VERSION 5.8 ;
BUSBITCHARS "[]" ;
DIVIDERCHAR "/" ;
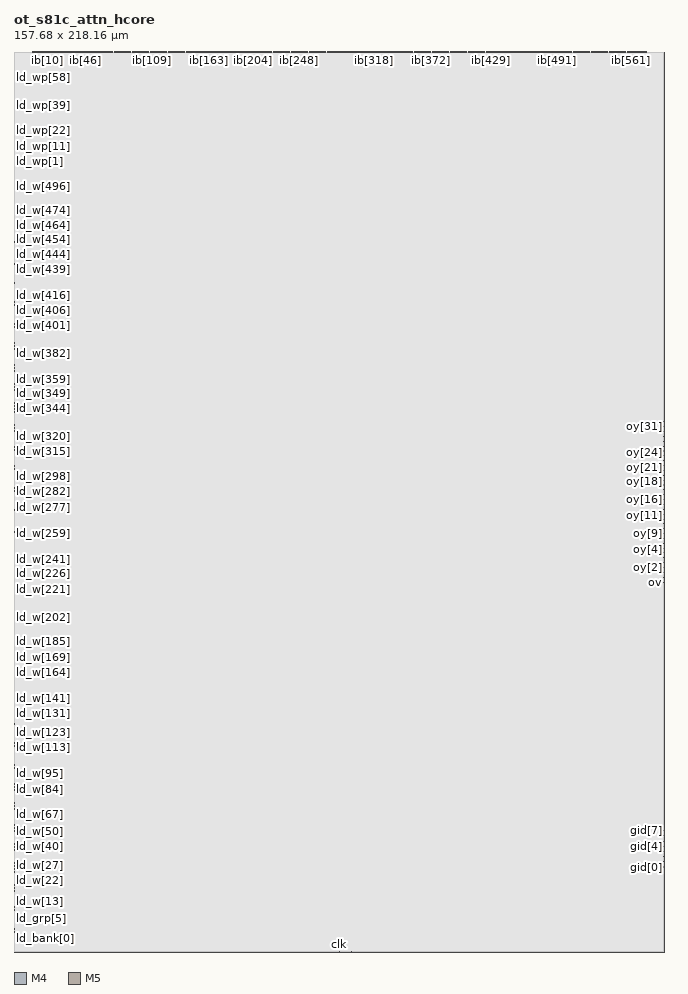
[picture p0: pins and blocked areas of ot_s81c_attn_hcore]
MACRO ot_s81c_attn_hcore
  CLASS BLOCK ;
  ORIGIN 0 0 ;
  FOREIGN ot_s81c_attn_hcore 0 0 ;
  SIZE 157.68 BY 218.16 ;
  SYMMETRY X Y ;
  PIN ld_v
    DIRECTION INPUT ;
    USE SIGNAL ;
    PORT
      LAYER M4 ;
        RECT 0.000 4.464 0.192 4.488 ;
    END
  END ld_v
  PIN ld_mode
    DIRECTION INPUT ;
    USE SIGNAL ;
    PORT
      LAYER M4 ;
        RECT 0.000 4.848 0.192 4.872 ;
    END
  END ld_mode
  PIN ld_bank[0]
    DIRECTION INPUT ;
    USE SIGNAL ;
    PORT
      LAYER M4 ;
        RECT 0.000 5.184 0.192 5.208 ;
    END
  END ld_bank[0]
  PIN ld_bank[1]
    DIRECTION INPUT ;
    USE SIGNAL ;
    PORT
      LAYER M4 ;
        RECT 0.000 5.568 0.192 5.592 ;
    END
  END ld_bank[1]
  PIN ld_bank[2]
    DIRECTION INPUT ;
    USE SIGNAL ;
    PORT
      LAYER M4 ;
        RECT 0.000 5.904 0.192 5.928 ;
    END
  END ld_bank[2]
  PIN ld_grp[0]
    DIRECTION INPUT ;
    USE SIGNAL ;
    PORT
      LAYER M4 ;
        RECT 0.000 6.240 0.192 6.264 ;
    END
  END ld_grp[0]
  PIN ld_grp[1]
    DIRECTION INPUT ;
    USE SIGNAL ;
    PORT
      LAYER M4 ;
        RECT 0.000 6.624 0.192 6.648 ;
    END
  END ld_grp[1]
  PIN ld_grp[2]
    DIRECTION INPUT ;
    USE SIGNAL ;
    PORT
      LAYER M4 ;
        RECT 0.000 6.960 0.192 6.984 ;
    END
  END ld_grp[2]
  PIN ld_grp[3]
    DIRECTION INPUT ;
    USE SIGNAL ;
    PORT
      LAYER M4 ;
        RECT 0.000 7.344 0.192 7.368 ;
    END
  END ld_grp[3]
  PIN ld_grp[4]
    DIRECTION INPUT ;
    USE SIGNAL ;
    PORT
      LAYER M4 ;
        RECT 0.000 7.680 0.192 7.704 ;
    END
  END ld_grp[4]
  PIN ld_grp[5]
    DIRECTION INPUT ;
    USE SIGNAL ;
    PORT
      LAYER M4 ;
        RECT 0.000 8.016 0.192 8.040 ;
    END
  END ld_grp[5]
  PIN ld_grp[6]
    DIRECTION INPUT ;
    USE SIGNAL ;
    PORT
      LAYER M4 ;
        RECT 0.000 8.400 0.192 8.424 ;
    END
  END ld_grp[6]
  PIN ld_grp[7]
    DIRECTION INPUT ;
    USE SIGNAL ;
    PORT
      LAYER M4 ;
        RECT 0.000 8.736 0.192 8.760 ;
    END
  END ld_grp[7]
  PIN ld_w2v
    DIRECTION INPUT ;
    USE SIGNAL ;
    PORT
      LAYER M4 ;
        RECT 0.000 9.120 0.192 9.144 ;
    END
  END ld_w2v
  PIN ld_w[0]
    DIRECTION INPUT ;
    USE SIGNAL ;
    PORT
      LAYER M4 ;
        RECT 0.000 9.456 0.192 9.480 ;
    END
  END ld_w[0]
  PIN ld_w[1]
    DIRECTION INPUT ;
    USE SIGNAL ;
    PORT
      LAYER M4 ;
        RECT 0.000 9.792 0.192 9.816 ;
    END
  END ld_w[1]
  PIN ld_w[2]
    DIRECTION INPUT ;
    USE SIGNAL ;
    PORT
      LAYER M4 ;
        RECT 0.000 10.176 0.192 10.200 ;
    END
  END ld_w[2]
  PIN ld_w[3]
    DIRECTION INPUT ;
    USE SIGNAL ;
    PORT
      LAYER M4 ;
        RECT 0.000 10.512 0.192 10.536 ;
    END
  END ld_w[3]
  PIN ld_w[4]
    DIRECTION INPUT ;
    USE SIGNAL ;
    PORT
      LAYER M4 ;
        RECT 0.000 10.896 0.192 10.920 ;
    END
  END ld_w[4]
  PIN ld_w[5]
    DIRECTION INPUT ;
    USE SIGNAL ;
    PORT
      LAYER M4 ;
        RECT 0.000 11.232 0.192 11.256 ;
    END
  END ld_w[5]
  PIN ld_w[6]
    DIRECTION INPUT ;
    USE SIGNAL ;
    PORT
      LAYER M4 ;
        RECT 0.000 11.568 0.192 11.592 ;
    END
  END ld_w[6]
  PIN ld_w[7]
    DIRECTION INPUT ;
    USE SIGNAL ;
    PORT
      LAYER M4 ;
        RECT 0.000 11.952 0.192 11.976 ;
    END
  END ld_w[7]
  PIN ld_w[8]
    DIRECTION INPUT ;
    USE SIGNAL ;
    PORT
      LAYER M4 ;
        RECT 0.000 12.288 0.192 12.312 ;
    END
  END ld_w[8]
  PIN ld_w[9]
    DIRECTION INPUT ;
    USE SIGNAL ;
    PORT
      LAYER M4 ;
        RECT 0.000 12.672 0.192 12.696 ;
    END
  END ld_w[9]
  PIN ld_w[10]
    DIRECTION INPUT ;
    USE SIGNAL ;
    PORT
      LAYER M4 ;
        RECT 0.000 13.008 0.192 13.032 ;
    END
  END ld_w[10]
  PIN ld_w[11]
    DIRECTION INPUT ;
    USE SIGNAL ;
    PORT
      LAYER M4 ;
        RECT 0.000 13.344 0.192 13.368 ;
    END
  END ld_w[11]
  PIN ld_w[12]
    DIRECTION INPUT ;
    USE SIGNAL ;
    PORT
      LAYER M4 ;
        RECT 0.000 13.728 0.192 13.752 ;
    END
  END ld_w[12]
  PIN ld_w[13]
    DIRECTION INPUT ;
    USE SIGNAL ;
    PORT
      LAYER M4 ;
        RECT 0.000 14.064 0.192 14.088 ;
    END
  END ld_w[13]
  PIN ld_w[14]
    DIRECTION INPUT ;
    USE SIGNAL ;
    PORT
      LAYER M4 ;
        RECT 0.000 14.448 0.192 14.472 ;
    END
  END ld_w[14]
  PIN ld_w[15]
    DIRECTION INPUT ;
    USE SIGNAL ;
    PORT
      LAYER M4 ;
        RECT 0.000 14.784 0.192 14.808 ;
    END
  END ld_w[15]
  PIN ld_w[16]
    DIRECTION INPUT ;
    USE SIGNAL ;
    PORT
      LAYER M4 ;
        RECT 0.000 15.120 0.192 15.144 ;
    END
  END ld_w[16]
  PIN ld_w[17]
    DIRECTION INPUT ;
    USE SIGNAL ;
    PORT
      LAYER M4 ;
        RECT 0.000 15.504 0.192 15.528 ;
    END
  END ld_w[17]
  PIN ld_w[18]
    DIRECTION INPUT ;
    USE SIGNAL ;
    PORT
      LAYER M4 ;
        RECT 0.000 15.840 0.192 15.864 ;
    END
  END ld_w[18]
  PIN ld_w[19]
    DIRECTION INPUT ;
    USE SIGNAL ;
    PORT
      LAYER M4 ;
        RECT 0.000 16.224 0.192 16.248 ;
    END
  END ld_w[19]
  PIN ld_w[20]
    DIRECTION INPUT ;
    USE SIGNAL ;
    PORT
      LAYER M4 ;
        RECT 0.000 16.560 0.192 16.584 ;
    END
  END ld_w[20]
  PIN ld_w[21]
    DIRECTION INPUT ;
    USE SIGNAL ;
    PORT
      LAYER M4 ;
        RECT 0.000 16.896 0.192 16.920 ;
    END
  END ld_w[21]
  PIN ld_w[22]
    DIRECTION INPUT ;
    USE SIGNAL ;
    PORT
      LAYER M4 ;
        RECT 0.000 17.280 0.192 17.304 ;
    END
  END ld_w[22]
  PIN ld_w[23]
    DIRECTION INPUT ;
    USE SIGNAL ;
    PORT
      LAYER M4 ;
        RECT 0.000 17.616 0.192 17.640 ;
    END
  END ld_w[23]
  PIN ld_w[24]
    DIRECTION INPUT ;
    USE SIGNAL ;
    PORT
      LAYER M4 ;
        RECT 0.000 18.000 0.192 18.024 ;
    END
  END ld_w[24]
  PIN ld_w[25]
    DIRECTION INPUT ;
    USE SIGNAL ;
    PORT
      LAYER M4 ;
        RECT 0.000 18.336 0.192 18.360 ;
    END
  END ld_w[25]
  PIN ld_w[26]
    DIRECTION INPUT ;
    USE SIGNAL ;
    PORT
      LAYER M4 ;
        RECT 0.000 18.672 0.192 18.696 ;
    END
  END ld_w[26]
  PIN ld_w[27]
    DIRECTION INPUT ;
    USE SIGNAL ;
    PORT
      LAYER M4 ;
        RECT 0.000 19.056 0.192 19.080 ;
    END
  END ld_w[27]
  PIN ld_w[28]
    DIRECTION INPUT ;
    USE SIGNAL ;
    PORT
      LAYER M4 ;
        RECT 0.000 19.392 0.192 19.416 ;
    END
  END ld_w[28]
  PIN ld_w[29]
    DIRECTION INPUT ;
    USE SIGNAL ;
    PORT
      LAYER M4 ;
        RECT 0.000 19.776 0.192 19.800 ;
    END
  END ld_w[29]
  PIN ld_w[30]
    DIRECTION INPUT ;
    USE SIGNAL ;
    PORT
      LAYER M4 ;
        RECT 0.000 20.112 0.192 20.136 ;
    END
  END ld_w[30]
  PIN ld_w[31]
    DIRECTION INPUT ;
    USE SIGNAL ;
    PORT
      LAYER M4 ;
        RECT 0.000 20.448 0.192 20.472 ;
    END
  END ld_w[31]
  PIN ld_w[32]
    DIRECTION INPUT ;
    USE SIGNAL ;
    PORT
      LAYER M4 ;
        RECT 0.000 20.832 0.192 20.856 ;
    END
  END ld_w[32]
  PIN ld_w[33]
    DIRECTION INPUT ;
    USE SIGNAL ;
    PORT
      LAYER M4 ;
        RECT 0.000 21.168 0.192 21.192 ;
    END
  END ld_w[33]
  PIN ld_w[34]
    DIRECTION INPUT ;
    USE SIGNAL ;
    PORT
      LAYER M4 ;
        RECT 0.000 21.552 0.192 21.576 ;
    END
  END ld_w[34]
  PIN ld_w[35]
    DIRECTION INPUT ;
    USE SIGNAL ;
    PORT
      LAYER M4 ;
        RECT 0.000 21.888 0.192 21.912 ;
    END
  END ld_w[35]
  PIN ld_w[36]
    DIRECTION INPUT ;
    USE SIGNAL ;
    PORT
      LAYER M4 ;
        RECT 0.000 22.224 0.192 22.248 ;
    END
  END ld_w[36]
  PIN ld_w[37]
    DIRECTION INPUT ;
    USE SIGNAL ;
    PORT
      LAYER M4 ;
        RECT 0.000 22.608 0.192 22.632 ;
    END
  END ld_w[37]
  PIN ld_w[38]
    DIRECTION INPUT ;
    USE SIGNAL ;
    PORT
      LAYER M4 ;
        RECT 0.000 22.944 0.192 22.968 ;
    END
  END ld_w[38]
  PIN ld_w[39]
    DIRECTION INPUT ;
    USE SIGNAL ;
    PORT
      LAYER M4 ;
        RECT 0.000 23.328 0.192 23.352 ;
    END
  END ld_w[39]
  PIN ld_w[40]
    DIRECTION INPUT ;
    USE SIGNAL ;
    PORT
      LAYER M4 ;
        RECT 0.000 23.664 0.192 23.688 ;
    END
  END ld_w[40]
  PIN ld_w[41]
    DIRECTION INPUT ;
    USE SIGNAL ;
    PORT
      LAYER M4 ;
        RECT 0.000 24.000 0.192 24.024 ;
    END
  END ld_w[41]
  PIN ld_w[42]
    DIRECTION INPUT ;
    USE SIGNAL ;
    PORT
      LAYER M4 ;
        RECT 0.000 24.384 0.192 24.408 ;
    END
  END ld_w[42]
  PIN ld_w[43]
    DIRECTION INPUT ;
    USE SIGNAL ;
    PORT
      LAYER M4 ;
        RECT 0.000 24.720 0.192 24.744 ;
    END
  END ld_w[43]
  PIN ld_w[44]
    DIRECTION INPUT ;
    USE SIGNAL ;
    PORT
      LAYER M4 ;
        RECT 0.000 25.104 0.192 25.128 ;
    END
  END ld_w[44]
  PIN ld_w[45]
    DIRECTION INPUT ;
    USE SIGNAL ;
    PORT
      LAYER M4 ;
        RECT 0.000 25.440 0.192 25.464 ;
    END
  END ld_w[45]
  PIN ld_w[46]
    DIRECTION INPUT ;
    USE SIGNAL ;
    PORT
      LAYER M4 ;
        RECT 0.000 25.776 0.192 25.800 ;
    END
  END ld_w[46]
  PIN ld_w[47]
    DIRECTION INPUT ;
    USE SIGNAL ;
    PORT
      LAYER M4 ;
        RECT 0.000 26.160 0.192 26.184 ;
    END
  END ld_w[47]
  PIN ld_w[48]
    DIRECTION INPUT ;
    USE SIGNAL ;
    PORT
      LAYER M4 ;
        RECT 0.000 26.496 0.192 26.520 ;
    END
  END ld_w[48]
  PIN ld_w[49]
    DIRECTION INPUT ;
    USE SIGNAL ;
    PORT
      LAYER M4 ;
        RECT 0.000 26.880 0.192 26.904 ;
    END
  END ld_w[49]
  PIN ld_w[50]
    DIRECTION INPUT ;
    USE SIGNAL ;
    PORT
      LAYER M4 ;
        RECT 0.000 27.216 0.192 27.240 ;
    END
  END ld_w[50]
  PIN ld_w[51]
    DIRECTION INPUT ;
    USE SIGNAL ;
    PORT
      LAYER M4 ;
        RECT 0.000 27.552 0.192 27.576 ;
    END
  END ld_w[51]
  PIN ld_w[52]
    DIRECTION INPUT ;
    USE SIGNAL ;
    PORT
      LAYER M4 ;
        RECT 0.000 27.936 0.192 27.960 ;
    END
  END ld_w[52]
  PIN ld_w[53]
    DIRECTION INPUT ;
    USE SIGNAL ;
    PORT
      LAYER M4 ;
        RECT 0.000 28.272 0.192 28.296 ;
    END
  END ld_w[53]
  PIN ld_w[54]
    DIRECTION INPUT ;
    USE SIGNAL ;
    PORT
      LAYER M4 ;
        RECT 0.000 28.656 0.192 28.680 ;
    END
  END ld_w[54]
  PIN ld_w[55]
    DIRECTION INPUT ;
    USE SIGNAL ;
    PORT
      LAYER M4 ;
        RECT 0.000 28.992 0.192 29.016 ;
    END
  END ld_w[55]
  PIN ld_w[56]
    DIRECTION INPUT ;
    USE SIGNAL ;
    PORT
      LAYER M4 ;
        RECT 0.000 29.328 0.192 29.352 ;
    END
  END ld_w[56]
  PIN ld_w[57]
    DIRECTION INPUT ;
    USE SIGNAL ;
    PORT
      LAYER M4 ;
        RECT 0.000 29.712 0.192 29.736 ;
    END
  END ld_w[57]
  PIN ld_w[58]
    DIRECTION INPUT ;
    USE SIGNAL ;
    PORT
      LAYER M4 ;
        RECT 0.000 30.048 0.192 30.072 ;
    END
  END ld_w[58]
  PIN ld_w[59]
    DIRECTION INPUT ;
    USE SIGNAL ;
    PORT
      LAYER M4 ;
        RECT 0.000 30.432 0.192 30.456 ;
    END
  END ld_w[59]
  PIN ld_w[60]
    DIRECTION INPUT ;
    USE SIGNAL ;
    PORT
      LAYER M4 ;
        RECT 0.000 30.768 0.192 30.792 ;
    END
  END ld_w[60]
  PIN ld_w[61]
    DIRECTION INPUT ;
    USE SIGNAL ;
    PORT
      LAYER M4 ;
        RECT 0.000 31.104 0.192 31.128 ;
    END
  END ld_w[61]
  PIN ld_w[62]
    DIRECTION INPUT ;
    USE SIGNAL ;
    PORT
      LAYER M4 ;
        RECT 0.000 31.488 0.192 31.512 ;
    END
  END ld_w[62]
  PIN ld_w[63]
    DIRECTION INPUT ;
    USE SIGNAL ;
    PORT
      LAYER M4 ;
        RECT 0.000 31.824 0.192 31.848 ;
    END
  END ld_w[63]
  PIN ld_w[64]
    DIRECTION INPUT ;
    USE SIGNAL ;
    PORT
      LAYER M4 ;
        RECT 0.000 32.208 0.192 32.232 ;
    END
  END ld_w[64]
  PIN ld_w[65]
    DIRECTION INPUT ;
    USE SIGNAL ;
    PORT
      LAYER M4 ;
        RECT 0.000 32.544 0.192 32.568 ;
    END
  END ld_w[65]
  PIN ld_w[66]
    DIRECTION INPUT ;
    USE SIGNAL ;
    PORT
      LAYER M4 ;
        RECT 0.000 32.880 0.192 32.904 ;
    END
  END ld_w[66]
  PIN ld_w[67]
    DIRECTION INPUT ;
    USE SIGNAL ;
    PORT
      LAYER M4 ;
        RECT 0.000 33.264 0.192 33.288 ;
    END
  END ld_w[67]
  PIN ld_w[68]
    DIRECTION INPUT ;
    USE SIGNAL ;
    PORT
      LAYER M4 ;
        RECT 0.000 33.600 0.192 33.624 ;
    END
  END ld_w[68]
  PIN ld_w[69]
    DIRECTION INPUT ;
    USE SIGNAL ;
    PORT
      LAYER M4 ;
        RECT 0.000 33.984 0.192 34.008 ;
    END
  END ld_w[69]
  PIN ld_w[70]
    DIRECTION INPUT ;
    USE SIGNAL ;
    PORT
      LAYER M4 ;
        RECT 0.000 34.320 0.192 34.344 ;
    END
  END ld_w[70]
  PIN ld_w[71]
    DIRECTION INPUT ;
    USE SIGNAL ;
    PORT
      LAYER M4 ;
        RECT 0.000 34.656 0.192 34.680 ;
    END
  END ld_w[71]
  PIN ld_w[72]
    DIRECTION INPUT ;
    USE SIGNAL ;
    PORT
      LAYER M4 ;
        RECT 0.000 35.040 0.192 35.064 ;
    END
  END ld_w[72]
  PIN ld_w[73]
    DIRECTION INPUT ;
    USE SIGNAL ;
    PORT
      LAYER M4 ;
        RECT 0.000 35.376 0.192 35.400 ;
    END
  END ld_w[73]
  PIN ld_w[74]
    DIRECTION INPUT ;
    USE SIGNAL ;
    PORT
      LAYER M4 ;
        RECT 0.000 35.760 0.192 35.784 ;
    END
  END ld_w[74]
  PIN ld_w[75]
    DIRECTION INPUT ;
    USE SIGNAL ;
    PORT
      LAYER M4 ;
        RECT 0.000 36.096 0.192 36.120 ;
    END
  END ld_w[75]
  PIN ld_w[76]
    DIRECTION INPUT ;
    USE SIGNAL ;
    PORT
      LAYER M4 ;
        RECT 0.000 36.432 0.192 36.456 ;
    END
  END ld_w[76]
  PIN ld_w[77]
    DIRECTION INPUT ;
    USE SIGNAL ;
    PORT
      LAYER M4 ;
        RECT 0.000 36.816 0.192 36.840 ;
    END
  END ld_w[77]
  PIN ld_w[78]
    DIRECTION INPUT ;
    USE SIGNAL ;
    PORT
      LAYER M4 ;
        RECT 0.000 37.152 0.192 37.176 ;
    END
  END ld_w[78]
  PIN ld_w[79]
    DIRECTION INPUT ;
    USE SIGNAL ;
    PORT
      LAYER M4 ;
        RECT 0.000 37.488 0.192 37.512 ;
    END
  END ld_w[79]
  PIN ld_w[80]
    DIRECTION INPUT ;
    USE SIGNAL ;
    PORT
      LAYER M4 ;
        RECT 0.000 37.872 0.192 37.896 ;
    END
  END ld_w[80]
  PIN ld_w[81]
    DIRECTION INPUT ;
    USE SIGNAL ;
    PORT
      LAYER M4 ;
        RECT 0.000 38.208 0.192 38.232 ;
    END
  END ld_w[81]
  PIN ld_w[82]
    DIRECTION INPUT ;
    USE SIGNAL ;
    PORT
      LAYER M4 ;
        RECT 0.000 38.592 0.192 38.616 ;
    END
  END ld_w[82]
  PIN ld_w[83]
    DIRECTION INPUT ;
    USE SIGNAL ;
    PORT
      LAYER M4 ;
        RECT 0.000 38.928 0.192 38.952 ;
    END
  END ld_w[83]
  PIN ld_w[84]
    DIRECTION INPUT ;
    USE SIGNAL ;
    PORT
      LAYER M4 ;
        RECT 0.000 39.264 0.192 39.288 ;
    END
  END ld_w[84]
  PIN ld_w[85]
    DIRECTION INPUT ;
    USE SIGNAL ;
    PORT
      LAYER M4 ;
        RECT 0.000 39.648 0.192 39.672 ;
    END
  END ld_w[85]
  PIN ld_w[86]
    DIRECTION INPUT ;
    USE SIGNAL ;
    PORT
      LAYER M4 ;
        RECT 0.000 39.984 0.192 40.008 ;
    END
  END ld_w[86]
  PIN ld_w[87]
    DIRECTION INPUT ;
    USE SIGNAL ;
    PORT
      LAYER M4 ;
        RECT 0.000 40.368 0.192 40.392 ;
    END
  END ld_w[87]
  PIN ld_w[88]
    DIRECTION INPUT ;
    USE SIGNAL ;
    PORT
      LAYER M4 ;
        RECT 0.000 40.704 0.192 40.728 ;
    END
  END ld_w[88]
  PIN ld_w[89]
    DIRECTION INPUT ;
    USE SIGNAL ;
    PORT
      LAYER M4 ;
        RECT 0.000 41.040 0.192 41.064 ;
    END
  END ld_w[89]
  PIN ld_w[90]
    DIRECTION INPUT ;
    USE SIGNAL ;
    PORT
      LAYER M4 ;
        RECT 0.000 41.424 0.192 41.448 ;
    END
  END ld_w[90]
  PIN ld_w[91]
    DIRECTION INPUT ;
    USE SIGNAL ;
    PORT
      LAYER M4 ;
        RECT 0.000 41.760 0.192 41.784 ;
    END
  END ld_w[91]
  PIN ld_w[92]
    DIRECTION INPUT ;
    USE SIGNAL ;
    PORT
      LAYER M4 ;
        RECT 0.000 42.144 0.192 42.168 ;
    END
  END ld_w[92]
  PIN ld_w[93]
    DIRECTION INPUT ;
    USE SIGNAL ;
    PORT
      LAYER M4 ;
        RECT 0.000 42.480 0.192 42.504 ;
    END
  END ld_w[93]
  PIN ld_w[94]
    DIRECTION INPUT ;
    USE SIGNAL ;
    PORT
      LAYER M4 ;
        RECT 0.000 42.816 0.192 42.840 ;
    END
  END ld_w[94]
  PIN ld_w[95]
    DIRECTION INPUT ;
    USE SIGNAL ;
    PORT
      LAYER M4 ;
        RECT 0.000 43.200 0.192 43.224 ;
    END
  END ld_w[95]
  PIN ld_w[96]
    DIRECTION INPUT ;
    USE SIGNAL ;
    PORT
      LAYER M4 ;
        RECT 0.000 43.536 0.192 43.560 ;
    END
  END ld_w[96]
  PIN ld_w[97]
    DIRECTION INPUT ;
    USE SIGNAL ;
    PORT
      LAYER M4 ;
        RECT 0.000 43.920 0.192 43.944 ;
    END
  END ld_w[97]
  PIN ld_w[98]
    DIRECTION INPUT ;
    USE SIGNAL ;
    PORT
      LAYER M4 ;
        RECT 0.000 44.256 0.192 44.280 ;
    END
  END ld_w[98]
  PIN ld_w[99]
    DIRECTION INPUT ;
    USE SIGNAL ;
    PORT
      LAYER M4 ;
        RECT 0.000 44.592 0.192 44.616 ;
    END
  END ld_w[99]
  PIN ld_w[100]
    DIRECTION INPUT ;
    USE SIGNAL ;
    PORT
      LAYER M4 ;
        RECT 0.000 44.976 0.192 45.000 ;
    END
  END ld_w[100]
  PIN ld_w[101]
    DIRECTION INPUT ;
    USE SIGNAL ;
    PORT
      LAYER M4 ;
        RECT 0.000 45.312 0.192 45.336 ;
    END
  END ld_w[101]
  PIN ld_w[102]
    DIRECTION INPUT ;
    USE SIGNAL ;
    PORT
      LAYER M4 ;
        RECT 0.000 45.696 0.192 45.720 ;
    END
  END ld_w[102]
  PIN ld_w[103]
    DIRECTION INPUT ;
    USE SIGNAL ;
    PORT
      LAYER M4 ;
        RECT 0.000 46.032 0.192 46.056 ;
    END
  END ld_w[103]
  PIN ld_w[104]
    DIRECTION INPUT ;
    USE SIGNAL ;
    PORT
      LAYER M4 ;
        RECT 0.000 46.368 0.192 46.392 ;
    END
  END ld_w[104]
  PIN ld_w[105]
    DIRECTION INPUT ;
    USE SIGNAL ;
    PORT
      LAYER M4 ;
        RECT 0.000 46.752 0.192 46.776 ;
    END
  END ld_w[105]
  PIN ld_w[106]
    DIRECTION INPUT ;
    USE SIGNAL ;
    PORT
      LAYER M4 ;
        RECT 0.000 47.088 0.192 47.112 ;
    END
  END ld_w[106]
  PIN ld_w[107]
    DIRECTION INPUT ;
    USE SIGNAL ;
    PORT
      LAYER M4 ;
        RECT 0.000 47.472 0.192 47.496 ;
    END
  END ld_w[107]
  PIN ld_w[108]
    DIRECTION INPUT ;
    USE SIGNAL ;
    PORT
      LAYER M4 ;
        RECT 0.000 47.808 0.192 47.832 ;
    END
  END ld_w[108]
  PIN ld_w[109]
    DIRECTION INPUT ;
    USE SIGNAL ;
    PORT
      LAYER M4 ;
        RECT 0.000 48.144 0.192 48.168 ;
    END
  END ld_w[109]
  PIN ld_w[110]
    DIRECTION INPUT ;
    USE SIGNAL ;
    PORT
      LAYER M4 ;
        RECT 0.000 48.528 0.192 48.552 ;
    END
  END ld_w[110]
  PIN ld_w[111]
    DIRECTION INPUT ;
    USE SIGNAL ;
    PORT
      LAYER M4 ;
        RECT 0.000 48.864 0.192 48.888 ;
    END
  END ld_w[111]
  PIN ld_w[112]
    DIRECTION INPUT ;
    USE SIGNAL ;
    PORT
      LAYER M4 ;
        RECT 0.000 49.248 0.192 49.272 ;
    END
  END ld_w[112]
  PIN ld_w[113]
    DIRECTION INPUT ;
    USE SIGNAL ;
    PORT
      LAYER M4 ;
        RECT 0.000 49.584 0.192 49.608 ;
    END
  END ld_w[113]
  PIN ld_w[114]
    DIRECTION INPUT ;
    USE SIGNAL ;
    PORT
      LAYER M4 ;
        RECT 0.000 49.920 0.192 49.944 ;
    END
  END ld_w[114]
  PIN ld_w[115]
    DIRECTION INPUT ;
    USE SIGNAL ;
    PORT
      LAYER M4 ;
        RECT 0.000 50.304 0.192 50.328 ;
    END
  END ld_w[115]
  PIN ld_w[116]
    DIRECTION INPUT ;
    USE SIGNAL ;
    PORT
      LAYER M4 ;
        RECT 0.000 50.640 0.192 50.664 ;
    END
  END ld_w[116]
  PIN ld_w[117]
    DIRECTION INPUT ;
    USE SIGNAL ;
    PORT
      LAYER M4 ;
        RECT 0.000 51.024 0.192 51.048 ;
    END
  END ld_w[117]
  PIN ld_w[118]
    DIRECTION INPUT ;
    USE SIGNAL ;
    PORT
      LAYER M4 ;
        RECT 0.000 51.360 0.192 51.384 ;
    END
  END ld_w[118]
  PIN ld_w[119]
    DIRECTION INPUT ;
    USE SIGNAL ;
    PORT
      LAYER M4 ;
        RECT 0.000 51.696 0.192 51.720 ;
    END
  END ld_w[119]
  PIN ld_w[120]
    DIRECTION INPUT ;
    USE SIGNAL ;
    PORT
      LAYER M4 ;
        RECT 0.000 52.080 0.192 52.104 ;
    END
  END ld_w[120]
  PIN ld_w[121]
    DIRECTION INPUT ;
    USE SIGNAL ;
    PORT
      LAYER M4 ;
        RECT 0.000 52.416 0.192 52.440 ;
    END
  END ld_w[121]
  PIN ld_w[122]
    DIRECTION INPUT ;
    USE SIGNAL ;
    PORT
      LAYER M4 ;
        RECT 0.000 52.800 0.192 52.824 ;
    END
  END ld_w[122]
  PIN ld_w[123]
    DIRECTION INPUT ;
    USE SIGNAL ;
    PORT
      LAYER M4 ;
        RECT 0.000 53.136 0.192 53.160 ;
    END
  END ld_w[123]
  PIN ld_w[124]
    DIRECTION INPUT ;
    USE SIGNAL ;
    PORT
      LAYER M4 ;
        RECT 0.000 53.472 0.192 53.496 ;
    END
  END ld_w[124]
  PIN ld_w[125]
    DIRECTION INPUT ;
    USE SIGNAL ;
    PORT
      LAYER M4 ;
        RECT 0.000 53.856 0.192 53.880 ;
    END
  END ld_w[125]
  PIN ld_w[126]
    DIRECTION INPUT ;
    USE SIGNAL ;
    PORT
      LAYER M4 ;
        RECT 0.000 54.192 0.192 54.216 ;
    END
  END ld_w[126]
  PIN ld_w[127]
    DIRECTION INPUT ;
    USE SIGNAL ;
    PORT
      LAYER M4 ;
        RECT 0.000 54.576 0.192 54.600 ;
    END
  END ld_w[127]
  PIN ld_w[128]
    DIRECTION INPUT ;
    USE SIGNAL ;
    PORT
      LAYER M4 ;
        RECT 0.000 54.912 0.192 54.936 ;
    END
  END ld_w[128]
  PIN ld_w[129]
    DIRECTION INPUT ;
    USE SIGNAL ;
    PORT
      LAYER M4 ;
        RECT 0.000 55.248 0.192 55.272 ;
    END
  END ld_w[129]
  PIN ld_w[130]
    DIRECTION INPUT ;
    USE SIGNAL ;
    PORT
      LAYER M4 ;
        RECT 0.000 55.632 0.192 55.656 ;
    END
  END ld_w[130]
  PIN ld_w[131]
    DIRECTION INPUT ;
    USE SIGNAL ;
    PORT
      LAYER M4 ;
        RECT 0.000 55.968 0.192 55.992 ;
    END
  END ld_w[131]
  PIN ld_w[132]
    DIRECTION INPUT ;
    USE SIGNAL ;
    PORT
      LAYER M4 ;
        RECT 0.000 56.352 0.192 56.376 ;
    END
  END ld_w[132]
  PIN ld_w[133]
    DIRECTION INPUT ;
    USE SIGNAL ;
    PORT
      LAYER M4 ;
        RECT 0.000 56.688 0.192 56.712 ;
    END
  END ld_w[133]
  PIN ld_w[134]
    DIRECTION INPUT ;
    USE SIGNAL ;
    PORT
      LAYER M4 ;
        RECT 0.000 57.024 0.192 57.048 ;
    END
  END ld_w[134]
  PIN ld_w[135]
    DIRECTION INPUT ;
    USE SIGNAL ;
    PORT
      LAYER M4 ;
        RECT 0.000 57.408 0.192 57.432 ;
    END
  END ld_w[135]
  PIN ld_w[136]
    DIRECTION INPUT ;
    USE SIGNAL ;
    PORT
      LAYER M4 ;
        RECT 0.000 57.744 0.192 57.768 ;
    END
  END ld_w[136]
  PIN ld_w[137]
    DIRECTION INPUT ;
    USE SIGNAL ;
    PORT
      LAYER M4 ;
        RECT 0.000 58.128 0.192 58.152 ;
    END
  END ld_w[137]
  PIN ld_w[138]
    DIRECTION INPUT ;
    USE SIGNAL ;
    PORT
      LAYER M4 ;
        RECT 0.000 58.464 0.192 58.488 ;
    END
  END ld_w[138]
  PIN ld_w[139]
    DIRECTION INPUT ;
    USE SIGNAL ;
    PORT
      LAYER M4 ;
        RECT 0.000 58.800 0.192 58.824 ;
    END
  END ld_w[139]
  PIN ld_w[140]
    DIRECTION INPUT ;
    USE SIGNAL ;
    PORT
      LAYER M4 ;
        RECT 0.000 59.184 0.192 59.208 ;
    END
  END ld_w[140]
  PIN ld_w[141]
    DIRECTION INPUT ;
    USE SIGNAL ;
    PORT
      LAYER M4 ;
        RECT 0.000 59.520 0.192 59.544 ;
    END
  END ld_w[141]
  PIN ld_w[142]
    DIRECTION INPUT ;
    USE SIGNAL ;
    PORT
      LAYER M4 ;
        RECT 0.000 59.904 0.192 59.928 ;
    END
  END ld_w[142]
  PIN ld_w[143]
    DIRECTION INPUT ;
    USE SIGNAL ;
    PORT
      LAYER M4 ;
        RECT 0.000 60.240 0.192 60.264 ;
    END
  END ld_w[143]
  PIN ld_w[144]
    DIRECTION INPUT ;
    USE SIGNAL ;
    PORT
      LAYER M4 ;
        RECT 0.000 60.576 0.192 60.600 ;
    END
  END ld_w[144]
  PIN ld_w[145]
    DIRECTION INPUT ;
    USE SIGNAL ;
    PORT
      LAYER M4 ;
        RECT 0.000 60.960 0.192 60.984 ;
    END
  END ld_w[145]
  PIN ld_w[146]
    DIRECTION INPUT ;
    USE SIGNAL ;
    PORT
      LAYER M4 ;
        RECT 0.000 61.296 0.192 61.320 ;
    END
  END ld_w[146]
  PIN ld_w[147]
    DIRECTION INPUT ;
    USE SIGNAL ;
    PORT
      LAYER M4 ;
        RECT 0.000 61.680 0.192 61.704 ;
    END
  END ld_w[147]
  PIN ld_w[148]
    DIRECTION INPUT ;
    USE SIGNAL ;
    PORT
      LAYER M4 ;
        RECT 0.000 62.016 0.192 62.040 ;
    END
  END ld_w[148]
  PIN ld_w[149]
    DIRECTION INPUT ;
    USE SIGNAL ;
    PORT
      LAYER M4 ;
        RECT 0.000 62.352 0.192 62.376 ;
    END
  END ld_w[149]
  PIN ld_w[150]
    DIRECTION INPUT ;
    USE SIGNAL ;
    PORT
      LAYER M4 ;
        RECT 0.000 62.736 0.192 62.760 ;
    END
  END ld_w[150]
  PIN ld_w[151]
    DIRECTION INPUT ;
    USE SIGNAL ;
    PORT
      LAYER M4 ;
        RECT 0.000 63.072 0.192 63.096 ;
    END
  END ld_w[151]
  PIN ld_w[152]
    DIRECTION INPUT ;
    USE SIGNAL ;
    PORT
      LAYER M4 ;
        RECT 0.000 63.456 0.192 63.480 ;
    END
  END ld_w[152]
  PIN ld_w[153]
    DIRECTION INPUT ;
    USE SIGNAL ;
    PORT
      LAYER M4 ;
        RECT 0.000 63.792 0.192 63.816 ;
    END
  END ld_w[153]
  PIN ld_w[154]
    DIRECTION INPUT ;
    USE SIGNAL ;
    PORT
      LAYER M4 ;
        RECT 0.000 64.128 0.192 64.152 ;
    END
  END ld_w[154]
  PIN ld_w[155]
    DIRECTION INPUT ;
    USE SIGNAL ;
    PORT
      LAYER M4 ;
        RECT 0.000 64.512 0.192 64.536 ;
    END
  END ld_w[155]
  PIN ld_w[156]
    DIRECTION INPUT ;
    USE SIGNAL ;
    PORT
      LAYER M4 ;
        RECT 0.000 64.848 0.192 64.872 ;
    END
  END ld_w[156]
  PIN ld_w[157]
    DIRECTION INPUT ;
    USE SIGNAL ;
    PORT
      LAYER M4 ;
        RECT 0.000 65.232 0.192 65.256 ;
    END
  END ld_w[157]
  PIN ld_w[158]
    DIRECTION INPUT ;
    USE SIGNAL ;
    PORT
      LAYER M4 ;
        RECT 0.000 65.568 0.192 65.592 ;
    END
  END ld_w[158]
  PIN ld_w[159]
    DIRECTION INPUT ;
    USE SIGNAL ;
    PORT
      LAYER M4 ;
        RECT 0.000 65.904 0.192 65.928 ;
    END
  END ld_w[159]
  PIN ld_w[160]
    DIRECTION INPUT ;
    USE SIGNAL ;
    PORT
      LAYER M4 ;
        RECT 0.000 66.288 0.192 66.312 ;
    END
  END ld_w[160]
  PIN ld_w[161]
    DIRECTION INPUT ;
    USE SIGNAL ;
    PORT
      LAYER M4 ;
        RECT 0.000 66.624 0.192 66.648 ;
    END
  END ld_w[161]
  PIN ld_w[162]
    DIRECTION INPUT ;
    USE SIGNAL ;
    PORT
      LAYER M4 ;
        RECT 0.000 67.008 0.192 67.032 ;
    END
  END ld_w[162]
  PIN ld_w[163]
    DIRECTION INPUT ;
    USE SIGNAL ;
    PORT
      LAYER M4 ;
        RECT 0.000 67.344 0.192 67.368 ;
    END
  END ld_w[163]
  PIN ld_w[164]
    DIRECTION INPUT ;
    USE SIGNAL ;
    PORT
      LAYER M4 ;
        RECT 0.000 67.680 0.192 67.704 ;
    END
  END ld_w[164]
  PIN ld_w[165]
    DIRECTION INPUT ;
    USE SIGNAL ;
    PORT
      LAYER M4 ;
        RECT 0.000 68.064 0.192 68.088 ;
    END
  END ld_w[165]
  PIN ld_w[166]
    DIRECTION INPUT ;
    USE SIGNAL ;
    PORT
      LAYER M4 ;
        RECT 0.000 68.400 0.192 68.424 ;
    END
  END ld_w[166]
  PIN ld_w[167]
    DIRECTION INPUT ;
    USE SIGNAL ;
    PORT
      LAYER M4 ;
        RECT 0.000 68.784 0.192 68.808 ;
    END
  END ld_w[167]
  PIN ld_w[168]
    DIRECTION INPUT ;
    USE SIGNAL ;
    PORT
      LAYER M4 ;
        RECT 0.000 69.120 0.192 69.144 ;
    END
  END ld_w[168]
  PIN ld_w[169]
    DIRECTION INPUT ;
    USE SIGNAL ;
    PORT
      LAYER M4 ;
        RECT 0.000 69.456 0.192 69.480 ;
    END
  END ld_w[169]
  PIN ld_w[170]
    DIRECTION INPUT ;
    USE SIGNAL ;
    PORT
      LAYER M4 ;
        RECT 0.000 69.840 0.192 69.864 ;
    END
  END ld_w[170]
  PIN ld_w[171]
    DIRECTION INPUT ;
    USE SIGNAL ;
    PORT
      LAYER M4 ;
        RECT 0.000 70.176 0.192 70.200 ;
    END
  END ld_w[171]
  PIN ld_w[172]
    DIRECTION INPUT ;
    USE SIGNAL ;
    PORT
      LAYER M4 ;
        RECT 0.000 70.560 0.192 70.584 ;
    END
  END ld_w[172]
  PIN ld_w[173]
    DIRECTION INPUT ;
    USE SIGNAL ;
    PORT
      LAYER M4 ;
        RECT 0.000 70.896 0.192 70.920 ;
    END
  END ld_w[173]
  PIN ld_w[174]
    DIRECTION INPUT ;
    USE SIGNAL ;
    PORT
      LAYER M4 ;
        RECT 0.000 71.232 0.192 71.256 ;
    END
  END ld_w[174]
  PIN ld_w[175]
    DIRECTION INPUT ;
    USE SIGNAL ;
    PORT
      LAYER M4 ;
        RECT 0.000 71.616 0.192 71.640 ;
    END
  END ld_w[175]
  PIN ld_w[176]
    DIRECTION INPUT ;
    USE SIGNAL ;
    PORT
      LAYER M4 ;
        RECT 0.000 71.952 0.192 71.976 ;
    END
  END ld_w[176]
  PIN ld_w[177]
    DIRECTION INPUT ;
    USE SIGNAL ;
    PORT
      LAYER M4 ;
        RECT 0.000 72.336 0.192 72.360 ;
    END
  END ld_w[177]
  PIN ld_w[178]
    DIRECTION INPUT ;
    USE SIGNAL ;
    PORT
      LAYER M4 ;
        RECT 0.000 72.672 0.192 72.696 ;
    END
  END ld_w[178]
  PIN ld_w[179]
    DIRECTION INPUT ;
    USE SIGNAL ;
    PORT
      LAYER M4 ;
        RECT 0.000 73.008 0.192 73.032 ;
    END
  END ld_w[179]
  PIN ld_w[180]
    DIRECTION INPUT ;
    USE SIGNAL ;
    PORT
      LAYER M4 ;
        RECT 0.000 73.392 0.192 73.416 ;
    END
  END ld_w[180]
  PIN ld_w[181]
    DIRECTION INPUT ;
    USE SIGNAL ;
    PORT
      LAYER M4 ;
        RECT 0.000 73.728 0.192 73.752 ;
    END
  END ld_w[181]
  PIN ld_w[182]
    DIRECTION INPUT ;
    USE SIGNAL ;
    PORT
      LAYER M4 ;
        RECT 0.000 74.112 0.192 74.136 ;
    END
  END ld_w[182]
  PIN ld_w[183]
    DIRECTION INPUT ;
    USE SIGNAL ;
    PORT
      LAYER M4 ;
        RECT 0.000 74.448 0.192 74.472 ;
    END
  END ld_w[183]
  PIN ld_w[184]
    DIRECTION INPUT ;
    USE SIGNAL ;
    PORT
      LAYER M4 ;
        RECT 0.000 74.784 0.192 74.808 ;
    END
  END ld_w[184]
  PIN ld_w[185]
    DIRECTION INPUT ;
    USE SIGNAL ;
    PORT
      LAYER M4 ;
        RECT 0.000 75.168 0.192 75.192 ;
    END
  END ld_w[185]
  PIN ld_w[186]
    DIRECTION INPUT ;
    USE SIGNAL ;
    PORT
      LAYER M4 ;
        RECT 0.000 75.504 0.192 75.528 ;
    END
  END ld_w[186]
  PIN ld_w[187]
    DIRECTION INPUT ;
    USE SIGNAL ;
    PORT
      LAYER M4 ;
        RECT 0.000 75.888 0.192 75.912 ;
    END
  END ld_w[187]
  PIN ld_w[188]
    DIRECTION INPUT ;
    USE SIGNAL ;
    PORT
      LAYER M4 ;
        RECT 0.000 76.224 0.192 76.248 ;
    END
  END ld_w[188]
  PIN ld_w[189]
    DIRECTION INPUT ;
    USE SIGNAL ;
    PORT
      LAYER M4 ;
        RECT 0.000 76.560 0.192 76.584 ;
    END
  END ld_w[189]
  PIN ld_w[190]
    DIRECTION INPUT ;
    USE SIGNAL ;
    PORT
      LAYER M4 ;
        RECT 0.000 76.944 0.192 76.968 ;
    END
  END ld_w[190]
  PIN ld_w[191]
    DIRECTION INPUT ;
    USE SIGNAL ;
    PORT
      LAYER M4 ;
        RECT 0.000 77.280 0.192 77.304 ;
    END
  END ld_w[191]
  PIN ld_w[192]
    DIRECTION INPUT ;
    USE SIGNAL ;
    PORT
      LAYER M4 ;
        RECT 0.000 77.664 0.192 77.688 ;
    END
  END ld_w[192]
  PIN ld_w[193]
    DIRECTION INPUT ;
    USE SIGNAL ;
    PORT
      LAYER M4 ;
        RECT 0.000 78.000 0.192 78.024 ;
    END
  END ld_w[193]
  PIN ld_w[194]
    DIRECTION INPUT ;
    USE SIGNAL ;
    PORT
      LAYER M4 ;
        RECT 0.000 78.336 0.192 78.360 ;
    END
  END ld_w[194]
  PIN ld_w[195]
    DIRECTION INPUT ;
    USE SIGNAL ;
    PORT
      LAYER M4 ;
        RECT 0.000 78.720 0.192 78.744 ;
    END
  END ld_w[195]
  PIN ld_w[196]
    DIRECTION INPUT ;
    USE SIGNAL ;
    PORT
      LAYER M4 ;
        RECT 0.000 79.056 0.192 79.080 ;
    END
  END ld_w[196]
  PIN ld_w[197]
    DIRECTION INPUT ;
    USE SIGNAL ;
    PORT
      LAYER M4 ;
        RECT 0.000 79.392 0.192 79.416 ;
    END
  END ld_w[197]
  PIN ld_w[198]
    DIRECTION INPUT ;
    USE SIGNAL ;
    PORT
      LAYER M4 ;
        RECT 0.000 79.776 0.192 79.800 ;
    END
  END ld_w[198]
  PIN ld_w[199]
    DIRECTION INPUT ;
    USE SIGNAL ;
    PORT
      LAYER M4 ;
        RECT 0.000 80.112 0.192 80.136 ;
    END
  END ld_w[199]
  PIN ld_w[200]
    DIRECTION INPUT ;
    USE SIGNAL ;
    PORT
      LAYER M4 ;
        RECT 0.000 80.496 0.192 80.520 ;
    END
  END ld_w[200]
  PIN ld_w[201]
    DIRECTION INPUT ;
    USE SIGNAL ;
    PORT
      LAYER M4 ;
        RECT 0.000 80.832 0.192 80.856 ;
    END
  END ld_w[201]
  PIN ld_w[202]
    DIRECTION INPUT ;
    USE SIGNAL ;
    PORT
      LAYER M4 ;
        RECT 0.000 81.168 0.192 81.192 ;
    END
  END ld_w[202]
  PIN ld_w[203]
    DIRECTION INPUT ;
    USE SIGNAL ;
    PORT
      LAYER M4 ;
        RECT 0.000 81.552 0.192 81.576 ;
    END
  END ld_w[203]
  PIN ld_w[204]
    DIRECTION INPUT ;
    USE SIGNAL ;
    PORT
      LAYER M4 ;
        RECT 0.000 81.888 0.192 81.912 ;
    END
  END ld_w[204]
  PIN ld_w[205]
    DIRECTION INPUT ;
    USE SIGNAL ;
    PORT
      LAYER M4 ;
        RECT 0.000 82.272 0.192 82.296 ;
    END
  END ld_w[205]
  PIN ld_w[206]
    DIRECTION INPUT ;
    USE SIGNAL ;
    PORT
      LAYER M4 ;
        RECT 0.000 82.608 0.192 82.632 ;
    END
  END ld_w[206]
  PIN ld_w[207]
    DIRECTION INPUT ;
    USE SIGNAL ;
    PORT
      LAYER M4 ;
        RECT 0.000 82.944 0.192 82.968 ;
    END
  END ld_w[207]
  PIN ld_w[208]
    DIRECTION INPUT ;
    USE SIGNAL ;
    PORT
      LAYER M4 ;
        RECT 0.000 83.328 0.192 83.352 ;
    END
  END ld_w[208]
  PIN ld_w[209]
    DIRECTION INPUT ;
    USE SIGNAL ;
    PORT
      LAYER M4 ;
        RECT 0.000 83.664 0.192 83.688 ;
    END
  END ld_w[209]
  PIN ld_w[210]
    DIRECTION INPUT ;
    USE SIGNAL ;
    PORT
      LAYER M4 ;
        RECT 0.000 84.048 0.192 84.072 ;
    END
  END ld_w[210]
  PIN ld_w[211]
    DIRECTION INPUT ;
    USE SIGNAL ;
    PORT
      LAYER M4 ;
        RECT 0.000 84.384 0.192 84.408 ;
    END
  END ld_w[211]
  PIN ld_w[212]
    DIRECTION INPUT ;
    USE SIGNAL ;
    PORT
      LAYER M4 ;
        RECT 0.000 84.720 0.192 84.744 ;
    END
  END ld_w[212]
  PIN ld_w[213]
    DIRECTION INPUT ;
    USE SIGNAL ;
    PORT
      LAYER M4 ;
        RECT 0.000 85.104 0.192 85.128 ;
    END
  END ld_w[213]
  PIN ld_w[214]
    DIRECTION INPUT ;
    USE SIGNAL ;
    PORT
      LAYER M4 ;
        RECT 0.000 85.440 0.192 85.464 ;
    END
  END ld_w[214]
  PIN ld_w[215]
    DIRECTION INPUT ;
    USE SIGNAL ;
    PORT
      LAYER M4 ;
        RECT 0.000 85.824 0.192 85.848 ;
    END
  END ld_w[215]
  PIN ld_w[216]
    DIRECTION INPUT ;
    USE SIGNAL ;
    PORT
      LAYER M4 ;
        RECT 0.000 86.160 0.192 86.184 ;
    END
  END ld_w[216]
  PIN ld_w[217]
    DIRECTION INPUT ;
    USE SIGNAL ;
    PORT
      LAYER M4 ;
        RECT 0.000 86.496 0.192 86.520 ;
    END
  END ld_w[217]
  PIN ld_w[218]
    DIRECTION INPUT ;
    USE SIGNAL ;
    PORT
      LAYER M4 ;
        RECT 0.000 86.880 0.192 86.904 ;
    END
  END ld_w[218]
  PIN ld_w[219]
    DIRECTION INPUT ;
    USE SIGNAL ;
    PORT
      LAYER M4 ;
        RECT 0.000 87.216 0.192 87.240 ;
    END
  END ld_w[219]
  PIN ld_w[220]
    DIRECTION INPUT ;
    USE SIGNAL ;
    PORT
      LAYER M4 ;
        RECT 0.000 87.600 0.192 87.624 ;
    END
  END ld_w[220]
  PIN ld_w[221]
    DIRECTION INPUT ;
    USE SIGNAL ;
    PORT
      LAYER M4 ;
        RECT 0.000 87.936 0.192 87.960 ;
    END
  END ld_w[221]
  PIN ld_w[222]
    DIRECTION INPUT ;
    USE SIGNAL ;
    PORT
      LAYER M4 ;
        RECT 0.000 88.272 0.192 88.296 ;
    END
  END ld_w[222]
  PIN ld_w[223]
    DIRECTION INPUT ;
    USE SIGNAL ;
    PORT
      LAYER M4 ;
        RECT 0.000 88.656 0.192 88.680 ;
    END
  END ld_w[223]
  PIN ld_w[224]
    DIRECTION INPUT ;
    USE SIGNAL ;
    PORT
      LAYER M4 ;
        RECT 0.000 88.992 0.192 89.016 ;
    END
  END ld_w[224]
  PIN ld_w[225]
    DIRECTION INPUT ;
    USE SIGNAL ;
    PORT
      LAYER M4 ;
        RECT 0.000 89.376 0.192 89.400 ;
    END
  END ld_w[225]
  PIN ld_w[226]
    DIRECTION INPUT ;
    USE SIGNAL ;
    PORT
      LAYER M4 ;
        RECT 0.000 89.712 0.192 89.736 ;
    END
  END ld_w[226]
  PIN ld_w[227]
    DIRECTION INPUT ;
    USE SIGNAL ;
    PORT
      LAYER M4 ;
        RECT 0.000 90.048 0.192 90.072 ;
    END
  END ld_w[227]
  PIN ld_w[228]
    DIRECTION INPUT ;
    USE SIGNAL ;
    PORT
      LAYER M4 ;
        RECT 0.000 90.432 0.192 90.456 ;
    END
  END ld_w[228]
  PIN ld_w[229]
    DIRECTION INPUT ;
    USE SIGNAL ;
    PORT
      LAYER M4 ;
        RECT 0.000 90.768 0.192 90.792 ;
    END
  END ld_w[229]
  PIN ld_w[230]
    DIRECTION INPUT ;
    USE SIGNAL ;
    PORT
      LAYER M4 ;
        RECT 0.000 91.152 0.192 91.176 ;
    END
  END ld_w[230]
  PIN ld_w[231]
    DIRECTION INPUT ;
    USE SIGNAL ;
    PORT
      LAYER M4 ;
        RECT 0.000 91.488 0.192 91.512 ;
    END
  END ld_w[231]
  PIN ld_w[232]
    DIRECTION INPUT ;
    USE SIGNAL ;
    PORT
      LAYER M4 ;
        RECT 0.000 91.824 0.192 91.848 ;
    END
  END ld_w[232]
  PIN ld_w[233]
    DIRECTION INPUT ;
    USE SIGNAL ;
    PORT
      LAYER M4 ;
        RECT 0.000 92.208 0.192 92.232 ;
    END
  END ld_w[233]
  PIN ld_w[234]
    DIRECTION INPUT ;
    USE SIGNAL ;
    PORT
      LAYER M4 ;
        RECT 0.000 92.544 0.192 92.568 ;
    END
  END ld_w[234]
  PIN ld_w[235]
    DIRECTION INPUT ;
    USE SIGNAL ;
    PORT
      LAYER M4 ;
        RECT 0.000 92.928 0.192 92.952 ;
    END
  END ld_w[235]
  PIN ld_w[236]
    DIRECTION INPUT ;
    USE SIGNAL ;
    PORT
      LAYER M4 ;
        RECT 0.000 93.264 0.192 93.288 ;
    END
  END ld_w[236]
  PIN ld_w[237]
    DIRECTION INPUT ;
    USE SIGNAL ;
    PORT
      LAYER M4 ;
        RECT 0.000 93.600 0.192 93.624 ;
    END
  END ld_w[237]
  PIN ld_w[238]
    DIRECTION INPUT ;
    USE SIGNAL ;
    PORT
      LAYER M4 ;
        RECT 0.000 93.984 0.192 94.008 ;
    END
  END ld_w[238]
  PIN ld_w[239]
    DIRECTION INPUT ;
    USE SIGNAL ;
    PORT
      LAYER M4 ;
        RECT 0.000 94.320 0.192 94.344 ;
    END
  END ld_w[239]
  PIN ld_w[240]
    DIRECTION INPUT ;
    USE SIGNAL ;
    PORT
      LAYER M4 ;
        RECT 0.000 94.704 0.192 94.728 ;
    END
  END ld_w[240]
  PIN ld_w[241]
    DIRECTION INPUT ;
    USE SIGNAL ;
    PORT
      LAYER M4 ;
        RECT 0.000 95.040 0.192 95.064 ;
    END
  END ld_w[241]
  PIN ld_w[242]
    DIRECTION INPUT ;
    USE SIGNAL ;
    PORT
      LAYER M4 ;
        RECT 0.000 95.376 0.192 95.400 ;
    END
  END ld_w[242]
  PIN ld_w[243]
    DIRECTION INPUT ;
    USE SIGNAL ;
    PORT
      LAYER M4 ;
        RECT 0.000 95.760 0.192 95.784 ;
    END
  END ld_w[243]
  PIN ld_w[244]
    DIRECTION INPUT ;
    USE SIGNAL ;
    PORT
      LAYER M4 ;
        RECT 0.000 96.096 0.192 96.120 ;
    END
  END ld_w[244]
  PIN ld_w[245]
    DIRECTION INPUT ;
    USE SIGNAL ;
    PORT
      LAYER M4 ;
        RECT 0.000 96.480 0.192 96.504 ;
    END
  END ld_w[245]
  PIN ld_w[246]
    DIRECTION INPUT ;
    USE SIGNAL ;
    PORT
      LAYER M4 ;
        RECT 0.000 96.816 0.192 96.840 ;
    END
  END ld_w[246]
  PIN ld_w[247]
    DIRECTION INPUT ;
    USE SIGNAL ;
    PORT
      LAYER M4 ;
        RECT 0.000 97.152 0.192 97.176 ;
    END
  END ld_w[247]
  PIN ld_w[248]
    DIRECTION INPUT ;
    USE SIGNAL ;
    PORT
      LAYER M4 ;
        RECT 0.000 97.536 0.192 97.560 ;
    END
  END ld_w[248]
  PIN ld_w[249]
    DIRECTION INPUT ;
    USE SIGNAL ;
    PORT
      LAYER M4 ;
        RECT 0.000 97.872 0.192 97.896 ;
    END
  END ld_w[249]
  PIN ld_w[250]
    DIRECTION INPUT ;
    USE SIGNAL ;
    PORT
      LAYER M4 ;
        RECT 0.000 98.256 0.192 98.280 ;
    END
  END ld_w[250]
  PIN ld_w[251]
    DIRECTION INPUT ;
    USE SIGNAL ;
    PORT
      LAYER M4 ;
        RECT 0.000 98.592 0.192 98.616 ;
    END
  END ld_w[251]
  PIN ld_w[252]
    DIRECTION INPUT ;
    USE SIGNAL ;
    PORT
      LAYER M4 ;
        RECT 0.000 98.928 0.192 98.952 ;
    END
  END ld_w[252]
  PIN ld_w[253]
    DIRECTION INPUT ;
    USE SIGNAL ;
    PORT
      LAYER M4 ;
        RECT 0.000 99.312 0.192 99.336 ;
    END
  END ld_w[253]
  PIN ld_w[254]
    DIRECTION INPUT ;
    USE SIGNAL ;
    PORT
      LAYER M4 ;
        RECT 0.000 99.648 0.192 99.672 ;
    END
  END ld_w[254]
  PIN ld_w[255]
    DIRECTION INPUT ;
    USE SIGNAL ;
    PORT
      LAYER M4 ;
        RECT 0.000 100.032 0.192 100.056 ;
    END
  END ld_w[255]
  PIN ld_w[256]
    DIRECTION INPUT ;
    USE SIGNAL ;
    PORT
      LAYER M4 ;
        RECT 0.000 100.368 0.192 100.392 ;
    END
  END ld_w[256]
  PIN ld_w[257]
    DIRECTION INPUT ;
    USE SIGNAL ;
    PORT
      LAYER M4 ;
        RECT 0.000 100.704 0.192 100.728 ;
    END
  END ld_w[257]
  PIN ld_w[258]
    DIRECTION INPUT ;
    USE SIGNAL ;
    PORT
      LAYER M4 ;
        RECT 0.000 101.088 0.192 101.112 ;
    END
  END ld_w[258]
  PIN ld_w[259]
    DIRECTION INPUT ;
    USE SIGNAL ;
    PORT
      LAYER M4 ;
        RECT 0.000 101.424 0.192 101.448 ;
    END
  END ld_w[259]
  PIN ld_w[260]
    DIRECTION INPUT ;
    USE SIGNAL ;
    PORT
      LAYER M4 ;
        RECT 0.000 101.808 0.192 101.832 ;
    END
  END ld_w[260]
  PIN ld_w[261]
    DIRECTION INPUT ;
    USE SIGNAL ;
    PORT
      LAYER M4 ;
        RECT 0.000 102.144 0.192 102.168 ;
    END
  END ld_w[261]
  PIN ld_w[262]
    DIRECTION INPUT ;
    USE SIGNAL ;
    PORT
      LAYER M4 ;
        RECT 0.000 102.480 0.192 102.504 ;
    END
  END ld_w[262]
  PIN ld_w[263]
    DIRECTION INPUT ;
    USE SIGNAL ;
    PORT
      LAYER M4 ;
        RECT 0.000 102.864 0.192 102.888 ;
    END
  END ld_w[263]
  PIN ld_w[264]
    DIRECTION INPUT ;
    USE SIGNAL ;
    PORT
      LAYER M4 ;
        RECT 0.000 103.200 0.192 103.224 ;
    END
  END ld_w[264]
  PIN ld_w[265]
    DIRECTION INPUT ;
    USE SIGNAL ;
    PORT
      LAYER M4 ;
        RECT 0.000 103.584 0.192 103.608 ;
    END
  END ld_w[265]
  PIN ld_w[266]
    DIRECTION INPUT ;
    USE SIGNAL ;
    PORT
      LAYER M4 ;
        RECT 0.000 103.920 0.192 103.944 ;
    END
  END ld_w[266]
  PIN ld_w[267]
    DIRECTION INPUT ;
    USE SIGNAL ;
    PORT
      LAYER M4 ;
        RECT 0.000 104.256 0.192 104.280 ;
    END
  END ld_w[267]
  PIN ld_w[268]
    DIRECTION INPUT ;
    USE SIGNAL ;
    PORT
      LAYER M4 ;
        RECT 0.000 104.640 0.192 104.664 ;
    END
  END ld_w[268]
  PIN ld_w[269]
    DIRECTION INPUT ;
    USE SIGNAL ;
    PORT
      LAYER M4 ;
        RECT 0.000 104.976 0.192 105.000 ;
    END
  END ld_w[269]
  PIN ld_w[270]
    DIRECTION INPUT ;
    USE SIGNAL ;
    PORT
      LAYER M4 ;
        RECT 0.000 105.360 0.192 105.384 ;
    END
  END ld_w[270]
  PIN ld_w[271]
    DIRECTION INPUT ;
    USE SIGNAL ;
    PORT
      LAYER M4 ;
        RECT 0.000 105.696 0.192 105.720 ;
    END
  END ld_w[271]
  PIN ld_w[272]
    DIRECTION INPUT ;
    USE SIGNAL ;
    PORT
      LAYER M4 ;
        RECT 0.000 106.032 0.192 106.056 ;
    END
  END ld_w[272]
  PIN ld_w[273]
    DIRECTION INPUT ;
    USE SIGNAL ;
    PORT
      LAYER M4 ;
        RECT 0.000 106.416 0.192 106.440 ;
    END
  END ld_w[273]
  PIN ld_w[274]
    DIRECTION INPUT ;
    USE SIGNAL ;
    PORT
      LAYER M4 ;
        RECT 0.000 106.752 0.192 106.776 ;
    END
  END ld_w[274]
  PIN ld_w[275]
    DIRECTION INPUT ;
    USE SIGNAL ;
    PORT
      LAYER M4 ;
        RECT 0.000 107.136 0.192 107.160 ;
    END
  END ld_w[275]
  PIN ld_w[276]
    DIRECTION INPUT ;
    USE SIGNAL ;
    PORT
      LAYER M4 ;
        RECT 0.000 107.472 0.192 107.496 ;
    END
  END ld_w[276]
  PIN ld_w[277]
    DIRECTION INPUT ;
    USE SIGNAL ;
    PORT
      LAYER M4 ;
        RECT 0.000 107.808 0.192 107.832 ;
    END
  END ld_w[277]
  PIN ld_w[278]
    DIRECTION INPUT ;
    USE SIGNAL ;
    PORT
      LAYER M4 ;
        RECT 0.000 108.192 0.192 108.216 ;
    END
  END ld_w[278]
  PIN ld_w[279]
    DIRECTION INPUT ;
    USE SIGNAL ;
    PORT
      LAYER M4 ;
        RECT 0.000 108.528 0.192 108.552 ;
    END
  END ld_w[279]
  PIN ld_w[280]
    DIRECTION INPUT ;
    USE SIGNAL ;
    PORT
      LAYER M4 ;
        RECT 0.000 108.912 0.192 108.936 ;
    END
  END ld_w[280]
  PIN ld_w[281]
    DIRECTION INPUT ;
    USE SIGNAL ;
    PORT
      LAYER M4 ;
        RECT 0.000 109.248 0.192 109.272 ;
    END
  END ld_w[281]
  PIN ld_w[282]
    DIRECTION INPUT ;
    USE SIGNAL ;
    PORT
      LAYER M4 ;
        RECT 0.000 109.584 0.192 109.608 ;
    END
  END ld_w[282]
  PIN ld_w[283]
    DIRECTION INPUT ;
    USE SIGNAL ;
    PORT
      LAYER M4 ;
        RECT 0.000 109.968 0.192 109.992 ;
    END
  END ld_w[283]
  PIN ld_w[284]
    DIRECTION INPUT ;
    USE SIGNAL ;
    PORT
      LAYER M4 ;
        RECT 0.000 110.304 0.192 110.328 ;
    END
  END ld_w[284]
  PIN ld_w[285]
    DIRECTION INPUT ;
    USE SIGNAL ;
    PORT
      LAYER M4 ;
        RECT 0.000 110.688 0.192 110.712 ;
    END
  END ld_w[285]
  PIN ld_w[286]
    DIRECTION INPUT ;
    USE SIGNAL ;
    PORT
      LAYER M4 ;
        RECT 0.000 111.024 0.192 111.048 ;
    END
  END ld_w[286]
  PIN ld_w[287]
    DIRECTION INPUT ;
    USE SIGNAL ;
    PORT
      LAYER M4 ;
        RECT 0.000 111.360 0.192 111.384 ;
    END
  END ld_w[287]
  PIN ld_w[288]
    DIRECTION INPUT ;
    USE SIGNAL ;
    PORT
      LAYER M4 ;
        RECT 0.000 111.744 0.192 111.768 ;
    END
  END ld_w[288]
  PIN ld_w[289]
    DIRECTION INPUT ;
    USE SIGNAL ;
    PORT
      LAYER M4 ;
        RECT 0.000 112.080 0.192 112.104 ;
    END
  END ld_w[289]
  PIN ld_w[290]
    DIRECTION INPUT ;
    USE SIGNAL ;
    PORT
      LAYER M4 ;
        RECT 0.000 112.464 0.192 112.488 ;
    END
  END ld_w[290]
  PIN ld_w[291]
    DIRECTION INPUT ;
    USE SIGNAL ;
    PORT
      LAYER M4 ;
        RECT 0.000 112.800 0.192 112.824 ;
    END
  END ld_w[291]
  PIN ld_w[292]
    DIRECTION INPUT ;
    USE SIGNAL ;
    PORT
      LAYER M4 ;
        RECT 0.000 113.136 0.192 113.160 ;
    END
  END ld_w[292]
  PIN ld_w[293]
    DIRECTION INPUT ;
    USE SIGNAL ;
    PORT
      LAYER M4 ;
        RECT 0.000 113.520 0.192 113.544 ;
    END
  END ld_w[293]
  PIN ld_w[294]
    DIRECTION INPUT ;
    USE SIGNAL ;
    PORT
      LAYER M4 ;
        RECT 0.000 113.856 0.192 113.880 ;
    END
  END ld_w[294]
  PIN ld_w[295]
    DIRECTION INPUT ;
    USE SIGNAL ;
    PORT
      LAYER M4 ;
        RECT 0.000 114.240 0.192 114.264 ;
    END
  END ld_w[295]
  PIN ld_w[296]
    DIRECTION INPUT ;
    USE SIGNAL ;
    PORT
      LAYER M4 ;
        RECT 0.000 114.576 0.192 114.600 ;
    END
  END ld_w[296]
  PIN ld_w[297]
    DIRECTION INPUT ;
    USE SIGNAL ;
    PORT
      LAYER M4 ;
        RECT 0.000 114.912 0.192 114.936 ;
    END
  END ld_w[297]
  PIN ld_w[298]
    DIRECTION INPUT ;
    USE SIGNAL ;
    PORT
      LAYER M4 ;
        RECT 0.000 115.296 0.192 115.320 ;
    END
  END ld_w[298]
  PIN ld_w[299]
    DIRECTION INPUT ;
    USE SIGNAL ;
    PORT
      LAYER M4 ;
        RECT 0.000 115.632 0.192 115.656 ;
    END
  END ld_w[299]
  PIN ld_w[300]
    DIRECTION INPUT ;
    USE SIGNAL ;
    PORT
      LAYER M4 ;
        RECT 0.000 116.016 0.192 116.040 ;
    END
  END ld_w[300]
  PIN ld_w[301]
    DIRECTION INPUT ;
    USE SIGNAL ;
    PORT
      LAYER M4 ;
        RECT 0.000 116.352 0.192 116.376 ;
    END
  END ld_w[301]
  PIN ld_w[302]
    DIRECTION INPUT ;
    USE SIGNAL ;
    PORT
      LAYER M4 ;
        RECT 0.000 116.688 0.192 116.712 ;
    END
  END ld_w[302]
  PIN ld_w[303]
    DIRECTION INPUT ;
    USE SIGNAL ;
    PORT
      LAYER M4 ;
        RECT 0.000 117.072 0.192 117.096 ;
    END
  END ld_w[303]
  PIN ld_w[304]
    DIRECTION INPUT ;
    USE SIGNAL ;
    PORT
      LAYER M4 ;
        RECT 0.000 117.408 0.192 117.432 ;
    END
  END ld_w[304]
  PIN ld_w[305]
    DIRECTION INPUT ;
    USE SIGNAL ;
    PORT
      LAYER M4 ;
        RECT 0.000 117.792 0.192 117.816 ;
    END
  END ld_w[305]
  PIN ld_w[306]
    DIRECTION INPUT ;
    USE SIGNAL ;
    PORT
      LAYER M4 ;
        RECT 0.000 118.128 0.192 118.152 ;
    END
  END ld_w[306]
  PIN ld_w[307]
    DIRECTION INPUT ;
    USE SIGNAL ;
    PORT
      LAYER M4 ;
        RECT 0.000 118.464 0.192 118.488 ;
    END
  END ld_w[307]
  PIN ld_w[308]
    DIRECTION INPUT ;
    USE SIGNAL ;
    PORT
      LAYER M4 ;
        RECT 0.000 118.848 0.192 118.872 ;
    END
  END ld_w[308]
  PIN ld_w[309]
    DIRECTION INPUT ;
    USE SIGNAL ;
    PORT
      LAYER M4 ;
        RECT 0.000 119.184 0.192 119.208 ;
    END
  END ld_w[309]
  PIN ld_w[310]
    DIRECTION INPUT ;
    USE SIGNAL ;
    PORT
      LAYER M4 ;
        RECT 0.000 119.520 0.192 119.544 ;
    END
  END ld_w[310]
  PIN ld_w[311]
    DIRECTION INPUT ;
    USE SIGNAL ;
    PORT
      LAYER M4 ;
        RECT 0.000 119.904 0.192 119.928 ;
    END
  END ld_w[311]
  PIN ld_w[312]
    DIRECTION INPUT ;
    USE SIGNAL ;
    PORT
      LAYER M4 ;
        RECT 0.000 120.240 0.192 120.264 ;
    END
  END ld_w[312]
  PIN ld_w[313]
    DIRECTION INPUT ;
    USE SIGNAL ;
    PORT
      LAYER M4 ;
        RECT 0.000 120.624 0.192 120.648 ;
    END
  END ld_w[313]
  PIN ld_w[314]
    DIRECTION INPUT ;
    USE SIGNAL ;
    PORT
      LAYER M4 ;
        RECT 0.000 120.960 0.192 120.984 ;
    END
  END ld_w[314]
  PIN ld_w[315]
    DIRECTION INPUT ;
    USE SIGNAL ;
    PORT
      LAYER M4 ;
        RECT 0.000 121.296 0.192 121.320 ;
    END
  END ld_w[315]
  PIN ld_w[316]
    DIRECTION INPUT ;
    USE SIGNAL ;
    PORT
      LAYER M4 ;
        RECT 0.000 121.680 0.192 121.704 ;
    END
  END ld_w[316]
  PIN ld_w[317]
    DIRECTION INPUT ;
    USE SIGNAL ;
    PORT
      LAYER M4 ;
        RECT 0.000 122.016 0.192 122.040 ;
    END
  END ld_w[317]
  PIN ld_w[318]
    DIRECTION INPUT ;
    USE SIGNAL ;
    PORT
      LAYER M4 ;
        RECT 0.000 122.400 0.192 122.424 ;
    END
  END ld_w[318]
  PIN ld_w[319]
    DIRECTION INPUT ;
    USE SIGNAL ;
    PORT
      LAYER M4 ;
        RECT 0.000 122.736 0.192 122.760 ;
    END
  END ld_w[319]
  PIN ld_w[320]
    DIRECTION INPUT ;
    USE SIGNAL ;
    PORT
      LAYER M4 ;
        RECT 0.000 123.072 0.192 123.096 ;
    END
  END ld_w[320]
  PIN ld_w[321]
    DIRECTION INPUT ;
    USE SIGNAL ;
    PORT
      LAYER M4 ;
        RECT 0.000 123.456 0.192 123.480 ;
    END
  END ld_w[321]
  PIN ld_w[322]
    DIRECTION INPUT ;
    USE SIGNAL ;
    PORT
      LAYER M4 ;
        RECT 0.000 123.792 0.192 123.816 ;
    END
  END ld_w[322]
  PIN ld_w[323]
    DIRECTION INPUT ;
    USE SIGNAL ;
    PORT
      LAYER M4 ;
        RECT 0.000 124.176 0.192 124.200 ;
    END
  END ld_w[323]
  PIN ld_w[324]
    DIRECTION INPUT ;
    USE SIGNAL ;
    PORT
      LAYER M4 ;
        RECT 0.000 124.512 0.192 124.536 ;
    END
  END ld_w[324]
  PIN ld_w[325]
    DIRECTION INPUT ;
    USE SIGNAL ;
    PORT
      LAYER M4 ;
        RECT 0.000 124.848 0.192 124.872 ;
    END
  END ld_w[325]
  PIN ld_w[326]
    DIRECTION INPUT ;
    USE SIGNAL ;
    PORT
      LAYER M4 ;
        RECT 0.000 125.232 0.192 125.256 ;
    END
  END ld_w[326]
  PIN ld_w[327]
    DIRECTION INPUT ;
    USE SIGNAL ;
    PORT
      LAYER M4 ;
        RECT 0.000 125.568 0.192 125.592 ;
    END
  END ld_w[327]
  PIN ld_w[328]
    DIRECTION INPUT ;
    USE SIGNAL ;
    PORT
      LAYER M4 ;
        RECT 0.000 125.952 0.192 125.976 ;
    END
  END ld_w[328]
  PIN ld_w[329]
    DIRECTION INPUT ;
    USE SIGNAL ;
    PORT
      LAYER M4 ;
        RECT 0.000 126.288 0.192 126.312 ;
    END
  END ld_w[329]
  PIN ld_w[330]
    DIRECTION INPUT ;
    USE SIGNAL ;
    PORT
      LAYER M4 ;
        RECT 0.000 126.624 0.192 126.648 ;
    END
  END ld_w[330]
  PIN ld_w[331]
    DIRECTION INPUT ;
    USE SIGNAL ;
    PORT
      LAYER M4 ;
        RECT 0.000 127.008 0.192 127.032 ;
    END
  END ld_w[331]
  PIN ld_w[332]
    DIRECTION INPUT ;
    USE SIGNAL ;
    PORT
      LAYER M4 ;
        RECT 0.000 127.344 0.192 127.368 ;
    END
  END ld_w[332]
  PIN ld_w[333]
    DIRECTION INPUT ;
    USE SIGNAL ;
    PORT
      LAYER M4 ;
        RECT 0.000 127.728 0.192 127.752 ;
    END
  END ld_w[333]
  PIN ld_w[334]
    DIRECTION INPUT ;
    USE SIGNAL ;
    PORT
      LAYER M4 ;
        RECT 0.000 128.064 0.192 128.088 ;
    END
  END ld_w[334]
  PIN ld_w[335]
    DIRECTION INPUT ;
    USE SIGNAL ;
    PORT
      LAYER M4 ;
        RECT 0.000 128.400 0.192 128.424 ;
    END
  END ld_w[335]
  PIN ld_w[336]
    DIRECTION INPUT ;
    USE SIGNAL ;
    PORT
      LAYER M4 ;
        RECT 0.000 128.784 0.192 128.808 ;
    END
  END ld_w[336]
  PIN ld_w[337]
    DIRECTION INPUT ;
    USE SIGNAL ;
    PORT
      LAYER M4 ;
        RECT 0.000 129.120 0.192 129.144 ;
    END
  END ld_w[337]
  PIN ld_w[338]
    DIRECTION INPUT ;
    USE SIGNAL ;
    PORT
      LAYER M4 ;
        RECT 0.000 129.504 0.192 129.528 ;
    END
  END ld_w[338]
  PIN ld_w[339]
    DIRECTION INPUT ;
    USE SIGNAL ;
    PORT
      LAYER M4 ;
        RECT 0.000 129.840 0.192 129.864 ;
    END
  END ld_w[339]
  PIN ld_w[340]
    DIRECTION INPUT ;
    USE SIGNAL ;
    PORT
      LAYER M4 ;
        RECT 0.000 130.176 0.192 130.200 ;
    END
  END ld_w[340]
  PIN ld_w[341]
    DIRECTION INPUT ;
    USE SIGNAL ;
    PORT
      LAYER M4 ;
        RECT 0.000 130.560 0.192 130.584 ;
    END
  END ld_w[341]
  PIN ld_w[342]
    DIRECTION INPUT ;
    USE SIGNAL ;
    PORT
      LAYER M4 ;
        RECT 0.000 130.896 0.192 130.920 ;
    END
  END ld_w[342]
  PIN ld_w[343]
    DIRECTION INPUT ;
    USE SIGNAL ;
    PORT
      LAYER M4 ;
        RECT 0.000 131.280 0.192 131.304 ;
    END
  END ld_w[343]
  PIN ld_w[344]
    DIRECTION INPUT ;
    USE SIGNAL ;
    PORT
      LAYER M4 ;
        RECT 0.000 131.616 0.192 131.640 ;
    END
  END ld_w[344]
  PIN ld_w[345]
    DIRECTION INPUT ;
    USE SIGNAL ;
    PORT
      LAYER M4 ;
        RECT 0.000 131.952 0.192 131.976 ;
    END
  END ld_w[345]
  PIN ld_w[346]
    DIRECTION INPUT ;
    USE SIGNAL ;
    PORT
      LAYER M4 ;
        RECT 0.000 132.336 0.192 132.360 ;
    END
  END ld_w[346]
  PIN ld_w[347]
    DIRECTION INPUT ;
    USE SIGNAL ;
    PORT
      LAYER M4 ;
        RECT 0.000 132.672 0.192 132.696 ;
    END
  END ld_w[347]
  PIN ld_w[348]
    DIRECTION INPUT ;
    USE SIGNAL ;
    PORT
      LAYER M4 ;
        RECT 0.000 133.056 0.192 133.080 ;
    END
  END ld_w[348]
  PIN ld_w[349]
    DIRECTION INPUT ;
    USE SIGNAL ;
    PORT
      LAYER M4 ;
        RECT 0.000 133.392 0.192 133.416 ;
    END
  END ld_w[349]
  PIN ld_w[350]
    DIRECTION INPUT ;
    USE SIGNAL ;
    PORT
      LAYER M4 ;
        RECT 0.000 133.728 0.192 133.752 ;
    END
  END ld_w[350]
  PIN ld_w[351]
    DIRECTION INPUT ;
    USE SIGNAL ;
    PORT
      LAYER M4 ;
        RECT 0.000 134.112 0.192 134.136 ;
    END
  END ld_w[351]
  PIN ld_w[352]
    DIRECTION INPUT ;
    USE SIGNAL ;
    PORT
      LAYER M4 ;
        RECT 0.000 134.448 0.192 134.472 ;
    END
  END ld_w[352]
  PIN ld_w[353]
    DIRECTION INPUT ;
    USE SIGNAL ;
    PORT
      LAYER M4 ;
        RECT 0.000 134.832 0.192 134.856 ;
    END
  END ld_w[353]
  PIN ld_w[354]
    DIRECTION INPUT ;
    USE SIGNAL ;
    PORT
      LAYER M4 ;
        RECT 0.000 135.168 0.192 135.192 ;
    END
  END ld_w[354]
  PIN ld_w[355]
    DIRECTION INPUT ;
    USE SIGNAL ;
    PORT
      LAYER M4 ;
        RECT 0.000 135.504 0.192 135.528 ;
    END
  END ld_w[355]
  PIN ld_w[356]
    DIRECTION INPUT ;
    USE SIGNAL ;
    PORT
      LAYER M4 ;
        RECT 0.000 135.888 0.192 135.912 ;
    END
  END ld_w[356]
  PIN ld_w[357]
    DIRECTION INPUT ;
    USE SIGNAL ;
    PORT
      LAYER M4 ;
        RECT 0.000 136.224 0.192 136.248 ;
    END
  END ld_w[357]
  PIN ld_w[358]
    DIRECTION INPUT ;
    USE SIGNAL ;
    PORT
      LAYER M4 ;
        RECT 0.000 136.608 0.192 136.632 ;
    END
  END ld_w[358]
  PIN ld_w[359]
    DIRECTION INPUT ;
    USE SIGNAL ;
    PORT
      LAYER M4 ;
        RECT 0.000 136.944 0.192 136.968 ;
    END
  END ld_w[359]
  PIN ld_w[360]
    DIRECTION INPUT ;
    USE SIGNAL ;
    PORT
      LAYER M4 ;
        RECT 0.000 137.280 0.192 137.304 ;
    END
  END ld_w[360]
  PIN ld_w[361]
    DIRECTION INPUT ;
    USE SIGNAL ;
    PORT
      LAYER M4 ;
        RECT 0.000 137.664 0.192 137.688 ;
    END
  END ld_w[361]
  PIN ld_w[362]
    DIRECTION INPUT ;
    USE SIGNAL ;
    PORT
      LAYER M4 ;
        RECT 0.000 138.000 0.192 138.024 ;
    END
  END ld_w[362]
  PIN ld_w[363]
    DIRECTION INPUT ;
    USE SIGNAL ;
    PORT
      LAYER M4 ;
        RECT 0.000 138.384 0.192 138.408 ;
    END
  END ld_w[363]
  PIN ld_w[364]
    DIRECTION INPUT ;
    USE SIGNAL ;
    PORT
      LAYER M4 ;
        RECT 0.000 138.720 0.192 138.744 ;
    END
  END ld_w[364]
  PIN ld_w[365]
    DIRECTION INPUT ;
    USE SIGNAL ;
    PORT
      LAYER M4 ;
        RECT 0.000 139.056 0.192 139.080 ;
    END
  END ld_w[365]
  PIN ld_w[366]
    DIRECTION INPUT ;
    USE SIGNAL ;
    PORT
      LAYER M4 ;
        RECT 0.000 139.440 0.192 139.464 ;
    END
  END ld_w[366]
  PIN ld_w[367]
    DIRECTION INPUT ;
    USE SIGNAL ;
    PORT
      LAYER M4 ;
        RECT 0.000 139.776 0.192 139.800 ;
    END
  END ld_w[367]
  PIN ld_w[368]
    DIRECTION INPUT ;
    USE SIGNAL ;
    PORT
      LAYER M4 ;
        RECT 0.000 140.160 0.192 140.184 ;
    END
  END ld_w[368]
  PIN ld_w[369]
    DIRECTION INPUT ;
    USE SIGNAL ;
    PORT
      LAYER M4 ;
        RECT 0.000 140.496 0.192 140.520 ;
    END
  END ld_w[369]
  PIN ld_w[370]
    DIRECTION INPUT ;
    USE SIGNAL ;
    PORT
      LAYER M4 ;
        RECT 0.000 140.832 0.192 140.856 ;
    END
  END ld_w[370]
  PIN ld_w[371]
    DIRECTION INPUT ;
    USE SIGNAL ;
    PORT
      LAYER M4 ;
        RECT 0.000 141.216 0.192 141.240 ;
    END
  END ld_w[371]
  PIN ld_w[372]
    DIRECTION INPUT ;
    USE SIGNAL ;
    PORT
      LAYER M4 ;
        RECT 0.000 141.552 0.192 141.576 ;
    END
  END ld_w[372]
  PIN ld_w[373]
    DIRECTION INPUT ;
    USE SIGNAL ;
    PORT
      LAYER M4 ;
        RECT 0.000 141.936 0.192 141.960 ;
    END
  END ld_w[373]
  PIN ld_w[374]
    DIRECTION INPUT ;
    USE SIGNAL ;
    PORT
      LAYER M4 ;
        RECT 0.000 142.272 0.192 142.296 ;
    END
  END ld_w[374]
  PIN ld_w[375]
    DIRECTION INPUT ;
    USE SIGNAL ;
    PORT
      LAYER M4 ;
        RECT 0.000 142.608 0.192 142.632 ;
    END
  END ld_w[375]
  PIN ld_w[376]
    DIRECTION INPUT ;
    USE SIGNAL ;
    PORT
      LAYER M4 ;
        RECT 0.000 142.992 0.192 143.016 ;
    END
  END ld_w[376]
  PIN ld_w[377]
    DIRECTION INPUT ;
    USE SIGNAL ;
    PORT
      LAYER M4 ;
        RECT 0.000 143.328 0.192 143.352 ;
    END
  END ld_w[377]
  PIN ld_w[378]
    DIRECTION INPUT ;
    USE SIGNAL ;
    PORT
      LAYER M4 ;
        RECT 0.000 143.712 0.192 143.736 ;
    END
  END ld_w[378]
  PIN ld_w[379]
    DIRECTION INPUT ;
    USE SIGNAL ;
    PORT
      LAYER M4 ;
        RECT 0.000 144.048 0.192 144.072 ;
    END
  END ld_w[379]
  PIN ld_w[380]
    DIRECTION INPUT ;
    USE SIGNAL ;
    PORT
      LAYER M4 ;
        RECT 0.000 144.384 0.192 144.408 ;
    END
  END ld_w[380]
  PIN ld_w[381]
    DIRECTION INPUT ;
    USE SIGNAL ;
    PORT
      LAYER M4 ;
        RECT 0.000 144.768 0.192 144.792 ;
    END
  END ld_w[381]
  PIN ld_w[382]
    DIRECTION INPUT ;
    USE SIGNAL ;
    PORT
      LAYER M4 ;
        RECT 0.000 145.104 0.192 145.128 ;
    END
  END ld_w[382]
  PIN ld_w[383]
    DIRECTION INPUT ;
    USE SIGNAL ;
    PORT
      LAYER M4 ;
        RECT 0.000 145.488 0.192 145.512 ;
    END
  END ld_w[383]
  PIN ld_w[384]
    DIRECTION INPUT ;
    USE SIGNAL ;
    PORT
      LAYER M4 ;
        RECT 0.000 145.824 0.192 145.848 ;
    END
  END ld_w[384]
  PIN ld_w[385]
    DIRECTION INPUT ;
    USE SIGNAL ;
    PORT
      LAYER M4 ;
        RECT 0.000 146.160 0.192 146.184 ;
    END
  END ld_w[385]
  PIN ld_w[386]
    DIRECTION INPUT ;
    USE SIGNAL ;
    PORT
      LAYER M4 ;
        RECT 0.000 146.544 0.192 146.568 ;
    END
  END ld_w[386]
  PIN ld_w[387]
    DIRECTION INPUT ;
    USE SIGNAL ;
    PORT
      LAYER M4 ;
        RECT 0.000 146.880 0.192 146.904 ;
    END
  END ld_w[387]
  PIN ld_w[388]
    DIRECTION INPUT ;
    USE SIGNAL ;
    PORT
      LAYER M4 ;
        RECT 0.000 147.264 0.192 147.288 ;
    END
  END ld_w[388]
  PIN ld_w[389]
    DIRECTION INPUT ;
    USE SIGNAL ;
    PORT
      LAYER M4 ;
        RECT 0.000 147.600 0.192 147.624 ;
    END
  END ld_w[389]
  PIN ld_w[390]
    DIRECTION INPUT ;
    USE SIGNAL ;
    PORT
      LAYER M4 ;
        RECT 0.000 147.936 0.192 147.960 ;
    END
  END ld_w[390]
  PIN ld_w[391]
    DIRECTION INPUT ;
    USE SIGNAL ;
    PORT
      LAYER M4 ;
        RECT 0.000 148.320 0.192 148.344 ;
    END
  END ld_w[391]
  PIN ld_w[392]
    DIRECTION INPUT ;
    USE SIGNAL ;
    PORT
      LAYER M4 ;
        RECT 0.000 148.656 0.192 148.680 ;
    END
  END ld_w[392]
  PIN ld_w[393]
    DIRECTION INPUT ;
    USE SIGNAL ;
    PORT
      LAYER M4 ;
        RECT 0.000 149.040 0.192 149.064 ;
    END
  END ld_w[393]
  PIN ld_w[394]
    DIRECTION INPUT ;
    USE SIGNAL ;
    PORT
      LAYER M4 ;
        RECT 0.000 149.376 0.192 149.400 ;
    END
  END ld_w[394]
  PIN ld_w[395]
    DIRECTION INPUT ;
    USE SIGNAL ;
    PORT
      LAYER M4 ;
        RECT 0.000 149.712 0.192 149.736 ;
    END
  END ld_w[395]
  PIN ld_w[396]
    DIRECTION INPUT ;
    USE SIGNAL ;
    PORT
      LAYER M4 ;
        RECT 0.000 150.096 0.192 150.120 ;
    END
  END ld_w[396]
  PIN ld_w[397]
    DIRECTION INPUT ;
    USE SIGNAL ;
    PORT
      LAYER M4 ;
        RECT 0.000 150.432 0.192 150.456 ;
    END
  END ld_w[397]
  PIN ld_w[398]
    DIRECTION INPUT ;
    USE SIGNAL ;
    PORT
      LAYER M4 ;
        RECT 0.000 150.816 0.192 150.840 ;
    END
  END ld_w[398]
  PIN ld_w[399]
    DIRECTION INPUT ;
    USE SIGNAL ;
    PORT
      LAYER M4 ;
        RECT 0.000 151.152 0.192 151.176 ;
    END
  END ld_w[399]
  PIN ld_w[400]
    DIRECTION INPUT ;
    USE SIGNAL ;
    PORT
      LAYER M4 ;
        RECT 0.000 151.488 0.192 151.512 ;
    END
  END ld_w[400]
  PIN ld_w[401]
    DIRECTION INPUT ;
    USE SIGNAL ;
    PORT
      LAYER M4 ;
        RECT 0.000 151.872 0.192 151.896 ;
    END
  END ld_w[401]
  PIN ld_w[402]
    DIRECTION INPUT ;
    USE SIGNAL ;
    PORT
      LAYER M4 ;
        RECT 0.000 152.208 0.192 152.232 ;
    END
  END ld_w[402]
  PIN ld_w[403]
    DIRECTION INPUT ;
    USE SIGNAL ;
    PORT
      LAYER M4 ;
        RECT 0.000 152.592 0.192 152.616 ;
    END
  END ld_w[403]
  PIN ld_w[404]
    DIRECTION INPUT ;
    USE SIGNAL ;
    PORT
      LAYER M4 ;
        RECT 0.000 152.928 0.192 152.952 ;
    END
  END ld_w[404]
  PIN ld_w[405]
    DIRECTION INPUT ;
    USE SIGNAL ;
    PORT
      LAYER M4 ;
        RECT 0.000 153.264 0.192 153.288 ;
    END
  END ld_w[405]
  PIN ld_w[406]
    DIRECTION INPUT ;
    USE SIGNAL ;
    PORT
      LAYER M4 ;
        RECT 0.000 153.648 0.192 153.672 ;
    END
  END ld_w[406]
  PIN ld_w[407]
    DIRECTION INPUT ;
    USE SIGNAL ;
    PORT
      LAYER M4 ;
        RECT 0.000 153.984 0.192 154.008 ;
    END
  END ld_w[407]
  PIN ld_w[408]
    DIRECTION INPUT ;
    USE SIGNAL ;
    PORT
      LAYER M4 ;
        RECT 0.000 154.368 0.192 154.392 ;
    END
  END ld_w[408]
  PIN ld_w[409]
    DIRECTION INPUT ;
    USE SIGNAL ;
    PORT
      LAYER M4 ;
        RECT 0.000 154.704 0.192 154.728 ;
    END
  END ld_w[409]
  PIN ld_w[410]
    DIRECTION INPUT ;
    USE SIGNAL ;
    PORT
      LAYER M4 ;
        RECT 0.000 155.040 0.192 155.064 ;
    END
  END ld_w[410]
  PIN ld_w[411]
    DIRECTION INPUT ;
    USE SIGNAL ;
    PORT
      LAYER M4 ;
        RECT 0.000 155.424 0.192 155.448 ;
    END
  END ld_w[411]
  PIN ld_w[412]
    DIRECTION INPUT ;
    USE SIGNAL ;
    PORT
      LAYER M4 ;
        RECT 0.000 155.760 0.192 155.784 ;
    END
  END ld_w[412]
  PIN ld_w[413]
    DIRECTION INPUT ;
    USE SIGNAL ;
    PORT
      LAYER M4 ;
        RECT 0.000 156.144 0.192 156.168 ;
    END
  END ld_w[413]
  PIN ld_w[414]
    DIRECTION INPUT ;
    USE SIGNAL ;
    PORT
      LAYER M4 ;
        RECT 0.000 156.480 0.192 156.504 ;
    END
  END ld_w[414]
  PIN ld_w[415]
    DIRECTION INPUT ;
    USE SIGNAL ;
    PORT
      LAYER M4 ;
        RECT 0.000 156.816 0.192 156.840 ;
    END
  END ld_w[415]
  PIN ld_w[416]
    DIRECTION INPUT ;
    USE SIGNAL ;
    PORT
      LAYER M4 ;
        RECT 0.000 157.200 0.192 157.224 ;
    END
  END ld_w[416]
  PIN ld_w[417]
    DIRECTION INPUT ;
    USE SIGNAL ;
    PORT
      LAYER M4 ;
        RECT 0.000 157.536 0.192 157.560 ;
    END
  END ld_w[417]
  PIN ld_w[418]
    DIRECTION INPUT ;
    USE SIGNAL ;
    PORT
      LAYER M4 ;
        RECT 0.000 157.920 0.192 157.944 ;
    END
  END ld_w[418]
  PIN ld_w[419]
    DIRECTION INPUT ;
    USE SIGNAL ;
    PORT
      LAYER M4 ;
        RECT 0.000 158.256 0.192 158.280 ;
    END
  END ld_w[419]
  PIN ld_w[420]
    DIRECTION INPUT ;
    USE SIGNAL ;
    PORT
      LAYER M4 ;
        RECT 0.000 158.592 0.192 158.616 ;
    END
  END ld_w[420]
  PIN ld_w[421]
    DIRECTION INPUT ;
    USE SIGNAL ;
    PORT
      LAYER M4 ;
        RECT 0.000 158.976 0.192 159.000 ;
    END
  END ld_w[421]
  PIN ld_w[422]
    DIRECTION INPUT ;
    USE SIGNAL ;
    PORT
      LAYER M4 ;
        RECT 0.000 159.312 0.192 159.336 ;
    END
  END ld_w[422]
  PIN ld_w[423]
    DIRECTION INPUT ;
    USE SIGNAL ;
    PORT
      LAYER M4 ;
        RECT 0.000 159.696 0.192 159.720 ;
    END
  END ld_w[423]
  PIN ld_w[424]
    DIRECTION INPUT ;
    USE SIGNAL ;
    PORT
      LAYER M4 ;
        RECT 0.000 160.032 0.192 160.056 ;
    END
  END ld_w[424]
  PIN ld_w[425]
    DIRECTION INPUT ;
    USE SIGNAL ;
    PORT
      LAYER M4 ;
        RECT 0.000 160.368 0.192 160.392 ;
    END
  END ld_w[425]
  PIN ld_w[426]
    DIRECTION INPUT ;
    USE SIGNAL ;
    PORT
      LAYER M4 ;
        RECT 0.000 160.752 0.192 160.776 ;
    END
  END ld_w[426]
  PIN ld_w[427]
    DIRECTION INPUT ;
    USE SIGNAL ;
    PORT
      LAYER M4 ;
        RECT 0.000 161.088 0.192 161.112 ;
    END
  END ld_w[427]
  PIN ld_w[428]
    DIRECTION INPUT ;
    USE SIGNAL ;
    PORT
      LAYER M4 ;
        RECT 0.000 161.472 0.192 161.496 ;
    END
  END ld_w[428]
  PIN ld_w[429]
    DIRECTION INPUT ;
    USE SIGNAL ;
    PORT
      LAYER M4 ;
        RECT 0.000 161.808 0.192 161.832 ;
    END
  END ld_w[429]
  PIN ld_w[430]
    DIRECTION INPUT ;
    USE SIGNAL ;
    PORT
      LAYER M4 ;
        RECT 0.000 162.144 0.192 162.168 ;
    END
  END ld_w[430]
  PIN ld_w[431]
    DIRECTION INPUT ;
    USE SIGNAL ;
    PORT
      LAYER M4 ;
        RECT 0.000 162.528 0.192 162.552 ;
    END
  END ld_w[431]
  PIN ld_w[432]
    DIRECTION INPUT ;
    USE SIGNAL ;
    PORT
      LAYER M4 ;
        RECT 0.000 162.864 0.192 162.888 ;
    END
  END ld_w[432]
  PIN ld_w[433]
    DIRECTION INPUT ;
    USE SIGNAL ;
    PORT
      LAYER M4 ;
        RECT 0.000 163.200 0.192 163.224 ;
    END
  END ld_w[433]
  PIN ld_w[434]
    DIRECTION INPUT ;
    USE SIGNAL ;
    PORT
      LAYER M4 ;
        RECT 0.000 163.584 0.192 163.608 ;
    END
  END ld_w[434]
  PIN ld_w[435]
    DIRECTION INPUT ;
    USE SIGNAL ;
    PORT
      LAYER M4 ;
        RECT 0.000 163.920 0.192 163.944 ;
    END
  END ld_w[435]
  PIN ld_w[436]
    DIRECTION INPUT ;
    USE SIGNAL ;
    PORT
      LAYER M4 ;
        RECT 0.000 164.304 0.192 164.328 ;
    END
  END ld_w[436]
  PIN ld_w[437]
    DIRECTION INPUT ;
    USE SIGNAL ;
    PORT
      LAYER M4 ;
        RECT 0.000 164.640 0.192 164.664 ;
    END
  END ld_w[437]
  PIN ld_w[438]
    DIRECTION INPUT ;
    USE SIGNAL ;
    PORT
      LAYER M4 ;
        RECT 0.000 164.976 0.192 165.000 ;
    END
  END ld_w[438]
  PIN ld_w[439]
    DIRECTION INPUT ;
    USE SIGNAL ;
    PORT
      LAYER M4 ;
        RECT 0.000 165.360 0.192 165.384 ;
    END
  END ld_w[439]
  PIN ld_w[440]
    DIRECTION INPUT ;
    USE SIGNAL ;
    PORT
      LAYER M4 ;
        RECT 0.000 165.696 0.192 165.720 ;
    END
  END ld_w[440]
  PIN ld_w[441]
    DIRECTION INPUT ;
    USE SIGNAL ;
    PORT
      LAYER M4 ;
        RECT 0.000 166.080 0.192 166.104 ;
    END
  END ld_w[441]
  PIN ld_w[442]
    DIRECTION INPUT ;
    USE SIGNAL ;
    PORT
      LAYER M4 ;
        RECT 0.000 166.416 0.192 166.440 ;
    END
  END ld_w[442]
  PIN ld_w[443]
    DIRECTION INPUT ;
    USE SIGNAL ;
    PORT
      LAYER M4 ;
        RECT 0.000 166.752 0.192 166.776 ;
    END
  END ld_w[443]
  PIN ld_w[444]
    DIRECTION INPUT ;
    USE SIGNAL ;
    PORT
      LAYER M4 ;
        RECT 0.000 167.136 0.192 167.160 ;
    END
  END ld_w[444]
  PIN ld_w[445]
    DIRECTION INPUT ;
    USE SIGNAL ;
    PORT
      LAYER M4 ;
        RECT 0.000 167.472 0.192 167.496 ;
    END
  END ld_w[445]
  PIN ld_w[446]
    DIRECTION INPUT ;
    USE SIGNAL ;
    PORT
      LAYER M4 ;
        RECT 0.000 167.856 0.192 167.880 ;
    END
  END ld_w[446]
  PIN ld_w[447]
    DIRECTION INPUT ;
    USE SIGNAL ;
    PORT
      LAYER M4 ;
        RECT 0.000 168.192 0.192 168.216 ;
    END
  END ld_w[447]
  PIN ld_w[448]
    DIRECTION INPUT ;
    USE SIGNAL ;
    PORT
      LAYER M4 ;
        RECT 0.000 168.528 0.192 168.552 ;
    END
  END ld_w[448]
  PIN ld_w[449]
    DIRECTION INPUT ;
    USE SIGNAL ;
    PORT
      LAYER M4 ;
        RECT 0.000 168.912 0.192 168.936 ;
    END
  END ld_w[449]
  PIN ld_w[450]
    DIRECTION INPUT ;
    USE SIGNAL ;
    PORT
      LAYER M4 ;
        RECT 0.000 169.248 0.192 169.272 ;
    END
  END ld_w[450]
  PIN ld_w[451]
    DIRECTION INPUT ;
    USE SIGNAL ;
    PORT
      LAYER M4 ;
        RECT 0.000 169.632 0.192 169.656 ;
    END
  END ld_w[451]
  PIN ld_w[452]
    DIRECTION INPUT ;
    USE SIGNAL ;
    PORT
      LAYER M4 ;
        RECT 0.000 169.968 0.192 169.992 ;
    END
  END ld_w[452]
  PIN ld_w[453]
    DIRECTION INPUT ;
    USE SIGNAL ;
    PORT
      LAYER M4 ;
        RECT 0.000 170.304 0.192 170.328 ;
    END
  END ld_w[453]
  PIN ld_w[454]
    DIRECTION INPUT ;
    USE SIGNAL ;
    PORT
      LAYER M4 ;
        RECT 0.000 170.688 0.192 170.712 ;
    END
  END ld_w[454]
  PIN ld_w[455]
    DIRECTION INPUT ;
    USE SIGNAL ;
    PORT
      LAYER M4 ;
        RECT 0.000 171.024 0.192 171.048 ;
    END
  END ld_w[455]
  PIN ld_w[456]
    DIRECTION INPUT ;
    USE SIGNAL ;
    PORT
      LAYER M4 ;
        RECT 0.000 171.408 0.192 171.432 ;
    END
  END ld_w[456]
  PIN ld_w[457]
    DIRECTION INPUT ;
    USE SIGNAL ;
    PORT
      LAYER M4 ;
        RECT 0.000 171.744 0.192 171.768 ;
    END
  END ld_w[457]
  PIN ld_w[458]
    DIRECTION INPUT ;
    USE SIGNAL ;
    PORT
      LAYER M4 ;
        RECT 0.000 172.080 0.192 172.104 ;
    END
  END ld_w[458]
  PIN ld_w[459]
    DIRECTION INPUT ;
    USE SIGNAL ;
    PORT
      LAYER M4 ;
        RECT 0.000 172.464 0.192 172.488 ;
    END
  END ld_w[459]
  PIN ld_w[460]
    DIRECTION INPUT ;
    USE SIGNAL ;
    PORT
      LAYER M4 ;
        RECT 0.000 172.800 0.192 172.824 ;
    END
  END ld_w[460]
  PIN ld_w[461]
    DIRECTION INPUT ;
    USE SIGNAL ;
    PORT
      LAYER M4 ;
        RECT 0.000 173.184 0.192 173.208 ;
    END
  END ld_w[461]
  PIN ld_w[462]
    DIRECTION INPUT ;
    USE SIGNAL ;
    PORT
      LAYER M4 ;
        RECT 0.000 173.520 0.192 173.544 ;
    END
  END ld_w[462]
  PIN ld_w[463]
    DIRECTION INPUT ;
    USE SIGNAL ;
    PORT
      LAYER M4 ;
        RECT 0.000 173.856 0.192 173.880 ;
    END
  END ld_w[463]
  PIN ld_w[464]
    DIRECTION INPUT ;
    USE SIGNAL ;
    PORT
      LAYER M4 ;
        RECT 0.000 174.240 0.192 174.264 ;
    END
  END ld_w[464]
  PIN ld_w[465]
    DIRECTION INPUT ;
    USE SIGNAL ;
    PORT
      LAYER M4 ;
        RECT 0.000 174.576 0.192 174.600 ;
    END
  END ld_w[465]
  PIN ld_w[466]
    DIRECTION INPUT ;
    USE SIGNAL ;
    PORT
      LAYER M4 ;
        RECT 0.000 174.960 0.192 174.984 ;
    END
  END ld_w[466]
  PIN ld_w[467]
    DIRECTION INPUT ;
    USE SIGNAL ;
    PORT
      LAYER M4 ;
        RECT 0.000 175.296 0.192 175.320 ;
    END
  END ld_w[467]
  PIN ld_w[468]
    DIRECTION INPUT ;
    USE SIGNAL ;
    PORT
      LAYER M4 ;
        RECT 0.000 175.632 0.192 175.656 ;
    END
  END ld_w[468]
  PIN ld_w[469]
    DIRECTION INPUT ;
    USE SIGNAL ;
    PORT
      LAYER M4 ;
        RECT 0.000 176.016 0.192 176.040 ;
    END
  END ld_w[469]
  PIN ld_w[470]
    DIRECTION INPUT ;
    USE SIGNAL ;
    PORT
      LAYER M4 ;
        RECT 0.000 176.352 0.192 176.376 ;
    END
  END ld_w[470]
  PIN ld_w[471]
    DIRECTION INPUT ;
    USE SIGNAL ;
    PORT
      LAYER M4 ;
        RECT 0.000 176.736 0.192 176.760 ;
    END
  END ld_w[471]
  PIN ld_w[472]
    DIRECTION INPUT ;
    USE SIGNAL ;
    PORT
      LAYER M4 ;
        RECT 0.000 177.072 0.192 177.096 ;
    END
  END ld_w[472]
  PIN ld_w[473]
    DIRECTION INPUT ;
    USE SIGNAL ;
    PORT
      LAYER M4 ;
        RECT 0.000 177.408 0.192 177.432 ;
    END
  END ld_w[473]
  PIN ld_w[474]
    DIRECTION INPUT ;
    USE SIGNAL ;
    PORT
      LAYER M4 ;
        RECT 0.000 177.792 0.192 177.816 ;
    END
  END ld_w[474]
  PIN ld_w[475]
    DIRECTION INPUT ;
    USE SIGNAL ;
    PORT
      LAYER M4 ;
        RECT 0.000 178.128 0.192 178.152 ;
    END
  END ld_w[475]
  PIN ld_w[476]
    DIRECTION INPUT ;
    USE SIGNAL ;
    PORT
      LAYER M4 ;
        RECT 0.000 178.512 0.192 178.536 ;
    END
  END ld_w[476]
  PIN ld_w[477]
    DIRECTION INPUT ;
    USE SIGNAL ;
    PORT
      LAYER M4 ;
        RECT 0.000 178.848 0.192 178.872 ;
    END
  END ld_w[477]
  PIN ld_w[478]
    DIRECTION INPUT ;
    USE SIGNAL ;
    PORT
      LAYER M4 ;
        RECT 0.000 179.184 0.192 179.208 ;
    END
  END ld_w[478]
  PIN ld_w[479]
    DIRECTION INPUT ;
    USE SIGNAL ;
    PORT
      LAYER M4 ;
        RECT 0.000 179.568 0.192 179.592 ;
    END
  END ld_w[479]
  PIN ld_w[480]
    DIRECTION INPUT ;
    USE SIGNAL ;
    PORT
      LAYER M4 ;
        RECT 0.000 179.904 0.192 179.928 ;
    END
  END ld_w[480]
  PIN ld_w[481]
    DIRECTION INPUT ;
    USE SIGNAL ;
    PORT
      LAYER M4 ;
        RECT 0.000 180.288 0.192 180.312 ;
    END
  END ld_w[481]
  PIN ld_w[482]
    DIRECTION INPUT ;
    USE SIGNAL ;
    PORT
      LAYER M4 ;
        RECT 0.000 180.624 0.192 180.648 ;
    END
  END ld_w[482]
  PIN ld_w[483]
    DIRECTION INPUT ;
    USE SIGNAL ;
    PORT
      LAYER M4 ;
        RECT 0.000 180.960 0.192 180.984 ;
    END
  END ld_w[483]
  PIN ld_w[484]
    DIRECTION INPUT ;
    USE SIGNAL ;
    PORT
      LAYER M4 ;
        RECT 0.000 181.344 0.192 181.368 ;
    END
  END ld_w[484]
  PIN ld_w[485]
    DIRECTION INPUT ;
    USE SIGNAL ;
    PORT
      LAYER M4 ;
        RECT 0.000 181.680 0.192 181.704 ;
    END
  END ld_w[485]
  PIN ld_w[486]
    DIRECTION INPUT ;
    USE SIGNAL ;
    PORT
      LAYER M4 ;
        RECT 0.000 182.064 0.192 182.088 ;
    END
  END ld_w[486]
  PIN ld_w[487]
    DIRECTION INPUT ;
    USE SIGNAL ;
    PORT
      LAYER M4 ;
        RECT 0.000 182.400 0.192 182.424 ;
    END
  END ld_w[487]
  PIN ld_w[488]
    DIRECTION INPUT ;
    USE SIGNAL ;
    PORT
      LAYER M4 ;
        RECT 0.000 182.736 0.192 182.760 ;
    END
  END ld_w[488]
  PIN ld_w[489]
    DIRECTION INPUT ;
    USE SIGNAL ;
    PORT
      LAYER M4 ;
        RECT 0.000 183.120 0.192 183.144 ;
    END
  END ld_w[489]
  PIN ld_w[490]
    DIRECTION INPUT ;
    USE SIGNAL ;
    PORT
      LAYER M4 ;
        RECT 0.000 183.456 0.192 183.480 ;
    END
  END ld_w[490]
  PIN ld_w[491]
    DIRECTION INPUT ;
    USE SIGNAL ;
    PORT
      LAYER M4 ;
        RECT 0.000 183.840 0.192 183.864 ;
    END
  END ld_w[491]
  PIN ld_w[492]
    DIRECTION INPUT ;
    USE SIGNAL ;
    PORT
      LAYER M4 ;
        RECT 0.000 184.176 0.192 184.200 ;
    END
  END ld_w[492]
  PIN ld_w[493]
    DIRECTION INPUT ;
    USE SIGNAL ;
    PORT
      LAYER M4 ;
        RECT 0.000 184.512 0.192 184.536 ;
    END
  END ld_w[493]
  PIN ld_w[494]
    DIRECTION INPUT ;
    USE SIGNAL ;
    PORT
      LAYER M4 ;
        RECT 0.000 184.896 0.192 184.920 ;
    END
  END ld_w[494]
  PIN ld_w[495]
    DIRECTION INPUT ;
    USE SIGNAL ;
    PORT
      LAYER M4 ;
        RECT 0.000 185.232 0.192 185.256 ;
    END
  END ld_w[495]
  PIN ld_w[496]
    DIRECTION INPUT ;
    USE SIGNAL ;
    PORT
      LAYER M4 ;
        RECT 0.000 185.616 0.192 185.640 ;
    END
  END ld_w[496]
  PIN ld_w[497]
    DIRECTION INPUT ;
    USE SIGNAL ;
    PORT
      LAYER M4 ;
        RECT 0.000 185.952 0.192 185.976 ;
    END
  END ld_w[497]
  PIN ld_w[498]
    DIRECTION INPUT ;
    USE SIGNAL ;
    PORT
      LAYER M4 ;
        RECT 0.000 186.288 0.192 186.312 ;
    END
  END ld_w[498]
  PIN ld_w[499]
    DIRECTION INPUT ;
    USE SIGNAL ;
    PORT
      LAYER M4 ;
        RECT 0.000 186.672 0.192 186.696 ;
    END
  END ld_w[499]
  PIN ld_w[500]
    DIRECTION INPUT ;
    USE SIGNAL ;
    PORT
      LAYER M4 ;
        RECT 0.000 187.008 0.192 187.032 ;
    END
  END ld_w[500]
  PIN ld_w[501]
    DIRECTION INPUT ;
    USE SIGNAL ;
    PORT
      LAYER M4 ;
        RECT 0.000 187.392 0.192 187.416 ;
    END
  END ld_w[501]
  PIN ld_w[502]
    DIRECTION INPUT ;
    USE SIGNAL ;
    PORT
      LAYER M4 ;
        RECT 0.000 187.728 0.192 187.752 ;
    END
  END ld_w[502]
  PIN ld_w[503]
    DIRECTION INPUT ;
    USE SIGNAL ;
    PORT
      LAYER M4 ;
        RECT 0.000 188.064 0.192 188.088 ;
    END
  END ld_w[503]
  PIN ld_w[504]
    DIRECTION INPUT ;
    USE SIGNAL ;
    PORT
      LAYER M4 ;
        RECT 0.000 188.448 0.192 188.472 ;
    END
  END ld_w[504]
  PIN ld_w[505]
    DIRECTION INPUT ;
    USE SIGNAL ;
    PORT
      LAYER M4 ;
        RECT 0.000 188.784 0.192 188.808 ;
    END
  END ld_w[505]
  PIN ld_w[506]
    DIRECTION INPUT ;
    USE SIGNAL ;
    PORT
      LAYER M4 ;
        RECT 0.000 189.168 0.192 189.192 ;
    END
  END ld_w[506]
  PIN ld_w[507]
    DIRECTION INPUT ;
    USE SIGNAL ;
    PORT
      LAYER M4 ;
        RECT 0.000 189.504 0.192 189.528 ;
    END
  END ld_w[507]
  PIN ld_w[508]
    DIRECTION INPUT ;
    USE SIGNAL ;
    PORT
      LAYER M4 ;
        RECT 0.000 189.840 0.192 189.864 ;
    END
  END ld_w[508]
  PIN ld_w[509]
    DIRECTION INPUT ;
    USE SIGNAL ;
    PORT
      LAYER M4 ;
        RECT 0.000 190.224 0.192 190.248 ;
    END
  END ld_w[509]
  PIN ld_w[510]
    DIRECTION INPUT ;
    USE SIGNAL ;
    PORT
      LAYER M4 ;
        RECT 0.000 190.560 0.192 190.584 ;
    END
  END ld_w[510]
  PIN ld_w[511]
    DIRECTION INPUT ;
    USE SIGNAL ;
    PORT
      LAYER M4 ;
        RECT 0.000 190.944 0.192 190.968 ;
    END
  END ld_w[511]
  PIN ld_wp[0]
    DIRECTION INPUT ;
    USE SIGNAL ;
    PORT
      LAYER M4 ;
        RECT 0.000 191.280 0.192 191.304 ;
    END
  END ld_wp[0]
  PIN ld_wp[1]
    DIRECTION INPUT ;
    USE SIGNAL ;
    PORT
      LAYER M4 ;
        RECT 0.000 191.616 0.192 191.640 ;
    END
  END ld_wp[1]
  PIN ld_wp[2]
    DIRECTION INPUT ;
    USE SIGNAL ;
    PORT
      LAYER M4 ;
        RECT 0.000 192.000 0.192 192.024 ;
    END
  END ld_wp[2]
  PIN ld_wp[3]
    DIRECTION INPUT ;
    USE SIGNAL ;
    PORT
      LAYER M4 ;
        RECT 0.000 192.336 0.192 192.360 ;
    END
  END ld_wp[3]
  PIN ld_wp[4]
    DIRECTION INPUT ;
    USE SIGNAL ;
    PORT
      LAYER M4 ;
        RECT 0.000 192.720 0.192 192.744 ;
    END
  END ld_wp[4]
  PIN ld_wp[5]
    DIRECTION INPUT ;
    USE SIGNAL ;
    PORT
      LAYER M4 ;
        RECT 0.000 193.056 0.192 193.080 ;
    END
  END ld_wp[5]
  PIN ld_wp[6]
    DIRECTION INPUT ;
    USE SIGNAL ;
    PORT
      LAYER M4 ;
        RECT 0.000 193.392 0.192 193.416 ;
    END
  END ld_wp[6]
  PIN ld_wp[7]
    DIRECTION INPUT ;
    USE SIGNAL ;
    PORT
      LAYER M4 ;
        RECT 0.000 193.776 0.192 193.800 ;
    END
  END ld_wp[7]
  PIN ld_wp[8]
    DIRECTION INPUT ;
    USE SIGNAL ;
    PORT
      LAYER M4 ;
        RECT 0.000 194.112 0.192 194.136 ;
    END
  END ld_wp[8]
  PIN ld_wp[9]
    DIRECTION INPUT ;
    USE SIGNAL ;
    PORT
      LAYER M4 ;
        RECT 0.000 194.496 0.192 194.520 ;
    END
  END ld_wp[9]
  PIN ld_wp[10]
    DIRECTION INPUT ;
    USE SIGNAL ;
    PORT
      LAYER M4 ;
        RECT 0.000 194.832 0.192 194.856 ;
    END
  END ld_wp[10]
  PIN ld_wp[11]
    DIRECTION INPUT ;
    USE SIGNAL ;
    PORT
      LAYER M4 ;
        RECT 0.000 195.168 0.192 195.192 ;
    END
  END ld_wp[11]
  PIN ld_wp[12]
    DIRECTION INPUT ;
    USE SIGNAL ;
    PORT
      LAYER M4 ;
        RECT 0.000 195.552 0.192 195.576 ;
    END
  END ld_wp[12]
  PIN ld_wp[13]
    DIRECTION INPUT ;
    USE SIGNAL ;
    PORT
      LAYER M4 ;
        RECT 0.000 195.888 0.192 195.912 ;
    END
  END ld_wp[13]
  PIN ld_wp[14]
    DIRECTION INPUT ;
    USE SIGNAL ;
    PORT
      LAYER M4 ;
        RECT 0.000 196.272 0.192 196.296 ;
    END
  END ld_wp[14]
  PIN ld_wp[15]
    DIRECTION INPUT ;
    USE SIGNAL ;
    PORT
      LAYER M4 ;
        RECT 0.000 196.608 0.192 196.632 ;
    END
  END ld_wp[15]
  PIN ld_wp[16]
    DIRECTION INPUT ;
    USE SIGNAL ;
    PORT
      LAYER M4 ;
        RECT 0.000 196.944 0.192 196.968 ;
    END
  END ld_wp[16]
  PIN ld_wp[17]
    DIRECTION INPUT ;
    USE SIGNAL ;
    PORT
      LAYER M4 ;
        RECT 0.000 197.328 0.192 197.352 ;
    END
  END ld_wp[17]
  PIN ld_wp[18]
    DIRECTION INPUT ;
    USE SIGNAL ;
    PORT
      LAYER M4 ;
        RECT 0.000 197.664 0.192 197.688 ;
    END
  END ld_wp[18]
  PIN ld_wp[19]
    DIRECTION INPUT ;
    USE SIGNAL ;
    PORT
      LAYER M4 ;
        RECT 0.000 198.048 0.192 198.072 ;
    END
  END ld_wp[19]
  PIN ld_wp[20]
    DIRECTION INPUT ;
    USE SIGNAL ;
    PORT
      LAYER M4 ;
        RECT 0.000 198.384 0.192 198.408 ;
    END
  END ld_wp[20]
  PIN ld_wp[21]
    DIRECTION INPUT ;
    USE SIGNAL ;
    PORT
      LAYER M4 ;
        RECT 0.000 198.720 0.192 198.744 ;
    END
  END ld_wp[21]
  PIN ld_wp[22]
    DIRECTION INPUT ;
    USE SIGNAL ;
    PORT
      LAYER M4 ;
        RECT 0.000 199.104 0.192 199.128 ;
    END
  END ld_wp[22]
  PIN ld_wp[23]
    DIRECTION INPUT ;
    USE SIGNAL ;
    PORT
      LAYER M4 ;
        RECT 0.000 199.440 0.192 199.464 ;
    END
  END ld_wp[23]
  PIN ld_wp[24]
    DIRECTION INPUT ;
    USE SIGNAL ;
    PORT
      LAYER M4 ;
        RECT 0.000 199.824 0.192 199.848 ;
    END
  END ld_wp[24]
  PIN ld_wp[25]
    DIRECTION INPUT ;
    USE SIGNAL ;
    PORT
      LAYER M4 ;
        RECT 0.000 200.160 0.192 200.184 ;
    END
  END ld_wp[25]
  PIN ld_wp[26]
    DIRECTION INPUT ;
    USE SIGNAL ;
    PORT
      LAYER M4 ;
        RECT 0.000 200.496 0.192 200.520 ;
    END
  END ld_wp[26]
  PIN ld_wp[27]
    DIRECTION INPUT ;
    USE SIGNAL ;
    PORT
      LAYER M4 ;
        RECT 0.000 200.880 0.192 200.904 ;
    END
  END ld_wp[27]
  PIN ld_wp[28]
    DIRECTION INPUT ;
    USE SIGNAL ;
    PORT
      LAYER M4 ;
        RECT 0.000 201.216 0.192 201.240 ;
    END
  END ld_wp[28]
  PIN ld_wp[29]
    DIRECTION INPUT ;
    USE SIGNAL ;
    PORT
      LAYER M4 ;
        RECT 0.000 201.600 0.192 201.624 ;
    END
  END ld_wp[29]
  PIN ld_wp[30]
    DIRECTION INPUT ;
    USE SIGNAL ;
    PORT
      LAYER M4 ;
        RECT 0.000 201.936 0.192 201.960 ;
    END
  END ld_wp[30]
  PIN ld_wp[31]
    DIRECTION INPUT ;
    USE SIGNAL ;
    PORT
      LAYER M4 ;
        RECT 0.000 202.272 0.192 202.296 ;
    END
  END ld_wp[31]
  PIN ld_wp[32]
    DIRECTION INPUT ;
    USE SIGNAL ;
    PORT
      LAYER M4 ;
        RECT 0.000 202.656 0.192 202.680 ;
    END
  END ld_wp[32]
  PIN ld_wp[33]
    DIRECTION INPUT ;
    USE SIGNAL ;
    PORT
      LAYER M4 ;
        RECT 0.000 202.992 0.192 203.016 ;
    END
  END ld_wp[33]
  PIN ld_wp[34]
    DIRECTION INPUT ;
    USE SIGNAL ;
    PORT
      LAYER M4 ;
        RECT 0.000 203.328 0.192 203.352 ;
    END
  END ld_wp[34]
  PIN ld_wp[35]
    DIRECTION INPUT ;
    USE SIGNAL ;
    PORT
      LAYER M4 ;
        RECT 0.000 203.712 0.192 203.736 ;
    END
  END ld_wp[35]
  PIN ld_wp[36]
    DIRECTION INPUT ;
    USE SIGNAL ;
    PORT
      LAYER M4 ;
        RECT 0.000 204.048 0.192 204.072 ;
    END
  END ld_wp[36]
  PIN ld_wp[37]
    DIRECTION INPUT ;
    USE SIGNAL ;
    PORT
      LAYER M4 ;
        RECT 0.000 204.432 0.192 204.456 ;
    END
  END ld_wp[37]
  PIN ld_wp[38]
    DIRECTION INPUT ;
    USE SIGNAL ;
    PORT
      LAYER M4 ;
        RECT 0.000 204.768 0.192 204.792 ;
    END
  END ld_wp[38]
  PIN ld_wp[39]
    DIRECTION INPUT ;
    USE SIGNAL ;
    PORT
      LAYER M4 ;
        RECT 0.000 205.104 0.192 205.128 ;
    END
  END ld_wp[39]
  PIN ld_wp[40]
    DIRECTION INPUT ;
    USE SIGNAL ;
    PORT
      LAYER M4 ;
        RECT 0.000 205.488 0.192 205.512 ;
    END
  END ld_wp[40]
  PIN ld_wp[41]
    DIRECTION INPUT ;
    USE SIGNAL ;
    PORT
      LAYER M4 ;
        RECT 0.000 205.824 0.192 205.848 ;
    END
  END ld_wp[41]
  PIN ld_wp[42]
    DIRECTION INPUT ;
    USE SIGNAL ;
    PORT
      LAYER M4 ;
        RECT 0.000 206.208 0.192 206.232 ;
    END
  END ld_wp[42]
  PIN ld_wp[43]
    DIRECTION INPUT ;
    USE SIGNAL ;
    PORT
      LAYER M4 ;
        RECT 0.000 206.544 0.192 206.568 ;
    END
  END ld_wp[43]
  PIN ld_wp[44]
    DIRECTION INPUT ;
    USE SIGNAL ;
    PORT
      LAYER M4 ;
        RECT 0.000 206.880 0.192 206.904 ;
    END
  END ld_wp[44]
  PIN ld_wp[45]
    DIRECTION INPUT ;
    USE SIGNAL ;
    PORT
      LAYER M4 ;
        RECT 0.000 207.264 0.192 207.288 ;
    END
  END ld_wp[45]
  PIN ld_wp[46]
    DIRECTION INPUT ;
    USE SIGNAL ;
    PORT
      LAYER M4 ;
        RECT 0.000 207.600 0.192 207.624 ;
    END
  END ld_wp[46]
  PIN ld_wp[47]
    DIRECTION INPUT ;
    USE SIGNAL ;
    PORT
      LAYER M4 ;
        RECT 0.000 207.984 0.192 208.008 ;
    END
  END ld_wp[47]
  PIN ld_wp[48]
    DIRECTION INPUT ;
    USE SIGNAL ;
    PORT
      LAYER M4 ;
        RECT 0.000 208.320 0.192 208.344 ;
    END
  END ld_wp[48]
  PIN ld_wp[49]
    DIRECTION INPUT ;
    USE SIGNAL ;
    PORT
      LAYER M4 ;
        RECT 0.000 208.656 0.192 208.680 ;
    END
  END ld_wp[49]
  PIN ld_wp[50]
    DIRECTION INPUT ;
    USE SIGNAL ;
    PORT
      LAYER M4 ;
        RECT 0.000 209.040 0.192 209.064 ;
    END
  END ld_wp[50]
  PIN ld_wp[51]
    DIRECTION INPUT ;
    USE SIGNAL ;
    PORT
      LAYER M4 ;
        RECT 0.000 209.376 0.192 209.400 ;
    END
  END ld_wp[51]
  PIN ld_wp[52]
    DIRECTION INPUT ;
    USE SIGNAL ;
    PORT
      LAYER M4 ;
        RECT 0.000 209.760 0.192 209.784 ;
    END
  END ld_wp[52]
  PIN ld_wp[53]
    DIRECTION INPUT ;
    USE SIGNAL ;
    PORT
      LAYER M4 ;
        RECT 0.000 210.096 0.192 210.120 ;
    END
  END ld_wp[53]
  PIN ld_wp[54]
    DIRECTION INPUT ;
    USE SIGNAL ;
    PORT
      LAYER M4 ;
        RECT 0.000 210.432 0.192 210.456 ;
    END
  END ld_wp[54]
  PIN ld_wp[55]
    DIRECTION INPUT ;
    USE SIGNAL ;
    PORT
      LAYER M4 ;
        RECT 0.000 210.816 0.192 210.840 ;
    END
  END ld_wp[55]
  PIN ld_wp[56]
    DIRECTION INPUT ;
    USE SIGNAL ;
    PORT
      LAYER M4 ;
        RECT 0.000 211.152 0.192 211.176 ;
    END
  END ld_wp[56]
  PIN ld_wp[57]
    DIRECTION INPUT ;
    USE SIGNAL ;
    PORT
      LAYER M4 ;
        RECT 0.000 211.536 0.192 211.560 ;
    END
  END ld_wp[57]
  PIN ld_wp[58]
    DIRECTION INPUT ;
    USE SIGNAL ;
    PORT
      LAYER M4 ;
        RECT 0.000 211.872 0.192 211.896 ;
    END
  END ld_wp[58]
  PIN ld_wp[59]
    DIRECTION INPUT ;
    USE SIGNAL ;
    PORT
      LAYER M4 ;
        RECT 0.000 212.208 0.192 212.232 ;
    END
  END ld_wp[59]
  PIN ld_wp[60]
    DIRECTION INPUT ;
    USE SIGNAL ;
    PORT
      LAYER M4 ;
        RECT 0.000 212.592 0.192 212.616 ;
    END
  END ld_wp[60]
  PIN ld_wp[61]
    DIRECTION INPUT ;
    USE SIGNAL ;
    PORT
      LAYER M4 ;
        RECT 0.000 212.928 0.192 212.952 ;
    END
  END ld_wp[61]
  PIN ld_wp[62]
    DIRECTION INPUT ;
    USE SIGNAL ;
    PORT
      LAYER M4 ;
        RECT 0.000 213.312 0.192 213.336 ;
    END
  END ld_wp[62]
  PIN ld_wp[63]
    DIRECTION INPUT ;
    USE SIGNAL ;
    PORT
      LAYER M4 ;
        RECT 0.000 213.648 0.192 213.672 ;
    END
  END ld_wp[63]
  PIN iv
    DIRECTION INPUT ;
    USE SIGNAL ;
    PORT
      LAYER M5 ;
        RECT 4.416 217.968 4.440 218.160 ;
    END
  END iv
  PIN ibank[0]
    DIRECTION INPUT ;
    USE SIGNAL ;
    PORT
      LAYER M5 ;
        RECT 4.704 217.968 4.728 218.160 ;
    END
  END ibank[0]
  PIN ibank[1]
    DIRECTION INPUT ;
    USE SIGNAL ;
    PORT
      LAYER M5 ;
        RECT 4.944 217.968 4.968 218.160 ;
    END
  END ibank[1]
  PIN ibank[2]
    DIRECTION INPUT ;
    USE SIGNAL ;
    PORT
      LAYER M5 ;
        RECT 5.184 217.968 5.208 218.160 ;
    END
  END ibank[2]
  PIN ib[0]
    DIRECTION INPUT ;
    USE SIGNAL ;
    PORT
      LAYER M5 ;
        RECT 5.472 217.968 5.496 218.160 ;
    END
  END ib[0]
  PIN ib[1]
    DIRECTION INPUT ;
    USE SIGNAL ;
    PORT
      LAYER M5 ;
        RECT 5.712 217.968 5.736 218.160 ;
    END
  END ib[1]
  PIN ib[2]
    DIRECTION INPUT ;
    USE SIGNAL ;
    PORT
      LAYER M5 ;
        RECT 6.000 217.968 6.024 218.160 ;
    END
  END ib[2]
  PIN ib[3]
    DIRECTION INPUT ;
    USE SIGNAL ;
    PORT
      LAYER M5 ;
        RECT 6.240 217.968 6.264 218.160 ;
    END
  END ib[3]
  PIN ib[4]
    DIRECTION INPUT ;
    USE SIGNAL ;
    PORT
      LAYER M5 ;
        RECT 6.480 217.968 6.504 218.160 ;
    END
  END ib[4]
  PIN ib[5]
    DIRECTION INPUT ;
    USE SIGNAL ;
    PORT
      LAYER M5 ;
        RECT 6.768 217.968 6.792 218.160 ;
    END
  END ib[5]
  PIN ib[6]
    DIRECTION INPUT ;
    USE SIGNAL ;
    PORT
      LAYER M5 ;
        RECT 7.008 217.968 7.032 218.160 ;
    END
  END ib[6]
  PIN ib[7]
    DIRECTION INPUT ;
    USE SIGNAL ;
    PORT
      LAYER M5 ;
        RECT 7.248 217.968 7.272 218.160 ;
    END
  END ib[7]
  PIN ib[8]
    DIRECTION INPUT ;
    USE SIGNAL ;
    PORT
      LAYER M5 ;
        RECT 7.536 217.968 7.560 218.160 ;
    END
  END ib[8]
  PIN ib[9]
    DIRECTION INPUT ;
    USE SIGNAL ;
    PORT
      LAYER M5 ;
        RECT 7.776 217.968 7.800 218.160 ;
    END
  END ib[9]
  PIN ib[10]
    DIRECTION INPUT ;
    USE SIGNAL ;
    PORT
      LAYER M5 ;
        RECT 8.016 217.968 8.040 218.160 ;
    END
  END ib[10]
  PIN ib[11]
    DIRECTION INPUT ;
    USE SIGNAL ;
    PORT
      LAYER M5 ;
        RECT 8.304 217.968 8.328 218.160 ;
    END
  END ib[11]
  PIN ib[12]
    DIRECTION INPUT ;
    USE SIGNAL ;
    PORT
      LAYER M5 ;
        RECT 8.544 217.968 8.568 218.160 ;
    END
  END ib[12]
  PIN ib[13]
    DIRECTION INPUT ;
    USE SIGNAL ;
    PORT
      LAYER M5 ;
        RECT 8.784 217.968 8.808 218.160 ;
    END
  END ib[13]
  PIN ib[14]
    DIRECTION INPUT ;
    USE SIGNAL ;
    PORT
      LAYER M5 ;
        RECT 9.072 217.968 9.096 218.160 ;
    END
  END ib[14]
  PIN ib[15]
    DIRECTION INPUT ;
    USE SIGNAL ;
    PORT
      LAYER M5 ;
        RECT 9.312 217.968 9.336 218.160 ;
    END
  END ib[15]
  PIN ib[16]
    DIRECTION INPUT ;
    USE SIGNAL ;
    PORT
      LAYER M5 ;
        RECT 9.552 217.968 9.576 218.160 ;
    END
  END ib[16]
  PIN ib[17]
    DIRECTION INPUT ;
    USE SIGNAL ;
    PORT
      LAYER M5 ;
        RECT 9.840 217.968 9.864 218.160 ;
    END
  END ib[17]
  PIN ib[18]
    DIRECTION INPUT ;
    USE SIGNAL ;
    PORT
      LAYER M5 ;
        RECT 10.080 217.968 10.104 218.160 ;
    END
  END ib[18]
  PIN ib[19]
    DIRECTION INPUT ;
    USE SIGNAL ;
    PORT
      LAYER M5 ;
        RECT 10.368 217.968 10.392 218.160 ;
    END
  END ib[19]
  PIN ib[20]
    DIRECTION INPUT ;
    USE SIGNAL ;
    PORT
      LAYER M5 ;
        RECT 10.608 217.968 10.632 218.160 ;
    END
  END ib[20]
  PIN ib[21]
    DIRECTION INPUT ;
    USE SIGNAL ;
    PORT
      LAYER M5 ;
        RECT 10.848 217.968 10.872 218.160 ;
    END
  END ib[21]
  PIN ib[22]
    DIRECTION INPUT ;
    USE SIGNAL ;
    PORT
      LAYER M5 ;
        RECT 11.136 217.968 11.160 218.160 ;
    END
  END ib[22]
  PIN ib[23]
    DIRECTION INPUT ;
    USE SIGNAL ;
    PORT
      LAYER M5 ;
        RECT 11.376 217.968 11.400 218.160 ;
    END
  END ib[23]
  PIN ib[24]
    DIRECTION INPUT ;
    USE SIGNAL ;
    PORT
      LAYER M5 ;
        RECT 11.616 217.968 11.640 218.160 ;
    END
  END ib[24]
  PIN ib[25]
    DIRECTION INPUT ;
    USE SIGNAL ;
    PORT
      LAYER M5 ;
        RECT 11.904 217.968 11.928 218.160 ;
    END
  END ib[25]
  PIN ib[26]
    DIRECTION INPUT ;
    USE SIGNAL ;
    PORT
      LAYER M5 ;
        RECT 12.144 217.968 12.168 218.160 ;
    END
  END ib[26]
  PIN ib[27]
    DIRECTION INPUT ;
    USE SIGNAL ;
    PORT
      LAYER M5 ;
        RECT 12.384 217.968 12.408 218.160 ;
    END
  END ib[27]
  PIN ib[28]
    DIRECTION INPUT ;
    USE SIGNAL ;
    PORT
      LAYER M5 ;
        RECT 12.672 217.968 12.696 218.160 ;
    END
  END ib[28]
  PIN ib[29]
    DIRECTION INPUT ;
    USE SIGNAL ;
    PORT
      LAYER M5 ;
        RECT 12.912 217.968 12.936 218.160 ;
    END
  END ib[29]
  PIN ib[30]
    DIRECTION INPUT ;
    USE SIGNAL ;
    PORT
      LAYER M5 ;
        RECT 13.152 217.968 13.176 218.160 ;
    END
  END ib[30]
  PIN ib[31]
    DIRECTION INPUT ;
    USE SIGNAL ;
    PORT
      LAYER M5 ;
        RECT 13.440 217.968 13.464 218.160 ;
    END
  END ib[31]
  PIN ib[32]
    DIRECTION INPUT ;
    USE SIGNAL ;
    PORT
      LAYER M5 ;
        RECT 13.680 217.968 13.704 218.160 ;
    END
  END ib[32]
  PIN ib[33]
    DIRECTION INPUT ;
    USE SIGNAL ;
    PORT
      LAYER M5 ;
        RECT 13.968 217.968 13.992 218.160 ;
    END
  END ib[33]
  PIN ib[34]
    DIRECTION INPUT ;
    USE SIGNAL ;
    PORT
      LAYER M5 ;
        RECT 14.208 217.968 14.232 218.160 ;
    END
  END ib[34]
  PIN ib[35]
    DIRECTION INPUT ;
    USE SIGNAL ;
    PORT
      LAYER M5 ;
        RECT 14.448 217.968 14.472 218.160 ;
    END
  END ib[35]
  PIN ib[36]
    DIRECTION INPUT ;
    USE SIGNAL ;
    PORT
      LAYER M5 ;
        RECT 14.736 217.968 14.760 218.160 ;
    END
  END ib[36]
  PIN ib[37]
    DIRECTION INPUT ;
    USE SIGNAL ;
    PORT
      LAYER M5 ;
        RECT 14.976 217.968 15.000 218.160 ;
    END
  END ib[37]
  PIN ib[38]
    DIRECTION INPUT ;
    USE SIGNAL ;
    PORT
      LAYER M5 ;
        RECT 15.216 217.968 15.240 218.160 ;
    END
  END ib[38]
  PIN ib[39]
    DIRECTION INPUT ;
    USE SIGNAL ;
    PORT
      LAYER M5 ;
        RECT 15.504 217.968 15.528 218.160 ;
    END
  END ib[39]
  PIN ib[40]
    DIRECTION INPUT ;
    USE SIGNAL ;
    PORT
      LAYER M5 ;
        RECT 15.744 217.968 15.768 218.160 ;
    END
  END ib[40]
  PIN ib[41]
    DIRECTION INPUT ;
    USE SIGNAL ;
    PORT
      LAYER M5 ;
        RECT 15.984 217.968 16.008 218.160 ;
    END
  END ib[41]
  PIN ib[42]
    DIRECTION INPUT ;
    USE SIGNAL ;
    PORT
      LAYER M5 ;
        RECT 16.272 217.968 16.296 218.160 ;
    END
  END ib[42]
  PIN ib[43]
    DIRECTION INPUT ;
    USE SIGNAL ;
    PORT
      LAYER M5 ;
        RECT 16.512 217.968 16.536 218.160 ;
    END
  END ib[43]
  PIN ib[44]
    DIRECTION INPUT ;
    USE SIGNAL ;
    PORT
      LAYER M5 ;
        RECT 16.752 217.968 16.776 218.160 ;
    END
  END ib[44]
  PIN ib[45]
    DIRECTION INPUT ;
    USE SIGNAL ;
    PORT
      LAYER M5 ;
        RECT 17.040 217.968 17.064 218.160 ;
    END
  END ib[45]
  PIN ib[46]
    DIRECTION INPUT ;
    USE SIGNAL ;
    PORT
      LAYER M5 ;
        RECT 17.280 217.968 17.304 218.160 ;
    END
  END ib[46]
  PIN ib[47]
    DIRECTION INPUT ;
    USE SIGNAL ;
    PORT
      LAYER M5 ;
        RECT 17.520 217.968 17.544 218.160 ;
    END
  END ib[47]
  PIN ib[48]
    DIRECTION INPUT ;
    USE SIGNAL ;
    PORT
      LAYER M5 ;
        RECT 17.808 217.968 17.832 218.160 ;
    END
  END ib[48]
  PIN ib[49]
    DIRECTION INPUT ;
    USE SIGNAL ;
    PORT
      LAYER M5 ;
        RECT 18.048 217.968 18.072 218.160 ;
    END
  END ib[49]
  PIN ib[50]
    DIRECTION INPUT ;
    USE SIGNAL ;
    PORT
      LAYER M5 ;
        RECT 18.336 217.968 18.360 218.160 ;
    END
  END ib[50]
  PIN ib[51]
    DIRECTION INPUT ;
    USE SIGNAL ;
    PORT
      LAYER M5 ;
        RECT 18.576 217.968 18.600 218.160 ;
    END
  END ib[51]
  PIN ib[52]
    DIRECTION INPUT ;
    USE SIGNAL ;
    PORT
      LAYER M5 ;
        RECT 18.816 217.968 18.840 218.160 ;
    END
  END ib[52]
  PIN ib[53]
    DIRECTION INPUT ;
    USE SIGNAL ;
    PORT
      LAYER M5 ;
        RECT 19.104 217.968 19.128 218.160 ;
    END
  END ib[53]
  PIN ib[54]
    DIRECTION INPUT ;
    USE SIGNAL ;
    PORT
      LAYER M5 ;
        RECT 19.344 217.968 19.368 218.160 ;
    END
  END ib[54]
  PIN ib[55]
    DIRECTION INPUT ;
    USE SIGNAL ;
    PORT
      LAYER M5 ;
        RECT 19.584 217.968 19.608 218.160 ;
    END
  END ib[55]
  PIN ib[56]
    DIRECTION INPUT ;
    USE SIGNAL ;
    PORT
      LAYER M5 ;
        RECT 19.872 217.968 19.896 218.160 ;
    END
  END ib[56]
  PIN ib[57]
    DIRECTION INPUT ;
    USE SIGNAL ;
    PORT
      LAYER M5 ;
        RECT 20.112 217.968 20.136 218.160 ;
    END
  END ib[57]
  PIN ib[58]
    DIRECTION INPUT ;
    USE SIGNAL ;
    PORT
      LAYER M5 ;
        RECT 20.352 217.968 20.376 218.160 ;
    END
  END ib[58]
  PIN ib[59]
    DIRECTION INPUT ;
    USE SIGNAL ;
    PORT
      LAYER M5 ;
        RECT 20.640 217.968 20.664 218.160 ;
    END
  END ib[59]
  PIN ib[60]
    DIRECTION INPUT ;
    USE SIGNAL ;
    PORT
      LAYER M5 ;
        RECT 20.880 217.968 20.904 218.160 ;
    END
  END ib[60]
  PIN ib[61]
    DIRECTION INPUT ;
    USE SIGNAL ;
    PORT
      LAYER M5 ;
        RECT 21.120 217.968 21.144 218.160 ;
    END
  END ib[61]
  PIN ib[62]
    DIRECTION INPUT ;
    USE SIGNAL ;
    PORT
      LAYER M5 ;
        RECT 21.408 217.968 21.432 218.160 ;
    END
  END ib[62]
  PIN ib[63]
    DIRECTION INPUT ;
    USE SIGNAL ;
    PORT
      LAYER M5 ;
        RECT 21.648 217.968 21.672 218.160 ;
    END
  END ib[63]
  PIN ib[64]
    DIRECTION INPUT ;
    USE SIGNAL ;
    PORT
      LAYER M5 ;
        RECT 21.888 217.968 21.912 218.160 ;
    END
  END ib[64]
  PIN ib[65]
    DIRECTION INPUT ;
    USE SIGNAL ;
    PORT
      LAYER M5 ;
        RECT 22.176 217.968 22.200 218.160 ;
    END
  END ib[65]
  PIN ib[66]
    DIRECTION INPUT ;
    USE SIGNAL ;
    PORT
      LAYER M5 ;
        RECT 22.416 217.968 22.440 218.160 ;
    END
  END ib[66]
  PIN ib[67]
    DIRECTION INPUT ;
    USE SIGNAL ;
    PORT
      LAYER M5 ;
        RECT 22.704 217.968 22.728 218.160 ;
    END
  END ib[67]
  PIN ib[68]
    DIRECTION INPUT ;
    USE SIGNAL ;
    PORT
      LAYER M5 ;
        RECT 22.944 217.968 22.968 218.160 ;
    END
  END ib[68]
  PIN ib[69]
    DIRECTION INPUT ;
    USE SIGNAL ;
    PORT
      LAYER M5 ;
        RECT 23.184 217.968 23.208 218.160 ;
    END
  END ib[69]
  PIN ib[70]
    DIRECTION INPUT ;
    USE SIGNAL ;
    PORT
      LAYER M5 ;
        RECT 23.472 217.968 23.496 218.160 ;
    END
  END ib[70]
  PIN ib[71]
    DIRECTION INPUT ;
    USE SIGNAL ;
    PORT
      LAYER M5 ;
        RECT 23.712 217.968 23.736 218.160 ;
    END
  END ib[71]
  PIN ib[72]
    DIRECTION INPUT ;
    USE SIGNAL ;
    PORT
      LAYER M5 ;
        RECT 23.952 217.968 23.976 218.160 ;
    END
  END ib[72]
  PIN ib[73]
    DIRECTION INPUT ;
    USE SIGNAL ;
    PORT
      LAYER M5 ;
        RECT 24.240 217.968 24.264 218.160 ;
    END
  END ib[73]
  PIN ib[74]
    DIRECTION INPUT ;
    USE SIGNAL ;
    PORT
      LAYER M5 ;
        RECT 24.480 217.968 24.504 218.160 ;
    END
  END ib[74]
  PIN ib[75]
    DIRECTION INPUT ;
    USE SIGNAL ;
    PORT
      LAYER M5 ;
        RECT 24.720 217.968 24.744 218.160 ;
    END
  END ib[75]
  PIN ib[76]
    DIRECTION INPUT ;
    USE SIGNAL ;
    PORT
      LAYER M5 ;
        RECT 25.008 217.968 25.032 218.160 ;
    END
  END ib[76]
  PIN ib[77]
    DIRECTION INPUT ;
    USE SIGNAL ;
    PORT
      LAYER M5 ;
        RECT 25.248 217.968 25.272 218.160 ;
    END
  END ib[77]
  PIN ib[78]
    DIRECTION INPUT ;
    USE SIGNAL ;
    PORT
      LAYER M5 ;
        RECT 25.488 217.968 25.512 218.160 ;
    END
  END ib[78]
  PIN ib[79]
    DIRECTION INPUT ;
    USE SIGNAL ;
    PORT
      LAYER M5 ;
        RECT 25.776 217.968 25.800 218.160 ;
    END
  END ib[79]
  PIN ib[80]
    DIRECTION INPUT ;
    USE SIGNAL ;
    PORT
      LAYER M5 ;
        RECT 26.016 217.968 26.040 218.160 ;
    END
  END ib[80]
  PIN ib[81]
    DIRECTION INPUT ;
    USE SIGNAL ;
    PORT
      LAYER M5 ;
        RECT 26.256 217.968 26.280 218.160 ;
    END
  END ib[81]
  PIN ib[82]
    DIRECTION INPUT ;
    USE SIGNAL ;
    PORT
      LAYER M5 ;
        RECT 26.544 217.968 26.568 218.160 ;
    END
  END ib[82]
  PIN ib[83]
    DIRECTION INPUT ;
    USE SIGNAL ;
    PORT
      LAYER M5 ;
        RECT 26.784 217.968 26.808 218.160 ;
    END
  END ib[83]
  PIN ib[84]
    DIRECTION INPUT ;
    USE SIGNAL ;
    PORT
      LAYER M5 ;
        RECT 27.072 217.968 27.096 218.160 ;
    END
  END ib[84]
  PIN ib[85]
    DIRECTION INPUT ;
    USE SIGNAL ;
    PORT
      LAYER M5 ;
        RECT 27.312 217.968 27.336 218.160 ;
    END
  END ib[85]
  PIN ib[86]
    DIRECTION INPUT ;
    USE SIGNAL ;
    PORT
      LAYER M5 ;
        RECT 27.552 217.968 27.576 218.160 ;
    END
  END ib[86]
  PIN ib[87]
    DIRECTION INPUT ;
    USE SIGNAL ;
    PORT
      LAYER M5 ;
        RECT 27.840 217.968 27.864 218.160 ;
    END
  END ib[87]
  PIN ib[88]
    DIRECTION INPUT ;
    USE SIGNAL ;
    PORT
      LAYER M5 ;
        RECT 28.080 217.968 28.104 218.160 ;
    END
  END ib[88]
  PIN ib[89]
    DIRECTION INPUT ;
    USE SIGNAL ;
    PORT
      LAYER M5 ;
        RECT 28.320 217.968 28.344 218.160 ;
    END
  END ib[89]
  PIN ib[90]
    DIRECTION INPUT ;
    USE SIGNAL ;
    PORT
      LAYER M5 ;
        RECT 28.608 217.968 28.632 218.160 ;
    END
  END ib[90]
  PIN ib[91]
    DIRECTION INPUT ;
    USE SIGNAL ;
    PORT
      LAYER M5 ;
        RECT 28.848 217.968 28.872 218.160 ;
    END
  END ib[91]
  PIN ib[92]
    DIRECTION INPUT ;
    USE SIGNAL ;
    PORT
      LAYER M5 ;
        RECT 29.088 217.968 29.112 218.160 ;
    END
  END ib[92]
  PIN ib[93]
    DIRECTION INPUT ;
    USE SIGNAL ;
    PORT
      LAYER M5 ;
        RECT 29.376 217.968 29.400 218.160 ;
    END
  END ib[93]
  PIN ib[94]
    DIRECTION INPUT ;
    USE SIGNAL ;
    PORT
      LAYER M5 ;
        RECT 29.616 217.968 29.640 218.160 ;
    END
  END ib[94]
  PIN ib[95]
    DIRECTION INPUT ;
    USE SIGNAL ;
    PORT
      LAYER M5 ;
        RECT 29.856 217.968 29.880 218.160 ;
    END
  END ib[95]
  PIN ib[96]
    DIRECTION INPUT ;
    USE SIGNAL ;
    PORT
      LAYER M5 ;
        RECT 30.144 217.968 30.168 218.160 ;
    END
  END ib[96]
  PIN ib[97]
    DIRECTION INPUT ;
    USE SIGNAL ;
    PORT
      LAYER M5 ;
        RECT 30.384 217.968 30.408 218.160 ;
    END
  END ib[97]
  PIN ib[98]
    DIRECTION INPUT ;
    USE SIGNAL ;
    PORT
      LAYER M5 ;
        RECT 30.624 217.968 30.648 218.160 ;
    END
  END ib[98]
  PIN ib[99]
    DIRECTION INPUT ;
    USE SIGNAL ;
    PORT
      LAYER M5 ;
        RECT 30.912 217.968 30.936 218.160 ;
    END
  END ib[99]
  PIN ib[100]
    DIRECTION INPUT ;
    USE SIGNAL ;
    PORT
      LAYER M5 ;
        RECT 31.152 217.968 31.176 218.160 ;
    END
  END ib[100]
  PIN ib[101]
    DIRECTION INPUT ;
    USE SIGNAL ;
    PORT
      LAYER M5 ;
        RECT 31.440 217.968 31.464 218.160 ;
    END
  END ib[101]
  PIN ib[102]
    DIRECTION INPUT ;
    USE SIGNAL ;
    PORT
      LAYER M5 ;
        RECT 31.680 217.968 31.704 218.160 ;
    END
  END ib[102]
  PIN ib[103]
    DIRECTION INPUT ;
    USE SIGNAL ;
    PORT
      LAYER M5 ;
        RECT 31.920 217.968 31.944 218.160 ;
    END
  END ib[103]
  PIN ib[104]
    DIRECTION INPUT ;
    USE SIGNAL ;
    PORT
      LAYER M5 ;
        RECT 32.208 217.968 32.232 218.160 ;
    END
  END ib[104]
  PIN ib[105]
    DIRECTION INPUT ;
    USE SIGNAL ;
    PORT
      LAYER M5 ;
        RECT 32.448 217.968 32.472 218.160 ;
    END
  END ib[105]
  PIN ib[106]
    DIRECTION INPUT ;
    USE SIGNAL ;
    PORT
      LAYER M5 ;
        RECT 32.688 217.968 32.712 218.160 ;
    END
  END ib[106]
  PIN ib[107]
    DIRECTION INPUT ;
    USE SIGNAL ;
    PORT
      LAYER M5 ;
        RECT 32.976 217.968 33.000 218.160 ;
    END
  END ib[107]
  PIN ib[108]
    DIRECTION INPUT ;
    USE SIGNAL ;
    PORT
      LAYER M5 ;
        RECT 33.216 217.968 33.240 218.160 ;
    END
  END ib[108]
  PIN ib[109]
    DIRECTION INPUT ;
    USE SIGNAL ;
    PORT
      LAYER M5 ;
        RECT 33.456 217.968 33.480 218.160 ;
    END
  END ib[109]
  PIN ib[110]
    DIRECTION INPUT ;
    USE SIGNAL ;
    PORT
      LAYER M5 ;
        RECT 33.744 217.968 33.768 218.160 ;
    END
  END ib[110]
  PIN ib[111]
    DIRECTION INPUT ;
    USE SIGNAL ;
    PORT
      LAYER M5 ;
        RECT 33.984 217.968 34.008 218.160 ;
    END
  END ib[111]
  PIN ib[112]
    DIRECTION INPUT ;
    USE SIGNAL ;
    PORT
      LAYER M5 ;
        RECT 34.224 217.968 34.248 218.160 ;
    END
  END ib[112]
  PIN ib[113]
    DIRECTION INPUT ;
    USE SIGNAL ;
    PORT
      LAYER M5 ;
        RECT 34.512 217.968 34.536 218.160 ;
    END
  END ib[113]
  PIN ib[114]
    DIRECTION INPUT ;
    USE SIGNAL ;
    PORT
      LAYER M5 ;
        RECT 34.752 217.968 34.776 218.160 ;
    END
  END ib[114]
  PIN ib[115]
    DIRECTION INPUT ;
    USE SIGNAL ;
    PORT
      LAYER M5 ;
        RECT 34.992 217.968 35.016 218.160 ;
    END
  END ib[115]
  PIN ib[116]
    DIRECTION INPUT ;
    USE SIGNAL ;
    PORT
      LAYER M5 ;
        RECT 35.280 217.968 35.304 218.160 ;
    END
  END ib[116]
  PIN ib[117]
    DIRECTION INPUT ;
    USE SIGNAL ;
    PORT
      LAYER M5 ;
        RECT 35.520 217.968 35.544 218.160 ;
    END
  END ib[117]
  PIN ib[118]
    DIRECTION INPUT ;
    USE SIGNAL ;
    PORT
      LAYER M5 ;
        RECT 35.808 217.968 35.832 218.160 ;
    END
  END ib[118]
  PIN ib[119]
    DIRECTION INPUT ;
    USE SIGNAL ;
    PORT
      LAYER M5 ;
        RECT 36.048 217.968 36.072 218.160 ;
    END
  END ib[119]
  PIN ib[120]
    DIRECTION INPUT ;
    USE SIGNAL ;
    PORT
      LAYER M5 ;
        RECT 36.288 217.968 36.312 218.160 ;
    END
  END ib[120]
  PIN ib[121]
    DIRECTION INPUT ;
    USE SIGNAL ;
    PORT
      LAYER M5 ;
        RECT 36.576 217.968 36.600 218.160 ;
    END
  END ib[121]
  PIN ib[122]
    DIRECTION INPUT ;
    USE SIGNAL ;
    PORT
      LAYER M5 ;
        RECT 36.816 217.968 36.840 218.160 ;
    END
  END ib[122]
  PIN ib[123]
    DIRECTION INPUT ;
    USE SIGNAL ;
    PORT
      LAYER M5 ;
        RECT 37.056 217.968 37.080 218.160 ;
    END
  END ib[123]
  PIN ib[124]
    DIRECTION INPUT ;
    USE SIGNAL ;
    PORT
      LAYER M5 ;
        RECT 37.344 217.968 37.368 218.160 ;
    END
  END ib[124]
  PIN ib[125]
    DIRECTION INPUT ;
    USE SIGNAL ;
    PORT
      LAYER M5 ;
        RECT 37.584 217.968 37.608 218.160 ;
    END
  END ib[125]
  PIN ib[126]
    DIRECTION INPUT ;
    USE SIGNAL ;
    PORT
      LAYER M5 ;
        RECT 37.824 217.968 37.848 218.160 ;
    END
  END ib[126]
  PIN ib[127]
    DIRECTION INPUT ;
    USE SIGNAL ;
    PORT
      LAYER M5 ;
        RECT 38.112 217.968 38.136 218.160 ;
    END
  END ib[127]
  PIN ib[128]
    DIRECTION INPUT ;
    USE SIGNAL ;
    PORT
      LAYER M5 ;
        RECT 38.352 217.968 38.376 218.160 ;
    END
  END ib[128]
  PIN ib[129]
    DIRECTION INPUT ;
    USE SIGNAL ;
    PORT
      LAYER M5 ;
        RECT 38.592 217.968 38.616 218.160 ;
    END
  END ib[129]
  PIN ib[130]
    DIRECTION INPUT ;
    USE SIGNAL ;
    PORT
      LAYER M5 ;
        RECT 38.880 217.968 38.904 218.160 ;
    END
  END ib[130]
  PIN ib[131]
    DIRECTION INPUT ;
    USE SIGNAL ;
    PORT
      LAYER M5 ;
        RECT 39.120 217.968 39.144 218.160 ;
    END
  END ib[131]
  PIN ib[132]
    DIRECTION INPUT ;
    USE SIGNAL ;
    PORT
      LAYER M5 ;
        RECT 39.360 217.968 39.384 218.160 ;
    END
  END ib[132]
  PIN ib[133]
    DIRECTION INPUT ;
    USE SIGNAL ;
    PORT
      LAYER M5 ;
        RECT 39.648 217.968 39.672 218.160 ;
    END
  END ib[133]
  PIN ib[134]
    DIRECTION INPUT ;
    USE SIGNAL ;
    PORT
      LAYER M5 ;
        RECT 39.888 217.968 39.912 218.160 ;
    END
  END ib[134]
  PIN ib[135]
    DIRECTION INPUT ;
    USE SIGNAL ;
    PORT
      LAYER M5 ;
        RECT 40.176 217.968 40.200 218.160 ;
    END
  END ib[135]
  PIN ib[136]
    DIRECTION INPUT ;
    USE SIGNAL ;
    PORT
      LAYER M5 ;
        RECT 40.416 217.968 40.440 218.160 ;
    END
  END ib[136]
  PIN ib[137]
    DIRECTION INPUT ;
    USE SIGNAL ;
    PORT
      LAYER M5 ;
        RECT 40.656 217.968 40.680 218.160 ;
    END
  END ib[137]
  PIN ib[138]
    DIRECTION INPUT ;
    USE SIGNAL ;
    PORT
      LAYER M5 ;
        RECT 40.944 217.968 40.968 218.160 ;
    END
  END ib[138]
  PIN ib[139]
    DIRECTION INPUT ;
    USE SIGNAL ;
    PORT
      LAYER M5 ;
        RECT 41.184 217.968 41.208 218.160 ;
    END
  END ib[139]
  PIN ib[140]
    DIRECTION INPUT ;
    USE SIGNAL ;
    PORT
      LAYER M5 ;
        RECT 41.424 217.968 41.448 218.160 ;
    END
  END ib[140]
  PIN ib[141]
    DIRECTION INPUT ;
    USE SIGNAL ;
    PORT
      LAYER M5 ;
        RECT 41.712 217.968 41.736 218.160 ;
    END
  END ib[141]
  PIN ib[142]
    DIRECTION INPUT ;
    USE SIGNAL ;
    PORT
      LAYER M5 ;
        RECT 41.952 217.968 41.976 218.160 ;
    END
  END ib[142]
  PIN ib[143]
    DIRECTION INPUT ;
    USE SIGNAL ;
    PORT
      LAYER M5 ;
        RECT 42.192 217.968 42.216 218.160 ;
    END
  END ib[143]
  PIN ib[144]
    DIRECTION INPUT ;
    USE SIGNAL ;
    PORT
      LAYER M5 ;
        RECT 42.480 217.968 42.504 218.160 ;
    END
  END ib[144]
  PIN ib[145]
    DIRECTION INPUT ;
    USE SIGNAL ;
    PORT
      LAYER M5 ;
        RECT 42.720 217.968 42.744 218.160 ;
    END
  END ib[145]
  PIN ib[146]
    DIRECTION INPUT ;
    USE SIGNAL ;
    PORT
      LAYER M5 ;
        RECT 42.960 217.968 42.984 218.160 ;
    END
  END ib[146]
  PIN ib[147]
    DIRECTION INPUT ;
    USE SIGNAL ;
    PORT
      LAYER M5 ;
        RECT 43.248 217.968 43.272 218.160 ;
    END
  END ib[147]
  PIN ib[148]
    DIRECTION INPUT ;
    USE SIGNAL ;
    PORT
      LAYER M5 ;
        RECT 43.488 217.968 43.512 218.160 ;
    END
  END ib[148]
  PIN ib[149]
    DIRECTION INPUT ;
    USE SIGNAL ;
    PORT
      LAYER M5 ;
        RECT 43.776 217.968 43.800 218.160 ;
    END
  END ib[149]
  PIN ib[150]
    DIRECTION INPUT ;
    USE SIGNAL ;
    PORT
      LAYER M5 ;
        RECT 44.016 217.968 44.040 218.160 ;
    END
  END ib[150]
  PIN ib[151]
    DIRECTION INPUT ;
    USE SIGNAL ;
    PORT
      LAYER M5 ;
        RECT 44.256 217.968 44.280 218.160 ;
    END
  END ib[151]
  PIN ib[152]
    DIRECTION INPUT ;
    USE SIGNAL ;
    PORT
      LAYER M5 ;
        RECT 44.544 217.968 44.568 218.160 ;
    END
  END ib[152]
  PIN ib[153]
    DIRECTION INPUT ;
    USE SIGNAL ;
    PORT
      LAYER M5 ;
        RECT 44.784 217.968 44.808 218.160 ;
    END
  END ib[153]
  PIN ib[154]
    DIRECTION INPUT ;
    USE SIGNAL ;
    PORT
      LAYER M5 ;
        RECT 45.024 217.968 45.048 218.160 ;
    END
  END ib[154]
  PIN ib[155]
    DIRECTION INPUT ;
    USE SIGNAL ;
    PORT
      LAYER M5 ;
        RECT 45.312 217.968 45.336 218.160 ;
    END
  END ib[155]
  PIN ib[156]
    DIRECTION INPUT ;
    USE SIGNAL ;
    PORT
      LAYER M5 ;
        RECT 45.552 217.968 45.576 218.160 ;
    END
  END ib[156]
  PIN ib[157]
    DIRECTION INPUT ;
    USE SIGNAL ;
    PORT
      LAYER M5 ;
        RECT 45.792 217.968 45.816 218.160 ;
    END
  END ib[157]
  PIN ib[158]
    DIRECTION INPUT ;
    USE SIGNAL ;
    PORT
      LAYER M5 ;
        RECT 46.080 217.968 46.104 218.160 ;
    END
  END ib[158]
  PIN ib[159]
    DIRECTION INPUT ;
    USE SIGNAL ;
    PORT
      LAYER M5 ;
        RECT 46.320 217.968 46.344 218.160 ;
    END
  END ib[159]
  PIN ib[160]
    DIRECTION INPUT ;
    USE SIGNAL ;
    PORT
      LAYER M5 ;
        RECT 46.560 217.968 46.584 218.160 ;
    END
  END ib[160]
  PIN ib[161]
    DIRECTION INPUT ;
    USE SIGNAL ;
    PORT
      LAYER M5 ;
        RECT 46.848 217.968 46.872 218.160 ;
    END
  END ib[161]
  PIN ib[162]
    DIRECTION INPUT ;
    USE SIGNAL ;
    PORT
      LAYER M5 ;
        RECT 47.088 217.968 47.112 218.160 ;
    END
  END ib[162]
  PIN ib[163]
    DIRECTION INPUT ;
    USE SIGNAL ;
    PORT
      LAYER M5 ;
        RECT 47.328 217.968 47.352 218.160 ;
    END
  END ib[163]
  PIN ib[164]
    DIRECTION INPUT ;
    USE SIGNAL ;
    PORT
      LAYER M5 ;
        RECT 47.616 217.968 47.640 218.160 ;
    END
  END ib[164]
  PIN ib[165]
    DIRECTION INPUT ;
    USE SIGNAL ;
    PORT
      LAYER M5 ;
        RECT 47.856 217.968 47.880 218.160 ;
    END
  END ib[165]
  PIN ib[166]
    DIRECTION INPUT ;
    USE SIGNAL ;
    PORT
      LAYER M5 ;
        RECT 48.144 217.968 48.168 218.160 ;
    END
  END ib[166]
  PIN ib[167]
    DIRECTION INPUT ;
    USE SIGNAL ;
    PORT
      LAYER M5 ;
        RECT 48.384 217.968 48.408 218.160 ;
    END
  END ib[167]
  PIN ib[168]
    DIRECTION INPUT ;
    USE SIGNAL ;
    PORT
      LAYER M5 ;
        RECT 48.624 217.968 48.648 218.160 ;
    END
  END ib[168]
  PIN ib[169]
    DIRECTION INPUT ;
    USE SIGNAL ;
    PORT
      LAYER M5 ;
        RECT 48.912 217.968 48.936 218.160 ;
    END
  END ib[169]
  PIN ib[170]
    DIRECTION INPUT ;
    USE SIGNAL ;
    PORT
      LAYER M5 ;
        RECT 49.152 217.968 49.176 218.160 ;
    END
  END ib[170]
  PIN ib[171]
    DIRECTION INPUT ;
    USE SIGNAL ;
    PORT
      LAYER M5 ;
        RECT 49.392 217.968 49.416 218.160 ;
    END
  END ib[171]
  PIN ib[172]
    DIRECTION INPUT ;
    USE SIGNAL ;
    PORT
      LAYER M5 ;
        RECT 49.680 217.968 49.704 218.160 ;
    END
  END ib[172]
  PIN ib[173]
    DIRECTION INPUT ;
    USE SIGNAL ;
    PORT
      LAYER M5 ;
        RECT 49.920 217.968 49.944 218.160 ;
    END
  END ib[173]
  PIN ib[174]
    DIRECTION INPUT ;
    USE SIGNAL ;
    PORT
      LAYER M5 ;
        RECT 50.160 217.968 50.184 218.160 ;
    END
  END ib[174]
  PIN ib[175]
    DIRECTION INPUT ;
    USE SIGNAL ;
    PORT
      LAYER M5 ;
        RECT 50.448 217.968 50.472 218.160 ;
    END
  END ib[175]
  PIN ib[176]
    DIRECTION INPUT ;
    USE SIGNAL ;
    PORT
      LAYER M5 ;
        RECT 50.688 217.968 50.712 218.160 ;
    END
  END ib[176]
  PIN ib[177]
    DIRECTION INPUT ;
    USE SIGNAL ;
    PORT
      LAYER M5 ;
        RECT 50.928 217.968 50.952 218.160 ;
    END
  END ib[177]
  PIN ib[178]
    DIRECTION INPUT ;
    USE SIGNAL ;
    PORT
      LAYER M5 ;
        RECT 51.216 217.968 51.240 218.160 ;
    END
  END ib[178]
  PIN ib[179]
    DIRECTION INPUT ;
    USE SIGNAL ;
    PORT
      LAYER M5 ;
        RECT 51.456 217.968 51.480 218.160 ;
    END
  END ib[179]
  PIN ib[180]
    DIRECTION INPUT ;
    USE SIGNAL ;
    PORT
      LAYER M5 ;
        RECT 51.696 217.968 51.720 218.160 ;
    END
  END ib[180]
  PIN ib[181]
    DIRECTION INPUT ;
    USE SIGNAL ;
    PORT
      LAYER M5 ;
        RECT 51.984 217.968 52.008 218.160 ;
    END
  END ib[181]
  PIN ib[182]
    DIRECTION INPUT ;
    USE SIGNAL ;
    PORT
      LAYER M5 ;
        RECT 52.224 217.968 52.248 218.160 ;
    END
  END ib[182]
  PIN ib[183]
    DIRECTION INPUT ;
    USE SIGNAL ;
    PORT
      LAYER M5 ;
        RECT 52.512 217.968 52.536 218.160 ;
    END
  END ib[183]
  PIN ib[184]
    DIRECTION INPUT ;
    USE SIGNAL ;
    PORT
      LAYER M5 ;
        RECT 52.752 217.968 52.776 218.160 ;
    END
  END ib[184]
  PIN ib[185]
    DIRECTION INPUT ;
    USE SIGNAL ;
    PORT
      LAYER M5 ;
        RECT 52.992 217.968 53.016 218.160 ;
    END
  END ib[185]
  PIN ib[186]
    DIRECTION INPUT ;
    USE SIGNAL ;
    PORT
      LAYER M5 ;
        RECT 53.280 217.968 53.304 218.160 ;
    END
  END ib[186]
  PIN ib[187]
    DIRECTION INPUT ;
    USE SIGNAL ;
    PORT
      LAYER M5 ;
        RECT 53.520 217.968 53.544 218.160 ;
    END
  END ib[187]
  PIN ib[188]
    DIRECTION INPUT ;
    USE SIGNAL ;
    PORT
      LAYER M5 ;
        RECT 53.760 217.968 53.784 218.160 ;
    END
  END ib[188]
  PIN ib[189]
    DIRECTION INPUT ;
    USE SIGNAL ;
    PORT
      LAYER M5 ;
        RECT 54.048 217.968 54.072 218.160 ;
    END
  END ib[189]
  PIN ib[190]
    DIRECTION INPUT ;
    USE SIGNAL ;
    PORT
      LAYER M5 ;
        RECT 54.288 217.968 54.312 218.160 ;
    END
  END ib[190]
  PIN ib[191]
    DIRECTION INPUT ;
    USE SIGNAL ;
    PORT
      LAYER M5 ;
        RECT 54.528 217.968 54.552 218.160 ;
    END
  END ib[191]
  PIN ib[192]
    DIRECTION INPUT ;
    USE SIGNAL ;
    PORT
      LAYER M5 ;
        RECT 54.816 217.968 54.840 218.160 ;
    END
  END ib[192]
  PIN ib[193]
    DIRECTION INPUT ;
    USE SIGNAL ;
    PORT
      LAYER M5 ;
        RECT 55.056 217.968 55.080 218.160 ;
    END
  END ib[193]
  PIN ib[194]
    DIRECTION INPUT ;
    USE SIGNAL ;
    PORT
      LAYER M5 ;
        RECT 55.296 217.968 55.320 218.160 ;
    END
  END ib[194]
  PIN ib[195]
    DIRECTION INPUT ;
    USE SIGNAL ;
    PORT
      LAYER M5 ;
        RECT 55.584 217.968 55.608 218.160 ;
    END
  END ib[195]
  PIN ib[196]
    DIRECTION INPUT ;
    USE SIGNAL ;
    PORT
      LAYER M5 ;
        RECT 55.824 217.968 55.848 218.160 ;
    END
  END ib[196]
  PIN ib[197]
    DIRECTION INPUT ;
    USE SIGNAL ;
    PORT
      LAYER M5 ;
        RECT 56.064 217.968 56.088 218.160 ;
    END
  END ib[197]
  PIN ib[198]
    DIRECTION INPUT ;
    USE SIGNAL ;
    PORT
      LAYER M5 ;
        RECT 56.352 217.968 56.376 218.160 ;
    END
  END ib[198]
  PIN ib[199]
    DIRECTION INPUT ;
    USE SIGNAL ;
    PORT
      LAYER M5 ;
        RECT 56.592 217.968 56.616 218.160 ;
    END
  END ib[199]
  PIN ib[200]
    DIRECTION INPUT ;
    USE SIGNAL ;
    PORT
      LAYER M5 ;
        RECT 56.880 217.968 56.904 218.160 ;
    END
  END ib[200]
  PIN ib[201]
    DIRECTION INPUT ;
    USE SIGNAL ;
    PORT
      LAYER M5 ;
        RECT 57.120 217.968 57.144 218.160 ;
    END
  END ib[201]
  PIN ib[202]
    DIRECTION INPUT ;
    USE SIGNAL ;
    PORT
      LAYER M5 ;
        RECT 57.360 217.968 57.384 218.160 ;
    END
  END ib[202]
  PIN ib[203]
    DIRECTION INPUT ;
    USE SIGNAL ;
    PORT
      LAYER M5 ;
        RECT 57.648 217.968 57.672 218.160 ;
    END
  END ib[203]
  PIN ib[204]
    DIRECTION INPUT ;
    USE SIGNAL ;
    PORT
      LAYER M5 ;
        RECT 57.888 217.968 57.912 218.160 ;
    END
  END ib[204]
  PIN ib[205]
    DIRECTION INPUT ;
    USE SIGNAL ;
    PORT
      LAYER M5 ;
        RECT 58.128 217.968 58.152 218.160 ;
    END
  END ib[205]
  PIN ib[206]
    DIRECTION INPUT ;
    USE SIGNAL ;
    PORT
      LAYER M5 ;
        RECT 58.416 217.968 58.440 218.160 ;
    END
  END ib[206]
  PIN ib[207]
    DIRECTION INPUT ;
    USE SIGNAL ;
    PORT
      LAYER M5 ;
        RECT 58.656 217.968 58.680 218.160 ;
    END
  END ib[207]
  PIN ib[208]
    DIRECTION INPUT ;
    USE SIGNAL ;
    PORT
      LAYER M5 ;
        RECT 58.896 217.968 58.920 218.160 ;
    END
  END ib[208]
  PIN ib[209]
    DIRECTION INPUT ;
    USE SIGNAL ;
    PORT
      LAYER M5 ;
        RECT 59.184 217.968 59.208 218.160 ;
    END
  END ib[209]
  PIN ib[210]
    DIRECTION INPUT ;
    USE SIGNAL ;
    PORT
      LAYER M5 ;
        RECT 59.424 217.968 59.448 218.160 ;
    END
  END ib[210]
  PIN ib[211]
    DIRECTION INPUT ;
    USE SIGNAL ;
    PORT
      LAYER M5 ;
        RECT 59.664 217.968 59.688 218.160 ;
    END
  END ib[211]
  PIN ib[212]
    DIRECTION INPUT ;
    USE SIGNAL ;
    PORT
      LAYER M5 ;
        RECT 59.952 217.968 59.976 218.160 ;
    END
  END ib[212]
  PIN ib[213]
    DIRECTION INPUT ;
    USE SIGNAL ;
    PORT
      LAYER M5 ;
        RECT 60.192 217.968 60.216 218.160 ;
    END
  END ib[213]
  PIN ib[214]
    DIRECTION INPUT ;
    USE SIGNAL ;
    PORT
      LAYER M5 ;
        RECT 60.432 217.968 60.456 218.160 ;
    END
  END ib[214]
  PIN ib[215]
    DIRECTION INPUT ;
    USE SIGNAL ;
    PORT
      LAYER M5 ;
        RECT 60.720 217.968 60.744 218.160 ;
    END
  END ib[215]
  PIN ib[216]
    DIRECTION INPUT ;
    USE SIGNAL ;
    PORT
      LAYER M5 ;
        RECT 60.960 217.968 60.984 218.160 ;
    END
  END ib[216]
  PIN ib[217]
    DIRECTION INPUT ;
    USE SIGNAL ;
    PORT
      LAYER M5 ;
        RECT 61.248 217.968 61.272 218.160 ;
    END
  END ib[217]
  PIN ib[218]
    DIRECTION INPUT ;
    USE SIGNAL ;
    PORT
      LAYER M5 ;
        RECT 61.488 217.968 61.512 218.160 ;
    END
  END ib[218]
  PIN ib[219]
    DIRECTION INPUT ;
    USE SIGNAL ;
    PORT
      LAYER M5 ;
        RECT 61.728 217.968 61.752 218.160 ;
    END
  END ib[219]
  PIN ib[220]
    DIRECTION INPUT ;
    USE SIGNAL ;
    PORT
      LAYER M5 ;
        RECT 62.016 217.968 62.040 218.160 ;
    END
  END ib[220]
  PIN ib[221]
    DIRECTION INPUT ;
    USE SIGNAL ;
    PORT
      LAYER M5 ;
        RECT 62.256 217.968 62.280 218.160 ;
    END
  END ib[221]
  PIN ib[222]
    DIRECTION INPUT ;
    USE SIGNAL ;
    PORT
      LAYER M5 ;
        RECT 62.496 217.968 62.520 218.160 ;
    END
  END ib[222]
  PIN ib[223]
    DIRECTION INPUT ;
    USE SIGNAL ;
    PORT
      LAYER M5 ;
        RECT 62.784 217.968 62.808 218.160 ;
    END
  END ib[223]
  PIN ib[224]
    DIRECTION INPUT ;
    USE SIGNAL ;
    PORT
      LAYER M5 ;
        RECT 63.024 217.968 63.048 218.160 ;
    END
  END ib[224]
  PIN ib[225]
    DIRECTION INPUT ;
    USE SIGNAL ;
    PORT
      LAYER M5 ;
        RECT 63.264 217.968 63.288 218.160 ;
    END
  END ib[225]
  PIN ib[226]
    DIRECTION INPUT ;
    USE SIGNAL ;
    PORT
      LAYER M5 ;
        RECT 63.552 217.968 63.576 218.160 ;
    END
  END ib[226]
  PIN ib[227]
    DIRECTION INPUT ;
    USE SIGNAL ;
    PORT
      LAYER M5 ;
        RECT 63.792 217.968 63.816 218.160 ;
    END
  END ib[227]
  PIN ib[228]
    DIRECTION INPUT ;
    USE SIGNAL ;
    PORT
      LAYER M5 ;
        RECT 64.032 217.968 64.056 218.160 ;
    END
  END ib[228]
  PIN ib[229]
    DIRECTION INPUT ;
    USE SIGNAL ;
    PORT
      LAYER M5 ;
        RECT 64.320 217.968 64.344 218.160 ;
    END
  END ib[229]
  PIN ib[230]
    DIRECTION INPUT ;
    USE SIGNAL ;
    PORT
      LAYER M5 ;
        RECT 64.560 217.968 64.584 218.160 ;
    END
  END ib[230]
  PIN ib[231]
    DIRECTION INPUT ;
    USE SIGNAL ;
    PORT
      LAYER M5 ;
        RECT 64.800 217.968 64.824 218.160 ;
    END
  END ib[231]
  PIN ib[232]
    DIRECTION INPUT ;
    USE SIGNAL ;
    PORT
      LAYER M5 ;
        RECT 65.088 217.968 65.112 218.160 ;
    END
  END ib[232]
  PIN ib[233]
    DIRECTION INPUT ;
    USE SIGNAL ;
    PORT
      LAYER M5 ;
        RECT 65.328 217.968 65.352 218.160 ;
    END
  END ib[233]
  PIN ib[234]
    DIRECTION INPUT ;
    USE SIGNAL ;
    PORT
      LAYER M5 ;
        RECT 65.616 217.968 65.640 218.160 ;
    END
  END ib[234]
  PIN ib[235]
    DIRECTION INPUT ;
    USE SIGNAL ;
    PORT
      LAYER M5 ;
        RECT 65.856 217.968 65.880 218.160 ;
    END
  END ib[235]
  PIN ib[236]
    DIRECTION INPUT ;
    USE SIGNAL ;
    PORT
      LAYER M5 ;
        RECT 66.096 217.968 66.120 218.160 ;
    END
  END ib[236]
  PIN ib[237]
    DIRECTION INPUT ;
    USE SIGNAL ;
    PORT
      LAYER M5 ;
        RECT 66.384 217.968 66.408 218.160 ;
    END
  END ib[237]
  PIN ib[238]
    DIRECTION INPUT ;
    USE SIGNAL ;
    PORT
      LAYER M5 ;
        RECT 66.624 217.968 66.648 218.160 ;
    END
  END ib[238]
  PIN ib[239]
    DIRECTION INPUT ;
    USE SIGNAL ;
    PORT
      LAYER M5 ;
        RECT 66.864 217.968 66.888 218.160 ;
    END
  END ib[239]
  PIN ib[240]
    DIRECTION INPUT ;
    USE SIGNAL ;
    PORT
      LAYER M5 ;
        RECT 67.152 217.968 67.176 218.160 ;
    END
  END ib[240]
  PIN ib[241]
    DIRECTION INPUT ;
    USE SIGNAL ;
    PORT
      LAYER M5 ;
        RECT 67.392 217.968 67.416 218.160 ;
    END
  END ib[241]
  PIN ib[242]
    DIRECTION INPUT ;
    USE SIGNAL ;
    PORT
      LAYER M5 ;
        RECT 67.632 217.968 67.656 218.160 ;
    END
  END ib[242]
  PIN ib[243]
    DIRECTION INPUT ;
    USE SIGNAL ;
    PORT
      LAYER M5 ;
        RECT 67.920 217.968 67.944 218.160 ;
    END
  END ib[243]
  PIN ib[244]
    DIRECTION INPUT ;
    USE SIGNAL ;
    PORT
      LAYER M5 ;
        RECT 68.160 217.968 68.184 218.160 ;
    END
  END ib[244]
  PIN ib[245]
    DIRECTION INPUT ;
    USE SIGNAL ;
    PORT
      LAYER M5 ;
        RECT 68.400 217.968 68.424 218.160 ;
    END
  END ib[245]
  PIN ib[246]
    DIRECTION INPUT ;
    USE SIGNAL ;
    PORT
      LAYER M5 ;
        RECT 68.688 217.968 68.712 218.160 ;
    END
  END ib[246]
  PIN ib[247]
    DIRECTION INPUT ;
    USE SIGNAL ;
    PORT
      LAYER M5 ;
        RECT 68.928 217.968 68.952 218.160 ;
    END
  END ib[247]
  PIN ib[248]
    DIRECTION INPUT ;
    USE SIGNAL ;
    PORT
      LAYER M5 ;
        RECT 69.168 217.968 69.192 218.160 ;
    END
  END ib[248]
  PIN ib[249]
    DIRECTION INPUT ;
    USE SIGNAL ;
    PORT
      LAYER M5 ;
        RECT 69.456 217.968 69.480 218.160 ;
    END
  END ib[249]
  PIN ib[250]
    DIRECTION INPUT ;
    USE SIGNAL ;
    PORT
      LAYER M5 ;
        RECT 69.696 217.968 69.720 218.160 ;
    END
  END ib[250]
  PIN ib[251]
    DIRECTION INPUT ;
    USE SIGNAL ;
    PORT
      LAYER M5 ;
        RECT 69.984 217.968 70.008 218.160 ;
    END
  END ib[251]
  PIN ib[252]
    DIRECTION INPUT ;
    USE SIGNAL ;
    PORT
      LAYER M5 ;
        RECT 70.224 217.968 70.248 218.160 ;
    END
  END ib[252]
  PIN ib[253]
    DIRECTION INPUT ;
    USE SIGNAL ;
    PORT
      LAYER M5 ;
        RECT 70.464 217.968 70.488 218.160 ;
    END
  END ib[253]
  PIN ib[254]
    DIRECTION INPUT ;
    USE SIGNAL ;
    PORT
      LAYER M5 ;
        RECT 70.752 217.968 70.776 218.160 ;
    END
  END ib[254]
  PIN ib[255]
    DIRECTION INPUT ;
    USE SIGNAL ;
    PORT
      LAYER M5 ;
        RECT 70.992 217.968 71.016 218.160 ;
    END
  END ib[255]
  PIN ib[256]
    DIRECTION INPUT ;
    USE SIGNAL ;
    PORT
      LAYER M5 ;
        RECT 71.232 217.968 71.256 218.160 ;
    END
  END ib[256]
  PIN ib[257]
    DIRECTION INPUT ;
    USE SIGNAL ;
    PORT
      LAYER M5 ;
        RECT 71.520 217.968 71.544 218.160 ;
    END
  END ib[257]
  PIN ib[258]
    DIRECTION INPUT ;
    USE SIGNAL ;
    PORT
      LAYER M5 ;
        RECT 71.760 217.968 71.784 218.160 ;
    END
  END ib[258]
  PIN ib[259]
    DIRECTION INPUT ;
    USE SIGNAL ;
    PORT
      LAYER M5 ;
        RECT 72.000 217.968 72.024 218.160 ;
    END
  END ib[259]
  PIN ib[260]
    DIRECTION INPUT ;
    USE SIGNAL ;
    PORT
      LAYER M5 ;
        RECT 72.288 217.968 72.312 218.160 ;
    END
  END ib[260]
  PIN ib[261]
    DIRECTION INPUT ;
    USE SIGNAL ;
    PORT
      LAYER M5 ;
        RECT 72.528 217.968 72.552 218.160 ;
    END
  END ib[261]
  PIN ib[262]
    DIRECTION INPUT ;
    USE SIGNAL ;
    PORT
      LAYER M5 ;
        RECT 72.768 217.968 72.792 218.160 ;
    END
  END ib[262]
  PIN ib[263]
    DIRECTION INPUT ;
    USE SIGNAL ;
    PORT
      LAYER M5 ;
        RECT 73.056 217.968 73.080 218.160 ;
    END
  END ib[263]
  PIN ib[264]
    DIRECTION INPUT ;
    USE SIGNAL ;
    PORT
      LAYER M5 ;
        RECT 73.296 217.968 73.320 218.160 ;
    END
  END ib[264]
  PIN ib[265]
    DIRECTION INPUT ;
    USE SIGNAL ;
    PORT
      LAYER M5 ;
        RECT 73.584 217.968 73.608 218.160 ;
    END
  END ib[265]
  PIN ib[266]
    DIRECTION INPUT ;
    USE SIGNAL ;
    PORT
      LAYER M5 ;
        RECT 73.824 217.968 73.848 218.160 ;
    END
  END ib[266]
  PIN ib[267]
    DIRECTION INPUT ;
    USE SIGNAL ;
    PORT
      LAYER M5 ;
        RECT 74.064 217.968 74.088 218.160 ;
    END
  END ib[267]
  PIN ib[268]
    DIRECTION INPUT ;
    USE SIGNAL ;
    PORT
      LAYER M5 ;
        RECT 74.352 217.968 74.376 218.160 ;
    END
  END ib[268]
  PIN ib[269]
    DIRECTION INPUT ;
    USE SIGNAL ;
    PORT
      LAYER M5 ;
        RECT 74.592 217.968 74.616 218.160 ;
    END
  END ib[269]
  PIN ib[270]
    DIRECTION INPUT ;
    USE SIGNAL ;
    PORT
      LAYER M5 ;
        RECT 74.832 217.968 74.856 218.160 ;
    END
  END ib[270]
  PIN ib[271]
    DIRECTION INPUT ;
    USE SIGNAL ;
    PORT
      LAYER M5 ;
        RECT 75.120 217.968 75.144 218.160 ;
    END
  END ib[271]
  PIN ib[272]
    DIRECTION INPUT ;
    USE SIGNAL ;
    PORT
      LAYER M5 ;
        RECT 75.360 217.968 75.384 218.160 ;
    END
  END ib[272]
  PIN ib[273]
    DIRECTION INPUT ;
    USE SIGNAL ;
    PORT
      LAYER M5 ;
        RECT 75.600 217.968 75.624 218.160 ;
    END
  END ib[273]
  PIN ib[274]
    DIRECTION INPUT ;
    USE SIGNAL ;
    PORT
      LAYER M5 ;
        RECT 75.888 217.968 75.912 218.160 ;
    END
  END ib[274]
  PIN ib[275]
    DIRECTION INPUT ;
    USE SIGNAL ;
    PORT
      LAYER M5 ;
        RECT 76.128 217.968 76.152 218.160 ;
    END
  END ib[275]
  PIN ib[276]
    DIRECTION INPUT ;
    USE SIGNAL ;
    PORT
      LAYER M5 ;
        RECT 76.368 217.968 76.392 218.160 ;
    END
  END ib[276]
  PIN ib[277]
    DIRECTION INPUT ;
    USE SIGNAL ;
    PORT
      LAYER M5 ;
        RECT 76.656 217.968 76.680 218.160 ;
    END
  END ib[277]
  PIN ib[278]
    DIRECTION INPUT ;
    USE SIGNAL ;
    PORT
      LAYER M5 ;
        RECT 76.896 217.968 76.920 218.160 ;
    END
  END ib[278]
  PIN ib[279]
    DIRECTION INPUT ;
    USE SIGNAL ;
    PORT
      LAYER M5 ;
        RECT 77.136 217.968 77.160 218.160 ;
    END
  END ib[279]
  PIN ib[280]
    DIRECTION INPUT ;
    USE SIGNAL ;
    PORT
      LAYER M5 ;
        RECT 77.424 217.968 77.448 218.160 ;
    END
  END ib[280]
  PIN ib[281]
    DIRECTION INPUT ;
    USE SIGNAL ;
    PORT
      LAYER M5 ;
        RECT 77.664 217.968 77.688 218.160 ;
    END
  END ib[281]
  PIN ib[282]
    DIRECTION INPUT ;
    USE SIGNAL ;
    PORT
      LAYER M5 ;
        RECT 77.952 217.968 77.976 218.160 ;
    END
  END ib[282]
  PIN ib[283]
    DIRECTION INPUT ;
    USE SIGNAL ;
    PORT
      LAYER M5 ;
        RECT 78.192 217.968 78.216 218.160 ;
    END
  END ib[283]
  PIN ib[284]
    DIRECTION INPUT ;
    USE SIGNAL ;
    PORT
      LAYER M5 ;
        RECT 78.432 217.968 78.456 218.160 ;
    END
  END ib[284]
  PIN ib[285]
    DIRECTION INPUT ;
    USE SIGNAL ;
    PORT
      LAYER M5 ;
        RECT 78.720 217.968 78.744 218.160 ;
    END
  END ib[285]
  PIN ib[286]
    DIRECTION INPUT ;
    USE SIGNAL ;
    PORT
      LAYER M5 ;
        RECT 78.960 217.968 78.984 218.160 ;
    END
  END ib[286]
  PIN ib[287]
    DIRECTION INPUT ;
    USE SIGNAL ;
    PORT
      LAYER M5 ;
        RECT 79.200 217.968 79.224 218.160 ;
    END
  END ib[287]
  PIN ib[288]
    DIRECTION INPUT ;
    USE SIGNAL ;
    PORT
      LAYER M5 ;
        RECT 79.488 217.968 79.512 218.160 ;
    END
  END ib[288]
  PIN ib[289]
    DIRECTION INPUT ;
    USE SIGNAL ;
    PORT
      LAYER M5 ;
        RECT 79.728 217.968 79.752 218.160 ;
    END
  END ib[289]
  PIN ib[290]
    DIRECTION INPUT ;
    USE SIGNAL ;
    PORT
      LAYER M5 ;
        RECT 79.968 217.968 79.992 218.160 ;
    END
  END ib[290]
  PIN ib[291]
    DIRECTION INPUT ;
    USE SIGNAL ;
    PORT
      LAYER M5 ;
        RECT 80.256 217.968 80.280 218.160 ;
    END
  END ib[291]
  PIN ib[292]
    DIRECTION INPUT ;
    USE SIGNAL ;
    PORT
      LAYER M5 ;
        RECT 80.496 217.968 80.520 218.160 ;
    END
  END ib[292]
  PIN ib[293]
    DIRECTION INPUT ;
    USE SIGNAL ;
    PORT
      LAYER M5 ;
        RECT 80.736 217.968 80.760 218.160 ;
    END
  END ib[293]
  PIN ib[294]
    DIRECTION INPUT ;
    USE SIGNAL ;
    PORT
      LAYER M5 ;
        RECT 81.024 217.968 81.048 218.160 ;
    END
  END ib[294]
  PIN ib[295]
    DIRECTION INPUT ;
    USE SIGNAL ;
    PORT
      LAYER M5 ;
        RECT 81.264 217.968 81.288 218.160 ;
    END
  END ib[295]
  PIN ib[296]
    DIRECTION INPUT ;
    USE SIGNAL ;
    PORT
      LAYER M5 ;
        RECT 81.504 217.968 81.528 218.160 ;
    END
  END ib[296]
  PIN ib[297]
    DIRECTION INPUT ;
    USE SIGNAL ;
    PORT
      LAYER M5 ;
        RECT 81.792 217.968 81.816 218.160 ;
    END
  END ib[297]
  PIN ib[298]
    DIRECTION INPUT ;
    USE SIGNAL ;
    PORT
      LAYER M5 ;
        RECT 82.032 217.968 82.056 218.160 ;
    END
  END ib[298]
  PIN ib[299]
    DIRECTION INPUT ;
    USE SIGNAL ;
    PORT
      LAYER M5 ;
        RECT 82.320 217.968 82.344 218.160 ;
    END
  END ib[299]
  PIN ib[300]
    DIRECTION INPUT ;
    USE SIGNAL ;
    PORT
      LAYER M5 ;
        RECT 82.560 217.968 82.584 218.160 ;
    END
  END ib[300]
  PIN ib[301]
    DIRECTION INPUT ;
    USE SIGNAL ;
    PORT
      LAYER M5 ;
        RECT 82.800 217.968 82.824 218.160 ;
    END
  END ib[301]
  PIN ib[302]
    DIRECTION INPUT ;
    USE SIGNAL ;
    PORT
      LAYER M5 ;
        RECT 83.088 217.968 83.112 218.160 ;
    END
  END ib[302]
  PIN ib[303]
    DIRECTION INPUT ;
    USE SIGNAL ;
    PORT
      LAYER M5 ;
        RECT 83.328 217.968 83.352 218.160 ;
    END
  END ib[303]
  PIN ib[304]
    DIRECTION INPUT ;
    USE SIGNAL ;
    PORT
      LAYER M5 ;
        RECT 83.568 217.968 83.592 218.160 ;
    END
  END ib[304]
  PIN ib[305]
    DIRECTION INPUT ;
    USE SIGNAL ;
    PORT
      LAYER M5 ;
        RECT 83.856 217.968 83.880 218.160 ;
    END
  END ib[305]
  PIN ib[306]
    DIRECTION INPUT ;
    USE SIGNAL ;
    PORT
      LAYER M5 ;
        RECT 84.096 217.968 84.120 218.160 ;
    END
  END ib[306]
  PIN ib[307]
    DIRECTION INPUT ;
    USE SIGNAL ;
    PORT
      LAYER M5 ;
        RECT 84.336 217.968 84.360 218.160 ;
    END
  END ib[307]
  PIN ib[308]
    DIRECTION INPUT ;
    USE SIGNAL ;
    PORT
      LAYER M5 ;
        RECT 84.624 217.968 84.648 218.160 ;
    END
  END ib[308]
  PIN ib[309]
    DIRECTION INPUT ;
    USE SIGNAL ;
    PORT
      LAYER M5 ;
        RECT 84.864 217.968 84.888 218.160 ;
    END
  END ib[309]
  PIN ib[310]
    DIRECTION INPUT ;
    USE SIGNAL ;
    PORT
      LAYER M5 ;
        RECT 85.104 217.968 85.128 218.160 ;
    END
  END ib[310]
  PIN ib[311]
    DIRECTION INPUT ;
    USE SIGNAL ;
    PORT
      LAYER M5 ;
        RECT 85.392 217.968 85.416 218.160 ;
    END
  END ib[311]
  PIN ib[312]
    DIRECTION INPUT ;
    USE SIGNAL ;
    PORT
      LAYER M5 ;
        RECT 85.632 217.968 85.656 218.160 ;
    END
  END ib[312]
  PIN ib[313]
    DIRECTION INPUT ;
    USE SIGNAL ;
    PORT
      LAYER M5 ;
        RECT 85.872 217.968 85.896 218.160 ;
    END
  END ib[313]
  PIN ib[314]
    DIRECTION INPUT ;
    USE SIGNAL ;
    PORT
      LAYER M5 ;
        RECT 86.160 217.968 86.184 218.160 ;
    END
  END ib[314]
  PIN ib[315]
    DIRECTION INPUT ;
    USE SIGNAL ;
    PORT
      LAYER M5 ;
        RECT 86.400 217.968 86.424 218.160 ;
    END
  END ib[315]
  PIN ib[316]
    DIRECTION INPUT ;
    USE SIGNAL ;
    PORT
      LAYER M5 ;
        RECT 86.688 217.968 86.712 218.160 ;
    END
  END ib[316]
  PIN ib[317]
    DIRECTION INPUT ;
    USE SIGNAL ;
    PORT
      LAYER M5 ;
        RECT 86.928 217.968 86.952 218.160 ;
    END
  END ib[317]
  PIN ib[318]
    DIRECTION INPUT ;
    USE SIGNAL ;
    PORT
      LAYER M5 ;
        RECT 87.168 217.968 87.192 218.160 ;
    END
  END ib[318]
  PIN ib[319]
    DIRECTION INPUT ;
    USE SIGNAL ;
    PORT
      LAYER M5 ;
        RECT 87.456 217.968 87.480 218.160 ;
    END
  END ib[319]
  PIN ib[320]
    DIRECTION INPUT ;
    USE SIGNAL ;
    PORT
      LAYER M5 ;
        RECT 87.696 217.968 87.720 218.160 ;
    END
  END ib[320]
  PIN ib[321]
    DIRECTION INPUT ;
    USE SIGNAL ;
    PORT
      LAYER M5 ;
        RECT 87.936 217.968 87.960 218.160 ;
    END
  END ib[321]
  PIN ib[322]
    DIRECTION INPUT ;
    USE SIGNAL ;
    PORT
      LAYER M5 ;
        RECT 88.224 217.968 88.248 218.160 ;
    END
  END ib[322]
  PIN ib[323]
    DIRECTION INPUT ;
    USE SIGNAL ;
    PORT
      LAYER M5 ;
        RECT 88.464 217.968 88.488 218.160 ;
    END
  END ib[323]
  PIN ib[324]
    DIRECTION INPUT ;
    USE SIGNAL ;
    PORT
      LAYER M5 ;
        RECT 88.704 217.968 88.728 218.160 ;
    END
  END ib[324]
  PIN ib[325]
    DIRECTION INPUT ;
    USE SIGNAL ;
    PORT
      LAYER M5 ;
        RECT 88.992 217.968 89.016 218.160 ;
    END
  END ib[325]
  PIN ib[326]
    DIRECTION INPUT ;
    USE SIGNAL ;
    PORT
      LAYER M5 ;
        RECT 89.232 217.968 89.256 218.160 ;
    END
  END ib[326]
  PIN ib[327]
    DIRECTION INPUT ;
    USE SIGNAL ;
    PORT
      LAYER M5 ;
        RECT 89.472 217.968 89.496 218.160 ;
    END
  END ib[327]
  PIN ib[328]
    DIRECTION INPUT ;
    USE SIGNAL ;
    PORT
      LAYER M5 ;
        RECT 89.760 217.968 89.784 218.160 ;
    END
  END ib[328]
  PIN ib[329]
    DIRECTION INPUT ;
    USE SIGNAL ;
    PORT
      LAYER M5 ;
        RECT 90.000 217.968 90.024 218.160 ;
    END
  END ib[329]
  PIN ib[330]
    DIRECTION INPUT ;
    USE SIGNAL ;
    PORT
      LAYER M5 ;
        RECT 90.240 217.968 90.264 218.160 ;
    END
  END ib[330]
  PIN ib[331]
    DIRECTION INPUT ;
    USE SIGNAL ;
    PORT
      LAYER M5 ;
        RECT 90.528 217.968 90.552 218.160 ;
    END
  END ib[331]
  PIN ib[332]
    DIRECTION INPUT ;
    USE SIGNAL ;
    PORT
      LAYER M5 ;
        RECT 90.768 217.968 90.792 218.160 ;
    END
  END ib[332]
  PIN ib[333]
    DIRECTION INPUT ;
    USE SIGNAL ;
    PORT
      LAYER M5 ;
        RECT 91.056 217.968 91.080 218.160 ;
    END
  END ib[333]
  PIN ib[334]
    DIRECTION INPUT ;
    USE SIGNAL ;
    PORT
      LAYER M5 ;
        RECT 91.296 217.968 91.320 218.160 ;
    END
  END ib[334]
  PIN ib[335]
    DIRECTION INPUT ;
    USE SIGNAL ;
    PORT
      LAYER M5 ;
        RECT 91.536 217.968 91.560 218.160 ;
    END
  END ib[335]
  PIN ib[336]
    DIRECTION INPUT ;
    USE SIGNAL ;
    PORT
      LAYER M5 ;
        RECT 91.824 217.968 91.848 218.160 ;
    END
  END ib[336]
  PIN ib[337]
    DIRECTION INPUT ;
    USE SIGNAL ;
    PORT
      LAYER M5 ;
        RECT 92.064 217.968 92.088 218.160 ;
    END
  END ib[337]
  PIN ib[338]
    DIRECTION INPUT ;
    USE SIGNAL ;
    PORT
      LAYER M5 ;
        RECT 92.304 217.968 92.328 218.160 ;
    END
  END ib[338]
  PIN ib[339]
    DIRECTION INPUT ;
    USE SIGNAL ;
    PORT
      LAYER M5 ;
        RECT 92.592 217.968 92.616 218.160 ;
    END
  END ib[339]
  PIN ib[340]
    DIRECTION INPUT ;
    USE SIGNAL ;
    PORT
      LAYER M5 ;
        RECT 92.832 217.968 92.856 218.160 ;
    END
  END ib[340]
  PIN ib[341]
    DIRECTION INPUT ;
    USE SIGNAL ;
    PORT
      LAYER M5 ;
        RECT 93.072 217.968 93.096 218.160 ;
    END
  END ib[341]
  PIN ib[342]
    DIRECTION INPUT ;
    USE SIGNAL ;
    PORT
      LAYER M5 ;
        RECT 93.360 217.968 93.384 218.160 ;
    END
  END ib[342]
  PIN ib[343]
    DIRECTION INPUT ;
    USE SIGNAL ;
    PORT
      LAYER M5 ;
        RECT 93.600 217.968 93.624 218.160 ;
    END
  END ib[343]
  PIN ib[344]
    DIRECTION INPUT ;
    USE SIGNAL ;
    PORT
      LAYER M5 ;
        RECT 93.840 217.968 93.864 218.160 ;
    END
  END ib[344]
  PIN ib[345]
    DIRECTION INPUT ;
    USE SIGNAL ;
    PORT
      LAYER M5 ;
        RECT 94.128 217.968 94.152 218.160 ;
    END
  END ib[345]
  PIN ib[346]
    DIRECTION INPUT ;
    USE SIGNAL ;
    PORT
      LAYER M5 ;
        RECT 94.368 217.968 94.392 218.160 ;
    END
  END ib[346]
  PIN ib[347]
    DIRECTION INPUT ;
    USE SIGNAL ;
    PORT
      LAYER M5 ;
        RECT 94.608 217.968 94.632 218.160 ;
    END
  END ib[347]
  PIN ib[348]
    DIRECTION INPUT ;
    USE SIGNAL ;
    PORT
      LAYER M5 ;
        RECT 94.896 217.968 94.920 218.160 ;
    END
  END ib[348]
  PIN ib[349]
    DIRECTION INPUT ;
    USE SIGNAL ;
    PORT
      LAYER M5 ;
        RECT 95.136 217.968 95.160 218.160 ;
    END
  END ib[349]
  PIN ib[350]
    DIRECTION INPUT ;
    USE SIGNAL ;
    PORT
      LAYER M5 ;
        RECT 95.424 217.968 95.448 218.160 ;
    END
  END ib[350]
  PIN ib[351]
    DIRECTION INPUT ;
    USE SIGNAL ;
    PORT
      LAYER M5 ;
        RECT 95.664 217.968 95.688 218.160 ;
    END
  END ib[351]
  PIN ib[352]
    DIRECTION INPUT ;
    USE SIGNAL ;
    PORT
      LAYER M5 ;
        RECT 95.904 217.968 95.928 218.160 ;
    END
  END ib[352]
  PIN ib[353]
    DIRECTION INPUT ;
    USE SIGNAL ;
    PORT
      LAYER M5 ;
        RECT 96.192 217.968 96.216 218.160 ;
    END
  END ib[353]
  PIN ib[354]
    DIRECTION INPUT ;
    USE SIGNAL ;
    PORT
      LAYER M5 ;
        RECT 96.432 217.968 96.456 218.160 ;
    END
  END ib[354]
  PIN ib[355]
    DIRECTION INPUT ;
    USE SIGNAL ;
    PORT
      LAYER M5 ;
        RECT 96.672 217.968 96.696 218.160 ;
    END
  END ib[355]
  PIN ib[356]
    DIRECTION INPUT ;
    USE SIGNAL ;
    PORT
      LAYER M5 ;
        RECT 96.960 217.968 96.984 218.160 ;
    END
  END ib[356]
  PIN ib[357]
    DIRECTION INPUT ;
    USE SIGNAL ;
    PORT
      LAYER M5 ;
        RECT 97.200 217.968 97.224 218.160 ;
    END
  END ib[357]
  PIN ib[358]
    DIRECTION INPUT ;
    USE SIGNAL ;
    PORT
      LAYER M5 ;
        RECT 97.440 217.968 97.464 218.160 ;
    END
  END ib[358]
  PIN ib[359]
    DIRECTION INPUT ;
    USE SIGNAL ;
    PORT
      LAYER M5 ;
        RECT 97.728 217.968 97.752 218.160 ;
    END
  END ib[359]
  PIN ib[360]
    DIRECTION INPUT ;
    USE SIGNAL ;
    PORT
      LAYER M5 ;
        RECT 97.968 217.968 97.992 218.160 ;
    END
  END ib[360]
  PIN ib[361]
    DIRECTION INPUT ;
    USE SIGNAL ;
    PORT
      LAYER M5 ;
        RECT 98.208 217.968 98.232 218.160 ;
    END
  END ib[361]
  PIN ib[362]
    DIRECTION INPUT ;
    USE SIGNAL ;
    PORT
      LAYER M5 ;
        RECT 98.496 217.968 98.520 218.160 ;
    END
  END ib[362]
  PIN ib[363]
    DIRECTION INPUT ;
    USE SIGNAL ;
    PORT
      LAYER M5 ;
        RECT 98.736 217.968 98.760 218.160 ;
    END
  END ib[363]
  PIN ib[364]
    DIRECTION INPUT ;
    USE SIGNAL ;
    PORT
      LAYER M5 ;
        RECT 98.976 217.968 99.000 218.160 ;
    END
  END ib[364]
  PIN ib[365]
    DIRECTION INPUT ;
    USE SIGNAL ;
    PORT
      LAYER M5 ;
        RECT 99.264 217.968 99.288 218.160 ;
    END
  END ib[365]
  PIN ib[366]
    DIRECTION INPUT ;
    USE SIGNAL ;
    PORT
      LAYER M5 ;
        RECT 99.504 217.968 99.528 218.160 ;
    END
  END ib[366]
  PIN ib[367]
    DIRECTION INPUT ;
    USE SIGNAL ;
    PORT
      LAYER M5 ;
        RECT 99.792 217.968 99.816 218.160 ;
    END
  END ib[367]
  PIN ib[368]
    DIRECTION INPUT ;
    USE SIGNAL ;
    PORT
      LAYER M5 ;
        RECT 100.032 217.968 100.056 218.160 ;
    END
  END ib[368]
  PIN ib[369]
    DIRECTION INPUT ;
    USE SIGNAL ;
    PORT
      LAYER M5 ;
        RECT 100.272 217.968 100.296 218.160 ;
    END
  END ib[369]
  PIN ib[370]
    DIRECTION INPUT ;
    USE SIGNAL ;
    PORT
      LAYER M5 ;
        RECT 100.560 217.968 100.584 218.160 ;
    END
  END ib[370]
  PIN ib[371]
    DIRECTION INPUT ;
    USE SIGNAL ;
    PORT
      LAYER M5 ;
        RECT 100.800 217.968 100.824 218.160 ;
    END
  END ib[371]
  PIN ib[372]
    DIRECTION INPUT ;
    USE SIGNAL ;
    PORT
      LAYER M5 ;
        RECT 101.040 217.968 101.064 218.160 ;
    END
  END ib[372]
  PIN ib[373]
    DIRECTION INPUT ;
    USE SIGNAL ;
    PORT
      LAYER M5 ;
        RECT 101.328 217.968 101.352 218.160 ;
    END
  END ib[373]
  PIN ib[374]
    DIRECTION INPUT ;
    USE SIGNAL ;
    PORT
      LAYER M5 ;
        RECT 101.568 217.968 101.592 218.160 ;
    END
  END ib[374]
  PIN ib[375]
    DIRECTION INPUT ;
    USE SIGNAL ;
    PORT
      LAYER M5 ;
        RECT 101.808 217.968 101.832 218.160 ;
    END
  END ib[375]
  PIN ib[376]
    DIRECTION INPUT ;
    USE SIGNAL ;
    PORT
      LAYER M5 ;
        RECT 102.096 217.968 102.120 218.160 ;
    END
  END ib[376]
  PIN ib[377]
    DIRECTION INPUT ;
    USE SIGNAL ;
    PORT
      LAYER M5 ;
        RECT 102.336 217.968 102.360 218.160 ;
    END
  END ib[377]
  PIN ib[378]
    DIRECTION INPUT ;
    USE SIGNAL ;
    PORT
      LAYER M5 ;
        RECT 102.576 217.968 102.600 218.160 ;
    END
  END ib[378]
  PIN ib[379]
    DIRECTION INPUT ;
    USE SIGNAL ;
    PORT
      LAYER M5 ;
        RECT 102.864 217.968 102.888 218.160 ;
    END
  END ib[379]
  PIN ib[380]
    DIRECTION INPUT ;
    USE SIGNAL ;
    PORT
      LAYER M5 ;
        RECT 103.104 217.968 103.128 218.160 ;
    END
  END ib[380]
  PIN ib[381]
    DIRECTION INPUT ;
    USE SIGNAL ;
    PORT
      LAYER M5 ;
        RECT 103.392 217.968 103.416 218.160 ;
    END
  END ib[381]
  PIN ib[382]
    DIRECTION INPUT ;
    USE SIGNAL ;
    PORT
      LAYER M5 ;
        RECT 103.632 217.968 103.656 218.160 ;
    END
  END ib[382]
  PIN ib[383]
    DIRECTION INPUT ;
    USE SIGNAL ;
    PORT
      LAYER M5 ;
        RECT 103.872 217.968 103.896 218.160 ;
    END
  END ib[383]
  PIN ib[384]
    DIRECTION INPUT ;
    USE SIGNAL ;
    PORT
      LAYER M5 ;
        RECT 104.160 217.968 104.184 218.160 ;
    END
  END ib[384]
  PIN ib[385]
    DIRECTION INPUT ;
    USE SIGNAL ;
    PORT
      LAYER M5 ;
        RECT 104.400 217.968 104.424 218.160 ;
    END
  END ib[385]
  PIN ib[386]
    DIRECTION INPUT ;
    USE SIGNAL ;
    PORT
      LAYER M5 ;
        RECT 104.640 217.968 104.664 218.160 ;
    END
  END ib[386]
  PIN ib[387]
    DIRECTION INPUT ;
    USE SIGNAL ;
    PORT
      LAYER M5 ;
        RECT 104.928 217.968 104.952 218.160 ;
    END
  END ib[387]
  PIN ib[388]
    DIRECTION INPUT ;
    USE SIGNAL ;
    PORT
      LAYER M5 ;
        RECT 105.168 217.968 105.192 218.160 ;
    END
  END ib[388]
  PIN ib[389]
    DIRECTION INPUT ;
    USE SIGNAL ;
    PORT
      LAYER M5 ;
        RECT 105.408 217.968 105.432 218.160 ;
    END
  END ib[389]
  PIN ib[390]
    DIRECTION INPUT ;
    USE SIGNAL ;
    PORT
      LAYER M5 ;
        RECT 105.696 217.968 105.720 218.160 ;
    END
  END ib[390]
  PIN ib[391]
    DIRECTION INPUT ;
    USE SIGNAL ;
    PORT
      LAYER M5 ;
        RECT 105.936 217.968 105.960 218.160 ;
    END
  END ib[391]
  PIN ib[392]
    DIRECTION INPUT ;
    USE SIGNAL ;
    PORT
      LAYER M5 ;
        RECT 106.176 217.968 106.200 218.160 ;
    END
  END ib[392]
  PIN ib[393]
    DIRECTION INPUT ;
    USE SIGNAL ;
    PORT
      LAYER M5 ;
        RECT 106.464 217.968 106.488 218.160 ;
    END
  END ib[393]
  PIN ib[394]
    DIRECTION INPUT ;
    USE SIGNAL ;
    PORT
      LAYER M5 ;
        RECT 106.704 217.968 106.728 218.160 ;
    END
  END ib[394]
  PIN ib[395]
    DIRECTION INPUT ;
    USE SIGNAL ;
    PORT
      LAYER M5 ;
        RECT 106.944 217.968 106.968 218.160 ;
    END
  END ib[395]
  PIN ib[396]
    DIRECTION INPUT ;
    USE SIGNAL ;
    PORT
      LAYER M5 ;
        RECT 107.232 217.968 107.256 218.160 ;
    END
  END ib[396]
  PIN ib[397]
    DIRECTION INPUT ;
    USE SIGNAL ;
    PORT
      LAYER M5 ;
        RECT 107.472 217.968 107.496 218.160 ;
    END
  END ib[397]
  PIN ib[398]
    DIRECTION INPUT ;
    USE SIGNAL ;
    PORT
      LAYER M5 ;
        RECT 107.760 217.968 107.784 218.160 ;
    END
  END ib[398]
  PIN ib[399]
    DIRECTION INPUT ;
    USE SIGNAL ;
    PORT
      LAYER M5 ;
        RECT 108.000 217.968 108.024 218.160 ;
    END
  END ib[399]
  PIN ib[400]
    DIRECTION INPUT ;
    USE SIGNAL ;
    PORT
      LAYER M5 ;
        RECT 108.240 217.968 108.264 218.160 ;
    END
  END ib[400]
  PIN ib[401]
    DIRECTION INPUT ;
    USE SIGNAL ;
    PORT
      LAYER M5 ;
        RECT 108.528 217.968 108.552 218.160 ;
    END
  END ib[401]
  PIN ib[402]
    DIRECTION INPUT ;
    USE SIGNAL ;
    PORT
      LAYER M5 ;
        RECT 108.768 217.968 108.792 218.160 ;
    END
  END ib[402]
  PIN ib[403]
    DIRECTION INPUT ;
    USE SIGNAL ;
    PORT
      LAYER M5 ;
        RECT 109.008 217.968 109.032 218.160 ;
    END
  END ib[403]
  PIN ib[404]
    DIRECTION INPUT ;
    USE SIGNAL ;
    PORT
      LAYER M5 ;
        RECT 109.296 217.968 109.320 218.160 ;
    END
  END ib[404]
  PIN ib[405]
    DIRECTION INPUT ;
    USE SIGNAL ;
    PORT
      LAYER M5 ;
        RECT 109.536 217.968 109.560 218.160 ;
    END
  END ib[405]
  PIN ib[406]
    DIRECTION INPUT ;
    USE SIGNAL ;
    PORT
      LAYER M5 ;
        RECT 109.776 217.968 109.800 218.160 ;
    END
  END ib[406]
  PIN ib[407]
    DIRECTION INPUT ;
    USE SIGNAL ;
    PORT
      LAYER M5 ;
        RECT 110.064 217.968 110.088 218.160 ;
    END
  END ib[407]
  PIN ib[408]
    DIRECTION INPUT ;
    USE SIGNAL ;
    PORT
      LAYER M5 ;
        RECT 110.304 217.968 110.328 218.160 ;
    END
  END ib[408]
  PIN ib[409]
    DIRECTION INPUT ;
    USE SIGNAL ;
    PORT
      LAYER M5 ;
        RECT 110.544 217.968 110.568 218.160 ;
    END
  END ib[409]
  PIN ib[410]
    DIRECTION INPUT ;
    USE SIGNAL ;
    PORT
      LAYER M5 ;
        RECT 110.832 217.968 110.856 218.160 ;
    END
  END ib[410]
  PIN ib[411]
    DIRECTION INPUT ;
    USE SIGNAL ;
    PORT
      LAYER M5 ;
        RECT 111.072 217.968 111.096 218.160 ;
    END
  END ib[411]
  PIN ib[412]
    DIRECTION INPUT ;
    USE SIGNAL ;
    PORT
      LAYER M5 ;
        RECT 111.312 217.968 111.336 218.160 ;
    END
  END ib[412]
  PIN ib[413]
    DIRECTION INPUT ;
    USE SIGNAL ;
    PORT
      LAYER M5 ;
        RECT 111.600 217.968 111.624 218.160 ;
    END
  END ib[413]
  PIN ib[414]
    DIRECTION INPUT ;
    USE SIGNAL ;
    PORT
      LAYER M5 ;
        RECT 111.840 217.968 111.864 218.160 ;
    END
  END ib[414]
  PIN ib[415]
    DIRECTION INPUT ;
    USE SIGNAL ;
    PORT
      LAYER M5 ;
        RECT 112.128 217.968 112.152 218.160 ;
    END
  END ib[415]
  PIN ib[416]
    DIRECTION INPUT ;
    USE SIGNAL ;
    PORT
      LAYER M5 ;
        RECT 112.368 217.968 112.392 218.160 ;
    END
  END ib[416]
  PIN ib[417]
    DIRECTION INPUT ;
    USE SIGNAL ;
    PORT
      LAYER M5 ;
        RECT 112.608 217.968 112.632 218.160 ;
    END
  END ib[417]
  PIN ib[418]
    DIRECTION INPUT ;
    USE SIGNAL ;
    PORT
      LAYER M5 ;
        RECT 112.896 217.968 112.920 218.160 ;
    END
  END ib[418]
  PIN ib[419]
    DIRECTION INPUT ;
    USE SIGNAL ;
    PORT
      LAYER M5 ;
        RECT 113.136 217.968 113.160 218.160 ;
    END
  END ib[419]
  PIN ib[420]
    DIRECTION INPUT ;
    USE SIGNAL ;
    PORT
      LAYER M5 ;
        RECT 113.376 217.968 113.400 218.160 ;
    END
  END ib[420]
  PIN ib[421]
    DIRECTION INPUT ;
    USE SIGNAL ;
    PORT
      LAYER M5 ;
        RECT 113.664 217.968 113.688 218.160 ;
    END
  END ib[421]
  PIN ib[422]
    DIRECTION INPUT ;
    USE SIGNAL ;
    PORT
      LAYER M5 ;
        RECT 113.904 217.968 113.928 218.160 ;
    END
  END ib[422]
  PIN ib[423]
    DIRECTION INPUT ;
    USE SIGNAL ;
    PORT
      LAYER M5 ;
        RECT 114.144 217.968 114.168 218.160 ;
    END
  END ib[423]
  PIN ib[424]
    DIRECTION INPUT ;
    USE SIGNAL ;
    PORT
      LAYER M5 ;
        RECT 114.432 217.968 114.456 218.160 ;
    END
  END ib[424]
  PIN ib[425]
    DIRECTION INPUT ;
    USE SIGNAL ;
    PORT
      LAYER M5 ;
        RECT 114.672 217.968 114.696 218.160 ;
    END
  END ib[425]
  PIN ib[426]
    DIRECTION INPUT ;
    USE SIGNAL ;
    PORT
      LAYER M5 ;
        RECT 114.912 217.968 114.936 218.160 ;
    END
  END ib[426]
  PIN ib[427]
    DIRECTION INPUT ;
    USE SIGNAL ;
    PORT
      LAYER M5 ;
        RECT 115.200 217.968 115.224 218.160 ;
    END
  END ib[427]
  PIN ib[428]
    DIRECTION INPUT ;
    USE SIGNAL ;
    PORT
      LAYER M5 ;
        RECT 115.440 217.968 115.464 218.160 ;
    END
  END ib[428]
  PIN ib[429]
    DIRECTION INPUT ;
    USE SIGNAL ;
    PORT
      LAYER M5 ;
        RECT 115.680 217.968 115.704 218.160 ;
    END
  END ib[429]
  PIN ib[430]
    DIRECTION INPUT ;
    USE SIGNAL ;
    PORT
      LAYER M5 ;
        RECT 115.968 217.968 115.992 218.160 ;
    END
  END ib[430]
  PIN ib[431]
    DIRECTION INPUT ;
    USE SIGNAL ;
    PORT
      LAYER M5 ;
        RECT 116.208 217.968 116.232 218.160 ;
    END
  END ib[431]
  PIN ib[432]
    DIRECTION INPUT ;
    USE SIGNAL ;
    PORT
      LAYER M5 ;
        RECT 116.496 217.968 116.520 218.160 ;
    END
  END ib[432]
  PIN ib[433]
    DIRECTION INPUT ;
    USE SIGNAL ;
    PORT
      LAYER M5 ;
        RECT 116.736 217.968 116.760 218.160 ;
    END
  END ib[433]
  PIN ib[434]
    DIRECTION INPUT ;
    USE SIGNAL ;
    PORT
      LAYER M5 ;
        RECT 116.976 217.968 117.000 218.160 ;
    END
  END ib[434]
  PIN ib[435]
    DIRECTION INPUT ;
    USE SIGNAL ;
    PORT
      LAYER M5 ;
        RECT 117.264 217.968 117.288 218.160 ;
    END
  END ib[435]
  PIN ib[436]
    DIRECTION INPUT ;
    USE SIGNAL ;
    PORT
      LAYER M5 ;
        RECT 117.504 217.968 117.528 218.160 ;
    END
  END ib[436]
  PIN ib[437]
    DIRECTION INPUT ;
    USE SIGNAL ;
    PORT
      LAYER M5 ;
        RECT 117.744 217.968 117.768 218.160 ;
    END
  END ib[437]
  PIN ib[438]
    DIRECTION INPUT ;
    USE SIGNAL ;
    PORT
      LAYER M5 ;
        RECT 118.032 217.968 118.056 218.160 ;
    END
  END ib[438]
  PIN ib[439]
    DIRECTION INPUT ;
    USE SIGNAL ;
    PORT
      LAYER M5 ;
        RECT 118.272 217.968 118.296 218.160 ;
    END
  END ib[439]
  PIN ib[440]
    DIRECTION INPUT ;
    USE SIGNAL ;
    PORT
      LAYER M5 ;
        RECT 118.512 217.968 118.536 218.160 ;
    END
  END ib[440]
  PIN ib[441]
    DIRECTION INPUT ;
    USE SIGNAL ;
    PORT
      LAYER M5 ;
        RECT 118.800 217.968 118.824 218.160 ;
    END
  END ib[441]
  PIN ib[442]
    DIRECTION INPUT ;
    USE SIGNAL ;
    PORT
      LAYER M5 ;
        RECT 119.040 217.968 119.064 218.160 ;
    END
  END ib[442]
  PIN ib[443]
    DIRECTION INPUT ;
    USE SIGNAL ;
    PORT
      LAYER M5 ;
        RECT 119.280 217.968 119.304 218.160 ;
    END
  END ib[443]
  PIN ib[444]
    DIRECTION INPUT ;
    USE SIGNAL ;
    PORT
      LAYER M5 ;
        RECT 119.568 217.968 119.592 218.160 ;
    END
  END ib[444]
  PIN ib[445]
    DIRECTION INPUT ;
    USE SIGNAL ;
    PORT
      LAYER M5 ;
        RECT 119.808 217.968 119.832 218.160 ;
    END
  END ib[445]
  PIN ib[446]
    DIRECTION INPUT ;
    USE SIGNAL ;
    PORT
      LAYER M5 ;
        RECT 120.048 217.968 120.072 218.160 ;
    END
  END ib[446]
  PIN ib[447]
    DIRECTION INPUT ;
    USE SIGNAL ;
    PORT
      LAYER M5 ;
        RECT 120.336 217.968 120.360 218.160 ;
    END
  END ib[447]
  PIN ib[448]
    DIRECTION INPUT ;
    USE SIGNAL ;
    PORT
      LAYER M5 ;
        RECT 120.576 217.968 120.600 218.160 ;
    END
  END ib[448]
  PIN ib[449]
    DIRECTION INPUT ;
    USE SIGNAL ;
    PORT
      LAYER M5 ;
        RECT 120.864 217.968 120.888 218.160 ;
    END
  END ib[449]
  PIN ib[450]
    DIRECTION INPUT ;
    USE SIGNAL ;
    PORT
      LAYER M5 ;
        RECT 121.104 217.968 121.128 218.160 ;
    END
  END ib[450]
  PIN ib[451]
    DIRECTION INPUT ;
    USE SIGNAL ;
    PORT
      LAYER M5 ;
        RECT 121.344 217.968 121.368 218.160 ;
    END
  END ib[451]
  PIN ib[452]
    DIRECTION INPUT ;
    USE SIGNAL ;
    PORT
      LAYER M5 ;
        RECT 121.632 217.968 121.656 218.160 ;
    END
  END ib[452]
  PIN ib[453]
    DIRECTION INPUT ;
    USE SIGNAL ;
    PORT
      LAYER M5 ;
        RECT 121.872 217.968 121.896 218.160 ;
    END
  END ib[453]
  PIN ib[454]
    DIRECTION INPUT ;
    USE SIGNAL ;
    PORT
      LAYER M5 ;
        RECT 122.112 217.968 122.136 218.160 ;
    END
  END ib[454]
  PIN ib[455]
    DIRECTION INPUT ;
    USE SIGNAL ;
    PORT
      LAYER M5 ;
        RECT 122.400 217.968 122.424 218.160 ;
    END
  END ib[455]
  PIN ib[456]
    DIRECTION INPUT ;
    USE SIGNAL ;
    PORT
      LAYER M5 ;
        RECT 122.640 217.968 122.664 218.160 ;
    END
  END ib[456]
  PIN ib[457]
    DIRECTION INPUT ;
    USE SIGNAL ;
    PORT
      LAYER M5 ;
        RECT 122.880 217.968 122.904 218.160 ;
    END
  END ib[457]
  PIN ib[458]
    DIRECTION INPUT ;
    USE SIGNAL ;
    PORT
      LAYER M5 ;
        RECT 123.168 217.968 123.192 218.160 ;
    END
  END ib[458]
  PIN ib[459]
    DIRECTION INPUT ;
    USE SIGNAL ;
    PORT
      LAYER M5 ;
        RECT 123.408 217.968 123.432 218.160 ;
    END
  END ib[459]
  PIN ib[460]
    DIRECTION INPUT ;
    USE SIGNAL ;
    PORT
      LAYER M5 ;
        RECT 123.648 217.968 123.672 218.160 ;
    END
  END ib[460]
  PIN ib[461]
    DIRECTION INPUT ;
    USE SIGNAL ;
    PORT
      LAYER M5 ;
        RECT 123.936 217.968 123.960 218.160 ;
    END
  END ib[461]
  PIN ib[462]
    DIRECTION INPUT ;
    USE SIGNAL ;
    PORT
      LAYER M5 ;
        RECT 124.176 217.968 124.200 218.160 ;
    END
  END ib[462]
  PIN ib[463]
    DIRECTION INPUT ;
    USE SIGNAL ;
    PORT
      LAYER M5 ;
        RECT 124.416 217.968 124.440 218.160 ;
    END
  END ib[463]
  PIN ib[464]
    DIRECTION INPUT ;
    USE SIGNAL ;
    PORT
      LAYER M5 ;
        RECT 124.704 217.968 124.728 218.160 ;
    END
  END ib[464]
  PIN ib[465]
    DIRECTION INPUT ;
    USE SIGNAL ;
    PORT
      LAYER M5 ;
        RECT 124.944 217.968 124.968 218.160 ;
    END
  END ib[465]
  PIN ib[466]
    DIRECTION INPUT ;
    USE SIGNAL ;
    PORT
      LAYER M5 ;
        RECT 125.232 217.968 125.256 218.160 ;
    END
  END ib[466]
  PIN ib[467]
    DIRECTION INPUT ;
    USE SIGNAL ;
    PORT
      LAYER M5 ;
        RECT 125.472 217.968 125.496 218.160 ;
    END
  END ib[467]
  PIN ib[468]
    DIRECTION INPUT ;
    USE SIGNAL ;
    PORT
      LAYER M5 ;
        RECT 125.712 217.968 125.736 218.160 ;
    END
  END ib[468]
  PIN ib[469]
    DIRECTION INPUT ;
    USE SIGNAL ;
    PORT
      LAYER M5 ;
        RECT 126.000 217.968 126.024 218.160 ;
    END
  END ib[469]
  PIN ib[470]
    DIRECTION INPUT ;
    USE SIGNAL ;
    PORT
      LAYER M5 ;
        RECT 126.240 217.968 126.264 218.160 ;
    END
  END ib[470]
  PIN ib[471]
    DIRECTION INPUT ;
    USE SIGNAL ;
    PORT
      LAYER M5 ;
        RECT 126.480 217.968 126.504 218.160 ;
    END
  END ib[471]
  PIN ib[472]
    DIRECTION INPUT ;
    USE SIGNAL ;
    PORT
      LAYER M5 ;
        RECT 126.768 217.968 126.792 218.160 ;
    END
  END ib[472]
  PIN ib[473]
    DIRECTION INPUT ;
    USE SIGNAL ;
    PORT
      LAYER M5 ;
        RECT 127.008 217.968 127.032 218.160 ;
    END
  END ib[473]
  PIN ib[474]
    DIRECTION INPUT ;
    USE SIGNAL ;
    PORT
      LAYER M5 ;
        RECT 127.248 217.968 127.272 218.160 ;
    END
  END ib[474]
  PIN ib[475]
    DIRECTION INPUT ;
    USE SIGNAL ;
    PORT
      LAYER M5 ;
        RECT 127.536 217.968 127.560 218.160 ;
    END
  END ib[475]
  PIN ib[476]
    DIRECTION INPUT ;
    USE SIGNAL ;
    PORT
      LAYER M5 ;
        RECT 127.776 217.968 127.800 218.160 ;
    END
  END ib[476]
  PIN ib[477]
    DIRECTION INPUT ;
    USE SIGNAL ;
    PORT
      LAYER M5 ;
        RECT 128.016 217.968 128.040 218.160 ;
    END
  END ib[477]
  PIN ib[478]
    DIRECTION INPUT ;
    USE SIGNAL ;
    PORT
      LAYER M5 ;
        RECT 128.304 217.968 128.328 218.160 ;
    END
  END ib[478]
  PIN ib[479]
    DIRECTION INPUT ;
    USE SIGNAL ;
    PORT
      LAYER M5 ;
        RECT 128.544 217.968 128.568 218.160 ;
    END
  END ib[479]
  PIN ib[480]
    DIRECTION INPUT ;
    USE SIGNAL ;
    PORT
      LAYER M5 ;
        RECT 128.784 217.968 128.808 218.160 ;
    END
  END ib[480]
  PIN ib[481]
    DIRECTION INPUT ;
    USE SIGNAL ;
    PORT
      LAYER M5 ;
        RECT 129.072 217.968 129.096 218.160 ;
    END
  END ib[481]
  PIN ib[482]
    DIRECTION INPUT ;
    USE SIGNAL ;
    PORT
      LAYER M5 ;
        RECT 129.312 217.968 129.336 218.160 ;
    END
  END ib[482]
  PIN ib[483]
    DIRECTION INPUT ;
    USE SIGNAL ;
    PORT
      LAYER M5 ;
        RECT 129.600 217.968 129.624 218.160 ;
    END
  END ib[483]
  PIN ib[484]
    DIRECTION INPUT ;
    USE SIGNAL ;
    PORT
      LAYER M5 ;
        RECT 129.840 217.968 129.864 218.160 ;
    END
  END ib[484]
  PIN ib[485]
    DIRECTION INPUT ;
    USE SIGNAL ;
    PORT
      LAYER M5 ;
        RECT 130.080 217.968 130.104 218.160 ;
    END
  END ib[485]
  PIN ib[486]
    DIRECTION INPUT ;
    USE SIGNAL ;
    PORT
      LAYER M5 ;
        RECT 130.368 217.968 130.392 218.160 ;
    END
  END ib[486]
  PIN ib[487]
    DIRECTION INPUT ;
    USE SIGNAL ;
    PORT
      LAYER M5 ;
        RECT 130.608 217.968 130.632 218.160 ;
    END
  END ib[487]
  PIN ib[488]
    DIRECTION INPUT ;
    USE SIGNAL ;
    PORT
      LAYER M5 ;
        RECT 130.848 217.968 130.872 218.160 ;
    END
  END ib[488]
  PIN ib[489]
    DIRECTION INPUT ;
    USE SIGNAL ;
    PORT
      LAYER M5 ;
        RECT 131.136 217.968 131.160 218.160 ;
    END
  END ib[489]
  PIN ib[490]
    DIRECTION INPUT ;
    USE SIGNAL ;
    PORT
      LAYER M5 ;
        RECT 131.376 217.968 131.400 218.160 ;
    END
  END ib[490]
  PIN ib[491]
    DIRECTION INPUT ;
    USE SIGNAL ;
    PORT
      LAYER M5 ;
        RECT 131.616 217.968 131.640 218.160 ;
    END
  END ib[491]
  PIN ib[492]
    DIRECTION INPUT ;
    USE SIGNAL ;
    PORT
      LAYER M5 ;
        RECT 131.904 217.968 131.928 218.160 ;
    END
  END ib[492]
  PIN ib[493]
    DIRECTION INPUT ;
    USE SIGNAL ;
    PORT
      LAYER M5 ;
        RECT 132.144 217.968 132.168 218.160 ;
    END
  END ib[493]
  PIN ib[494]
    DIRECTION INPUT ;
    USE SIGNAL ;
    PORT
      LAYER M5 ;
        RECT 132.384 217.968 132.408 218.160 ;
    END
  END ib[494]
  PIN ib[495]
    DIRECTION INPUT ;
    USE SIGNAL ;
    PORT
      LAYER M5 ;
        RECT 132.672 217.968 132.696 218.160 ;
    END
  END ib[495]
  PIN ib[496]
    DIRECTION INPUT ;
    USE SIGNAL ;
    PORT
      LAYER M5 ;
        RECT 132.912 217.968 132.936 218.160 ;
    END
  END ib[496]
  PIN ib[497]
    DIRECTION INPUT ;
    USE SIGNAL ;
    PORT
      LAYER M5 ;
        RECT 133.200 217.968 133.224 218.160 ;
    END
  END ib[497]
  PIN ib[498]
    DIRECTION INPUT ;
    USE SIGNAL ;
    PORT
      LAYER M5 ;
        RECT 133.440 217.968 133.464 218.160 ;
    END
  END ib[498]
  PIN ib[499]
    DIRECTION INPUT ;
    USE SIGNAL ;
    PORT
      LAYER M5 ;
        RECT 133.680 217.968 133.704 218.160 ;
    END
  END ib[499]
  PIN ib[500]
    DIRECTION INPUT ;
    USE SIGNAL ;
    PORT
      LAYER M5 ;
        RECT 133.968 217.968 133.992 218.160 ;
    END
  END ib[500]
  PIN ib[501]
    DIRECTION INPUT ;
    USE SIGNAL ;
    PORT
      LAYER M5 ;
        RECT 134.208 217.968 134.232 218.160 ;
    END
  END ib[501]
  PIN ib[502]
    DIRECTION INPUT ;
    USE SIGNAL ;
    PORT
      LAYER M5 ;
        RECT 134.448 217.968 134.472 218.160 ;
    END
  END ib[502]
  PIN ib[503]
    DIRECTION INPUT ;
    USE SIGNAL ;
    PORT
      LAYER M5 ;
        RECT 134.736 217.968 134.760 218.160 ;
    END
  END ib[503]
  PIN ib[504]
    DIRECTION INPUT ;
    USE SIGNAL ;
    PORT
      LAYER M5 ;
        RECT 134.976 217.968 135.000 218.160 ;
    END
  END ib[504]
  PIN ib[505]
    DIRECTION INPUT ;
    USE SIGNAL ;
    PORT
      LAYER M5 ;
        RECT 135.216 217.968 135.240 218.160 ;
    END
  END ib[505]
  PIN ib[506]
    DIRECTION INPUT ;
    USE SIGNAL ;
    PORT
      LAYER M5 ;
        RECT 135.504 217.968 135.528 218.160 ;
    END
  END ib[506]
  PIN ib[507]
    DIRECTION INPUT ;
    USE SIGNAL ;
    PORT
      LAYER M5 ;
        RECT 135.744 217.968 135.768 218.160 ;
    END
  END ib[507]
  PIN ib[508]
    DIRECTION INPUT ;
    USE SIGNAL ;
    PORT
      LAYER M5 ;
        RECT 135.984 217.968 136.008 218.160 ;
    END
  END ib[508]
  PIN ib[509]
    DIRECTION INPUT ;
    USE SIGNAL ;
    PORT
      LAYER M5 ;
        RECT 136.272 217.968 136.296 218.160 ;
    END
  END ib[509]
  PIN ib[510]
    DIRECTION INPUT ;
    USE SIGNAL ;
    PORT
      LAYER M5 ;
        RECT 136.512 217.968 136.536 218.160 ;
    END
  END ib[510]
  PIN ib[511]
    DIRECTION INPUT ;
    USE SIGNAL ;
    PORT
      LAYER M5 ;
        RECT 136.752 217.968 136.776 218.160 ;
    END
  END ib[511]
  PIN ib[512]
    DIRECTION INPUT ;
    USE SIGNAL ;
    PORT
      LAYER M5 ;
        RECT 137.040 217.968 137.064 218.160 ;
    END
  END ib[512]
  PIN ib[513]
    DIRECTION INPUT ;
    USE SIGNAL ;
    PORT
      LAYER M5 ;
        RECT 137.280 217.968 137.304 218.160 ;
    END
  END ib[513]
  PIN ib[514]
    DIRECTION INPUT ;
    USE SIGNAL ;
    PORT
      LAYER M5 ;
        RECT 137.568 217.968 137.592 218.160 ;
    END
  END ib[514]
  PIN ib[515]
    DIRECTION INPUT ;
    USE SIGNAL ;
    PORT
      LAYER M5 ;
        RECT 137.808 217.968 137.832 218.160 ;
    END
  END ib[515]
  PIN ib[516]
    DIRECTION INPUT ;
    USE SIGNAL ;
    PORT
      LAYER M5 ;
        RECT 138.048 217.968 138.072 218.160 ;
    END
  END ib[516]
  PIN ib[517]
    DIRECTION INPUT ;
    USE SIGNAL ;
    PORT
      LAYER M5 ;
        RECT 138.336 217.968 138.360 218.160 ;
    END
  END ib[517]
  PIN ib[518]
    DIRECTION INPUT ;
    USE SIGNAL ;
    PORT
      LAYER M5 ;
        RECT 138.576 217.968 138.600 218.160 ;
    END
  END ib[518]
  PIN ib[519]
    DIRECTION INPUT ;
    USE SIGNAL ;
    PORT
      LAYER M5 ;
        RECT 138.816 217.968 138.840 218.160 ;
    END
  END ib[519]
  PIN ib[520]
    DIRECTION INPUT ;
    USE SIGNAL ;
    PORT
      LAYER M5 ;
        RECT 139.104 217.968 139.128 218.160 ;
    END
  END ib[520]
  PIN ib[521]
    DIRECTION INPUT ;
    USE SIGNAL ;
    PORT
      LAYER M5 ;
        RECT 139.344 217.968 139.368 218.160 ;
    END
  END ib[521]
  PIN ib[522]
    DIRECTION INPUT ;
    USE SIGNAL ;
    PORT
      LAYER M5 ;
        RECT 139.584 217.968 139.608 218.160 ;
    END
  END ib[522]
  PIN ib[523]
    DIRECTION INPUT ;
    USE SIGNAL ;
    PORT
      LAYER M5 ;
        RECT 139.872 217.968 139.896 218.160 ;
    END
  END ib[523]
  PIN ib[524]
    DIRECTION INPUT ;
    USE SIGNAL ;
    PORT
      LAYER M5 ;
        RECT 140.112 217.968 140.136 218.160 ;
    END
  END ib[524]
  PIN ib[525]
    DIRECTION INPUT ;
    USE SIGNAL ;
    PORT
      LAYER M5 ;
        RECT 140.352 217.968 140.376 218.160 ;
    END
  END ib[525]
  PIN ib[526]
    DIRECTION INPUT ;
    USE SIGNAL ;
    PORT
      LAYER M5 ;
        RECT 140.640 217.968 140.664 218.160 ;
    END
  END ib[526]
  PIN ib[527]
    DIRECTION INPUT ;
    USE SIGNAL ;
    PORT
      LAYER M5 ;
        RECT 140.880 217.968 140.904 218.160 ;
    END
  END ib[527]
  PIN ib[528]
    DIRECTION INPUT ;
    USE SIGNAL ;
    PORT
      LAYER M5 ;
        RECT 141.120 217.968 141.144 218.160 ;
    END
  END ib[528]
  PIN ib[529]
    DIRECTION INPUT ;
    USE SIGNAL ;
    PORT
      LAYER M5 ;
        RECT 141.408 217.968 141.432 218.160 ;
    END
  END ib[529]
  PIN ib[530]
    DIRECTION INPUT ;
    USE SIGNAL ;
    PORT
      LAYER M5 ;
        RECT 141.648 217.968 141.672 218.160 ;
    END
  END ib[530]
  PIN ib[531]
    DIRECTION INPUT ;
    USE SIGNAL ;
    PORT
      LAYER M5 ;
        RECT 141.936 217.968 141.960 218.160 ;
    END
  END ib[531]
  PIN ib[532]
    DIRECTION INPUT ;
    USE SIGNAL ;
    PORT
      LAYER M5 ;
        RECT 142.176 217.968 142.200 218.160 ;
    END
  END ib[532]
  PIN ib[533]
    DIRECTION INPUT ;
    USE SIGNAL ;
    PORT
      LAYER M5 ;
        RECT 142.416 217.968 142.440 218.160 ;
    END
  END ib[533]
  PIN ib[534]
    DIRECTION INPUT ;
    USE SIGNAL ;
    PORT
      LAYER M5 ;
        RECT 142.704 217.968 142.728 218.160 ;
    END
  END ib[534]
  PIN ib[535]
    DIRECTION INPUT ;
    USE SIGNAL ;
    PORT
      LAYER M5 ;
        RECT 142.944 217.968 142.968 218.160 ;
    END
  END ib[535]
  PIN ib[536]
    DIRECTION INPUT ;
    USE SIGNAL ;
    PORT
      LAYER M5 ;
        RECT 143.184 217.968 143.208 218.160 ;
    END
  END ib[536]
  PIN ib[537]
    DIRECTION INPUT ;
    USE SIGNAL ;
    PORT
      LAYER M5 ;
        RECT 143.472 217.968 143.496 218.160 ;
    END
  END ib[537]
  PIN ib[538]
    DIRECTION INPUT ;
    USE SIGNAL ;
    PORT
      LAYER M5 ;
        RECT 143.712 217.968 143.736 218.160 ;
    END
  END ib[538]
  PIN ib[539]
    DIRECTION INPUT ;
    USE SIGNAL ;
    PORT
      LAYER M5 ;
        RECT 143.952 217.968 143.976 218.160 ;
    END
  END ib[539]
  PIN ib[540]
    DIRECTION INPUT ;
    USE SIGNAL ;
    PORT
      LAYER M5 ;
        RECT 144.240 217.968 144.264 218.160 ;
    END
  END ib[540]
  PIN ib[541]
    DIRECTION INPUT ;
    USE SIGNAL ;
    PORT
      LAYER M5 ;
        RECT 144.480 217.968 144.504 218.160 ;
    END
  END ib[541]
  PIN ib[542]
    DIRECTION INPUT ;
    USE SIGNAL ;
    PORT
      LAYER M5 ;
        RECT 144.720 217.968 144.744 218.160 ;
    END
  END ib[542]
  PIN ib[543]
    DIRECTION INPUT ;
    USE SIGNAL ;
    PORT
      LAYER M5 ;
        RECT 145.008 217.968 145.032 218.160 ;
    END
  END ib[543]
  PIN ib[544]
    DIRECTION INPUT ;
    USE SIGNAL ;
    PORT
      LAYER M5 ;
        RECT 145.248 217.968 145.272 218.160 ;
    END
  END ib[544]
  PIN ib[545]
    DIRECTION INPUT ;
    USE SIGNAL ;
    PORT
      LAYER M5 ;
        RECT 145.488 217.968 145.512 218.160 ;
    END
  END ib[545]
  PIN ib[546]
    DIRECTION INPUT ;
    USE SIGNAL ;
    PORT
      LAYER M5 ;
        RECT 145.776 217.968 145.800 218.160 ;
    END
  END ib[546]
  PIN ib[547]
    DIRECTION INPUT ;
    USE SIGNAL ;
    PORT
      LAYER M5 ;
        RECT 146.016 217.968 146.040 218.160 ;
    END
  END ib[547]
  PIN ib[548]
    DIRECTION INPUT ;
    USE SIGNAL ;
    PORT
      LAYER M5 ;
        RECT 146.304 217.968 146.328 218.160 ;
    END
  END ib[548]
  PIN ib[549]
    DIRECTION INPUT ;
    USE SIGNAL ;
    PORT
      LAYER M5 ;
        RECT 146.544 217.968 146.568 218.160 ;
    END
  END ib[549]
  PIN ib[550]
    DIRECTION INPUT ;
    USE SIGNAL ;
    PORT
      LAYER M5 ;
        RECT 146.784 217.968 146.808 218.160 ;
    END
  END ib[550]
  PIN ib[551]
    DIRECTION INPUT ;
    USE SIGNAL ;
    PORT
      LAYER M5 ;
        RECT 147.072 217.968 147.096 218.160 ;
    END
  END ib[551]
  PIN ib[552]
    DIRECTION INPUT ;
    USE SIGNAL ;
    PORT
      LAYER M5 ;
        RECT 147.312 217.968 147.336 218.160 ;
    END
  END ib[552]
  PIN ib[553]
    DIRECTION INPUT ;
    USE SIGNAL ;
    PORT
      LAYER M5 ;
        RECT 147.552 217.968 147.576 218.160 ;
    END
  END ib[553]
  PIN ib[554]
    DIRECTION INPUT ;
    USE SIGNAL ;
    PORT
      LAYER M5 ;
        RECT 147.840 217.968 147.864 218.160 ;
    END
  END ib[554]
  PIN ib[555]
    DIRECTION INPUT ;
    USE SIGNAL ;
    PORT
      LAYER M5 ;
        RECT 148.080 217.968 148.104 218.160 ;
    END
  END ib[555]
  PIN ib[556]
    DIRECTION INPUT ;
    USE SIGNAL ;
    PORT
      LAYER M5 ;
        RECT 148.320 217.968 148.344 218.160 ;
    END
  END ib[556]
  PIN ib[557]
    DIRECTION INPUT ;
    USE SIGNAL ;
    PORT
      LAYER M5 ;
        RECT 148.608 217.968 148.632 218.160 ;
    END
  END ib[557]
  PIN ib[558]
    DIRECTION INPUT ;
    USE SIGNAL ;
    PORT
      LAYER M5 ;
        RECT 148.848 217.968 148.872 218.160 ;
    END
  END ib[558]
  PIN ib[559]
    DIRECTION INPUT ;
    USE SIGNAL ;
    PORT
      LAYER M5 ;
        RECT 149.088 217.968 149.112 218.160 ;
    END
  END ib[559]
  PIN ib[560]
    DIRECTION INPUT ;
    USE SIGNAL ;
    PORT
      LAYER M5 ;
        RECT 149.376 217.968 149.400 218.160 ;
    END
  END ib[560]
  PIN ib[561]
    DIRECTION INPUT ;
    USE SIGNAL ;
    PORT
      LAYER M5 ;
        RECT 149.616 217.968 149.640 218.160 ;
    END
  END ib[561]
  PIN ib[562]
    DIRECTION INPUT ;
    USE SIGNAL ;
    PORT
      LAYER M5 ;
        RECT 149.856 217.968 149.880 218.160 ;
    END
  END ib[562]
  PIN ib[563]
    DIRECTION INPUT ;
    USE SIGNAL ;
    PORT
      LAYER M5 ;
        RECT 150.144 217.968 150.168 218.160 ;
    END
  END ib[563]
  PIN ib[564]
    DIRECTION INPUT ;
    USE SIGNAL ;
    PORT
      LAYER M5 ;
        RECT 150.384 217.968 150.408 218.160 ;
    END
  END ib[564]
  PIN ib[565]
    DIRECTION INPUT ;
    USE SIGNAL ;
    PORT
      LAYER M5 ;
        RECT 150.672 217.968 150.696 218.160 ;
    END
  END ib[565]
  PIN ib[566]
    DIRECTION INPUT ;
    USE SIGNAL ;
    PORT
      LAYER M5 ;
        RECT 150.912 217.968 150.936 218.160 ;
    END
  END ib[566]
  PIN ib[567]
    DIRECTION INPUT ;
    USE SIGNAL ;
    PORT
      LAYER M5 ;
        RECT 151.152 217.968 151.176 218.160 ;
    END
  END ib[567]
  PIN ib[568]
    DIRECTION INPUT ;
    USE SIGNAL ;
    PORT
      LAYER M5 ;
        RECT 151.440 217.968 151.464 218.160 ;
    END
  END ib[568]
  PIN ib[569]
    DIRECTION INPUT ;
    USE SIGNAL ;
    PORT
      LAYER M5 ;
        RECT 151.680 217.968 151.704 218.160 ;
    END
  END ib[569]
  PIN ib[570]
    DIRECTION INPUT ;
    USE SIGNAL ;
    PORT
      LAYER M5 ;
        RECT 151.920 217.968 151.944 218.160 ;
    END
  END ib[570]
  PIN ib[571]
    DIRECTION INPUT ;
    USE SIGNAL ;
    PORT
      LAYER M5 ;
        RECT 152.208 217.968 152.232 218.160 ;
    END
  END ib[571]
  PIN ib[572]
    DIRECTION INPUT ;
    USE SIGNAL ;
    PORT
      LAYER M5 ;
        RECT 152.448 217.968 152.472 218.160 ;
    END
  END ib[572]
  PIN ib[573]
    DIRECTION INPUT ;
    USE SIGNAL ;
    PORT
      LAYER M5 ;
        RECT 152.688 217.968 152.712 218.160 ;
    END
  END ib[573]
  PIN ib[574]
    DIRECTION INPUT ;
    USE SIGNAL ;
    PORT
      LAYER M5 ;
        RECT 152.976 217.968 153.000 218.160 ;
    END
  END ib[574]
  PIN ib[575]
    DIRECTION INPUT ;
    USE SIGNAL ;
    PORT
      LAYER M5 ;
        RECT 153.216 217.968 153.240 218.160 ;
    END
  END ib[575]
  PIN ov
    DIRECTION OUTPUT ;
    USE SIGNAL ;
    PORT
      LAYER M4 ;
        RECT 157.488 89.664 157.680 89.688 ;
    END
  END ov
  PIN oy[0]
    DIRECTION OUTPUT ;
    USE SIGNAL ;
    PORT
      LAYER M4 ;
        RECT 157.488 90.816 157.680 90.840 ;
    END
  END oy[0]
  PIN oy[1]
    DIRECTION OUTPUT ;
    USE SIGNAL ;
    PORT
      LAYER M4 ;
        RECT 157.488 92.016 157.680 92.040 ;
    END
  END oy[1]
  PIN oy[2]
    DIRECTION OUTPUT ;
    USE SIGNAL ;
    PORT
      LAYER M4 ;
        RECT 157.488 93.168 157.680 93.192 ;
    END
  END oy[2]
  PIN oy[3]
    DIRECTION OUTPUT ;
    USE SIGNAL ;
    PORT
      LAYER M4 ;
        RECT 157.488 94.368 157.680 94.392 ;
    END
  END oy[3]
  PIN oy[4]
    DIRECTION OUTPUT ;
    USE SIGNAL ;
    PORT
      LAYER M4 ;
        RECT 157.488 95.520 157.680 95.544 ;
    END
  END oy[4]
  PIN oy[5]
    DIRECTION OUTPUT ;
    USE SIGNAL ;
    PORT
      LAYER M4 ;
        RECT 157.488 96.720 157.680 96.744 ;
    END
  END oy[5]
  PIN oy[6]
    DIRECTION OUTPUT ;
    USE SIGNAL ;
    PORT
      LAYER M4 ;
        RECT 157.488 97.872 157.680 97.896 ;
    END
  END oy[6]
  PIN oy[7]
    DIRECTION OUTPUT ;
    USE SIGNAL ;
    PORT
      LAYER M4 ;
        RECT 157.488 99.072 157.680 99.096 ;
    END
  END oy[7]
  PIN oy[8]
    DIRECTION OUTPUT ;
    USE SIGNAL ;
    PORT
      LAYER M4 ;
        RECT 157.488 100.224 157.680 100.248 ;
    END
  END oy[8]
  PIN oy[9]
    DIRECTION OUTPUT ;
    USE SIGNAL ;
    PORT
      LAYER M4 ;
        RECT 157.488 101.424 157.680 101.448 ;
    END
  END oy[9]
  PIN oy[10]
    DIRECTION OUTPUT ;
    USE SIGNAL ;
    PORT
      LAYER M4 ;
        RECT 157.488 102.576 157.680 102.600 ;
    END
  END oy[10]
  PIN oy[11]
    DIRECTION OUTPUT ;
    USE SIGNAL ;
    PORT
      LAYER M4 ;
        RECT 157.488 103.776 157.680 103.800 ;
    END
  END oy[11]
  PIN oy[12]
    DIRECTION OUTPUT ;
    USE SIGNAL ;
    PORT
      LAYER M4 ;
        RECT 157.488 104.928 157.680 104.952 ;
    END
  END oy[12]
  PIN oy[13]
    DIRECTION OUTPUT ;
    USE SIGNAL ;
    PORT
      LAYER M4 ;
        RECT 157.488 106.128 157.680 106.152 ;
    END
  END oy[13]
  PIN oy[14]
    DIRECTION OUTPUT ;
    USE SIGNAL ;
    PORT
      LAYER M4 ;
        RECT 157.488 107.280 157.680 107.304 ;
    END
  END oy[14]
  PIN oy[15]
    DIRECTION OUTPUT ;
    USE SIGNAL ;
    PORT
      LAYER M4 ;
        RECT 157.488 108.480 157.680 108.504 ;
    END
  END oy[15]
  PIN oy[16]
    DIRECTION OUTPUT ;
    USE SIGNAL ;
    PORT
      LAYER M4 ;
        RECT 157.488 109.680 157.680 109.704 ;
    END
  END oy[16]
  PIN oy[17]
    DIRECTION OUTPUT ;
    USE SIGNAL ;
    PORT
      LAYER M4 ;
        RECT 157.488 110.832 157.680 110.856 ;
    END
  END oy[17]
  PIN oy[18]
    DIRECTION OUTPUT ;
    USE SIGNAL ;
    PORT
      LAYER M4 ;
        RECT 157.488 112.032 157.680 112.056 ;
    END
  END oy[18]
  PIN oy[19]
    DIRECTION OUTPUT ;
    USE SIGNAL ;
    PORT
      LAYER M4 ;
        RECT 157.488 113.184 157.680 113.208 ;
    END
  END oy[19]
  PIN oy[20]
    DIRECTION OUTPUT ;
    USE SIGNAL ;
    PORT
      LAYER M4 ;
        RECT 157.488 114.384 157.680 114.408 ;
    END
  END oy[20]
  PIN oy[21]
    DIRECTION OUTPUT ;
    USE SIGNAL ;
    PORT
      LAYER M4 ;
        RECT 157.488 115.536 157.680 115.560 ;
    END
  END oy[21]
  PIN oy[22]
    DIRECTION OUTPUT ;
    USE SIGNAL ;
    PORT
      LAYER M4 ;
        RECT 157.488 116.736 157.680 116.760 ;
    END
  END oy[22]
  PIN oy[23]
    DIRECTION OUTPUT ;
    USE SIGNAL ;
    PORT
      LAYER M4 ;
        RECT 157.488 117.888 157.680 117.912 ;
    END
  END oy[23]
  PIN oy[24]
    DIRECTION OUTPUT ;
    USE SIGNAL ;
    PORT
      LAYER M4 ;
        RECT 157.488 119.088 157.680 119.112 ;
    END
  END oy[24]
  PIN oy[25]
    DIRECTION OUTPUT ;
    USE SIGNAL ;
    PORT
      LAYER M4 ;
        RECT 157.488 120.240 157.680 120.264 ;
    END
  END oy[25]
  PIN oy[26]
    DIRECTION OUTPUT ;
    USE SIGNAL ;
    PORT
      LAYER M4 ;
        RECT 157.488 121.440 157.680 121.464 ;
    END
  END oy[26]
  PIN oy[27]
    DIRECTION OUTPUT ;
    USE SIGNAL ;
    PORT
      LAYER M4 ;
        RECT 157.488 122.592 157.680 122.616 ;
    END
  END oy[27]
  PIN oy[28]
    DIRECTION OUTPUT ;
    USE SIGNAL ;
    PORT
      LAYER M4 ;
        RECT 157.488 123.792 157.680 123.816 ;
    END
  END oy[28]
  PIN oy[29]
    DIRECTION OUTPUT ;
    USE SIGNAL ;
    PORT
      LAYER M4 ;
        RECT 157.488 124.944 157.680 124.968 ;
    END
  END oy[29]
  PIN oy[30]
    DIRECTION OUTPUT ;
    USE SIGNAL ;
    PORT
      LAYER M4 ;
        RECT 157.488 126.144 157.680 126.168 ;
    END
  END oy[30]
  PIN oy[31]
    DIRECTION OUTPUT ;
    USE SIGNAL ;
    PORT
      LAYER M4 ;
        RECT 157.488 127.296 157.680 127.320 ;
    END
  END oy[31]
  PIN oflt
    DIRECTION OUTPUT ;
    USE SIGNAL ;
    PORT
      LAYER M4 ;
        RECT 157.488 128.496 157.680 128.520 ;
    END
  END oflt
  PIN gid[0]
    DIRECTION INPUT ;
    USE SIGNAL ;
    PORT
      LAYER M4 ;
        RECT 157.488 20.592 157.680 20.616 ;
    END
  END gid[0]
  PIN gid[1]
    DIRECTION INPUT ;
    USE SIGNAL ;
    PORT
      LAYER M4 ;
        RECT 157.488 21.840 157.680 21.864 ;
    END
  END gid[1]
  PIN gid[2]
    DIRECTION INPUT ;
    USE SIGNAL ;
    PORT
      LAYER M4 ;
        RECT 157.488 23.136 157.680 23.160 ;
    END
  END gid[2]
  PIN gid[3]
    DIRECTION INPUT ;
    USE SIGNAL ;
    PORT
      LAYER M4 ;
        RECT 157.488 24.384 157.680 24.408 ;
    END
  END gid[3]
  PIN gid[4]
    DIRECTION INPUT ;
    USE SIGNAL ;
    PORT
      LAYER M4 ;
        RECT 157.488 25.632 157.680 25.656 ;
    END
  END gid[4]
  PIN gid[5]
    DIRECTION INPUT ;
    USE SIGNAL ;
    PORT
      LAYER M4 ;
        RECT 157.488 26.880 157.680 26.904 ;
    END
  END gid[5]
  PIN gid[6]
    DIRECTION INPUT ;
    USE SIGNAL ;
    PORT
      LAYER M4 ;
        RECT 157.488 28.128 157.680 28.152 ;
    END
  END gid[6]
  PIN gid[7]
    DIRECTION INPUT ;
    USE SIGNAL ;
    PORT
      LAYER M4 ;
        RECT 157.488 29.376 157.680 29.400 ;
    END
  END gid[7]
  PIN clk
    DIRECTION INPUT ;
    USE CLOCK ;
    PORT
      LAYER M5 ;
        RECT 78.816 0.000 78.840 0.192 ;
    END
  END clk
  PIN rst_n
    DIRECTION INPUT ;
    USE SIGNAL ;
    PORT
      LAYER M5 ;
        RECT 81.840 0.000 81.864 0.192 ;
    END
  END rst_n
  PIN VDD
    DIRECTION INOUT ;
    USE POWER ;
  END VDD
  PIN VSS
    DIRECTION INOUT ;
    USE GROUND ;
  END VSS
  OBS
    LAYER M1 ;
      RECT 0.200 0.200 157.480 217.960 ;
    LAYER M2 ;
      RECT 0.200 0.200 157.480 217.960 ;
    LAYER M3 ;
      RECT 0.200 0.200 157.480 217.960 ;
    LAYER M4 ;
      RECT 0.200 0.200 157.480 217.960 ;
    LAYER M5 ;
      RECT 0.200 0.200 157.480 217.960 ;
  END
END ot_s81c_attn_hcore
END LIBRARY
